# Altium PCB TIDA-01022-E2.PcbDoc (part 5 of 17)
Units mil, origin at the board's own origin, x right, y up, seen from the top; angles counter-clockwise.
Board outline 6929.13 x 11614.17 mil, 12 copper layers (L1_Top Layer, L2_GND, L3_GND, L4_Signal Layer 1, L5_GND, L6_PWR, L7_GND/PWR, L8_PWR, L9_GND/PWR, L10_Signal Layer 2, L11_GND, L12_Bottom Layer), stack 64.6 mil thick; 1711 components, 1002 nets, 5985 pads, 3200 vias.

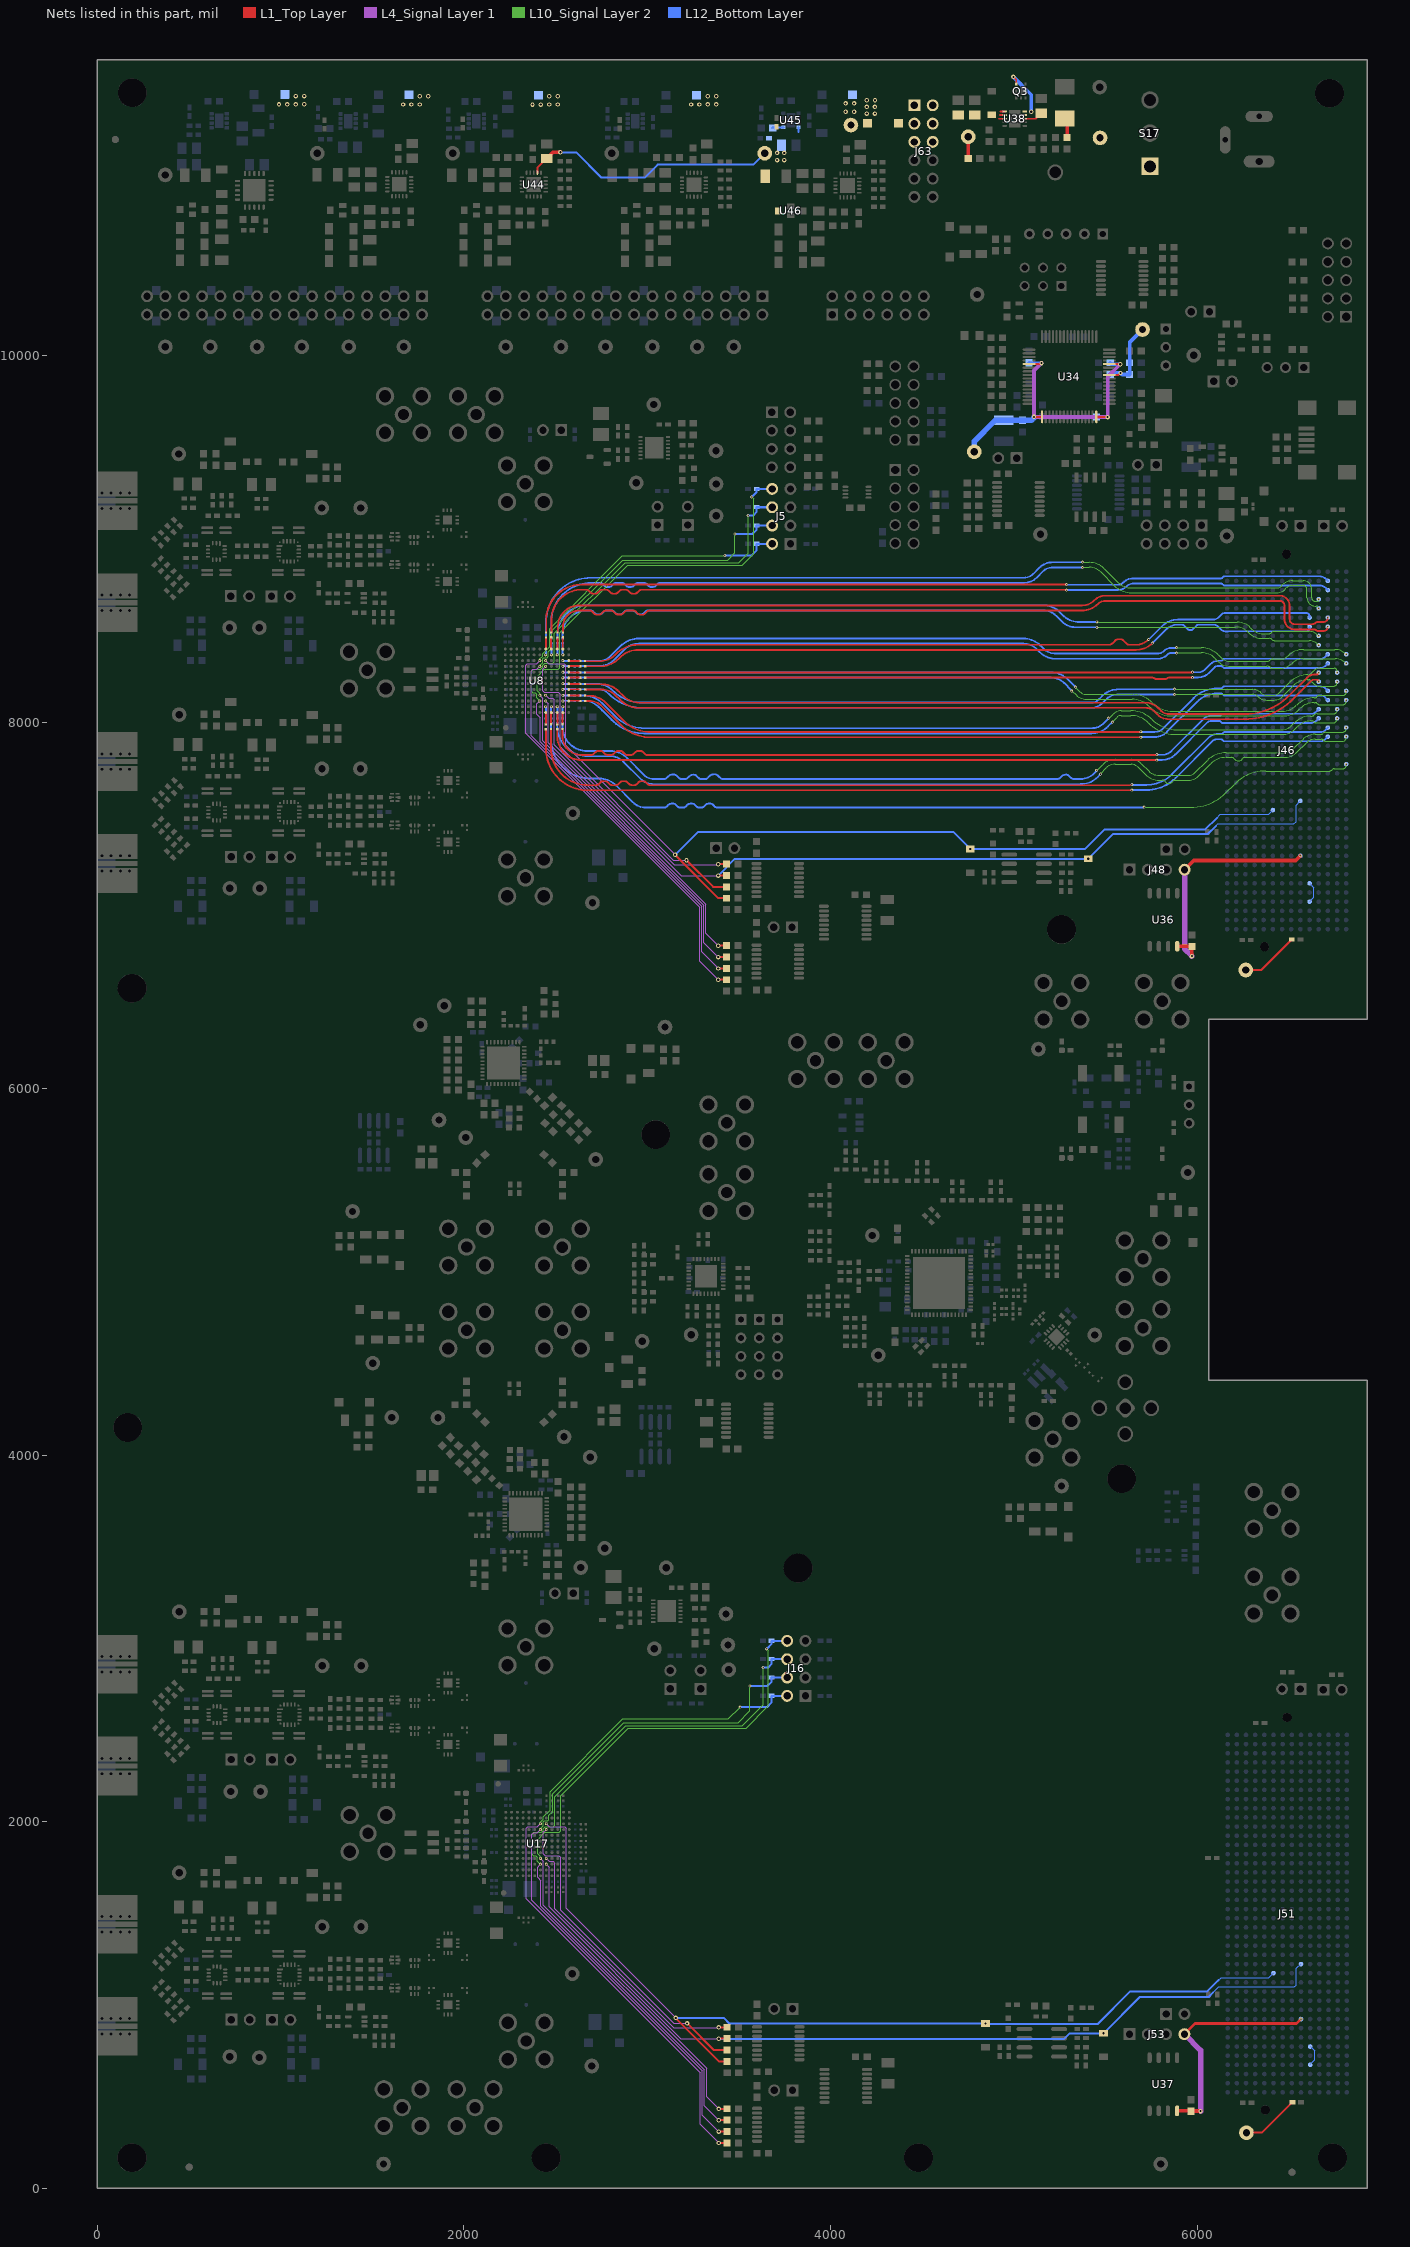
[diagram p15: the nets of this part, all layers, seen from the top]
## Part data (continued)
U55 U57 U58: "Remote 8-Bit I2C and Low-Power I/O Expander With Interrupt Output and Configuration Registers, PW0016A (TSSOP-16)"
U56: "1K Microwire Compatible Serial EEPROM"
U59 U60 U61 U62: "Broadband Balun, 500 kHz to 6 GHz"
U63 U64: "Single 2-Input Positive-AND Gate, DCK0005A (SOT-5)"
U65 U66 U67 U68 U69 U70 U71 U72: library part CMP-0077784-1, "Reflectionless Low Pass Filter, SMD"
U73: "Automotive LVDS Differential Line Receiver, 5-pin SOT-23, Pb-Free"
U74: library part NB7V32M, "1.8V / 2.5V, 10GHz ÷4 Clock Divider with CML Outputs, QFN-16"
U75: "IC, SPDT Analog Switch"
Y1: "VCXO, 100 MHz, 3.3V, SMD"
Y2: "Crystal, 12Mhz, 18pF, SMD"
ZZ1: library part AssemblyNoteLabel
ZZ2 ZZ3 ZZ4: library part AssemblyNote

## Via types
v1: diameter 16, hole 8, L1_Top Layer to L12_Bottom Layer, tented both sides, 1699 vias
v2: diameter 24, hole 12, L1_Top Layer to L12_Bottom Layer, tented both sides, 1501 vias

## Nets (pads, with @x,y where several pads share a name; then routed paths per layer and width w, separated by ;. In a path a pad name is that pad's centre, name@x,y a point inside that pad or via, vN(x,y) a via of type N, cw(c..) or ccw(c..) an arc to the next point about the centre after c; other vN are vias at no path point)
1P8V_USB: C459.2 C460.2 C461.2 C474.1 C736.1 TP14.1 U34.12 U34.37 U34.49 U34.64 | length 1895.7
  L1_Top Layer w10: U34.37@5083.38,9952.87 5145.27,9952.87 v2(5150.87,9958.47) ; v2(5110,9665) 5153.78,9665 U34.49@5154.25,9665.47 ; U34.64@5449.52,9665.47 5451.02,9663.97 v2(5511.37,9663.97) ; U34.12@5520.39,9952.87 5580.47,9952.87 v2(5580.87,9952.47)
  L4_Signal Layer 1 w20: v2(5150.87,9958.47) 5110,9917.6 v2(5110,9665) 5111.03,9663.97 v2(5511.37,9663.97) 5511.37,9882.97 v2(5580.87,9952.47)
  L12_Bottom Layer w10: v2@5145.9,9958.24 5146.13,9958.47 v2(5150.87,9958.47)
  L12_Bottom Layer w20: C461.2@5083.38,9960.74 5085.88,9958.24 v2@5145.9,9958.24 ; C459.2@5450.38,9663.97 v2(5511.37,9663.97) ; C460.2@5525.38,9959.97 5532.88,9952.47 v2(5580.87,9952.47)
  L12_Bottom Layer w30: TP14.1@4784,9475 4784,9532 4897.56,9645.56 C474.1@4944.87,9645.56 5047.46,9645.56 C736.1@5047.87,9645.97 5095.37,9645.97 5110,9660.59 v2(5110,9665)
3P3USB: C466.1 C467.2 L33.2 TP13.1 U34.9 | length 453.6
  L1_Top Layer w10: U34.9@5520.39,9893.81 5570.21,9893.81 5580.87,9904.47 v2(5581.87,9904.47)
  L12_Bottom Layer w20: C467.2@5525.38,9895.97 5533.88,9904.47 v2(5581.87,9904.47) 5590.37,9895.97 C466.1@5631.39,9895.97 L33.2@5631.39,9959.97 5631.39,10070.99 TP13.1@5701.87,10141.47
3P3V_RX1: 3P3V_RX1.1 R474.1 | length 319.4
  L1_Top Layer w11: 3P3V_RX1.1@6265.36,6647.2 6349.43,6647.2 R474.1@6515.86,6813.63
3P3V_RX2: 3P3V_RX2.1 R479.1 | length 319.4
  L1_Top Layer w11: 3P3V_RX2.1@6269,304 6353.07,304 R479.1@6519.5,470.43
3P3VAUX1: C475.1 J46.D32 J48.4 U36.8 | length 1284.5
  L1_Top Layer w20: U36.8@5891.21,6776.68 5967.95,6776.68 cw(c5967.95,6771.55) 5971.58,6775.18 5971,6774.6 v2(5971,6723) ; J48.4@5931.21,7194.68 5981.54,7245.01 6538.11,7245.01 v1(6563.11,7270.01)
  L4_Signal Layer 1 w30: J48.4@5931.21,7194.68 5931.21,6762.79 v2(5971,6723)
3P3VAUX2: C476.1 J51.D32 J53.4 U37.8 | length 1254.4
  L1_Top Layer w15: J53.4@5930.4,841.39 5988.82,899.81 6542.24,899.81 v1(6566.44,924.01)
  L1_Top Layer w20: U37.8@5890.4,423.39 5967.14,423.39 cw(c5967.14,418.26) 5970.77,421.89 v2(6018.28,421.89)
  L4_Signal Layer 1 w30: J53.4@5930.4,841.39 6018.28,753.51 v2(6018.28,421.89)
3P5_VIN: C594.1 C601.1 R513.2 R514.2 R515.2 R621.2 TP32.1 U44.12 U45.4 U45.5 U46.1 | length 1503.7
  L1_Top Layer w10: U44.12@2400.41,10997.46 2400.41,11023.85 C594.1@2451.09,11074.54
  L1_Top Layer w20: C594.1@2451.09,11074.54 2485.19,11108.63 v2(2526.2,11108.63)
  L12_Bottom Layer w10: R514.2@3681.29,11241.46 3684.23,11244.4 U45.5@3742.33,11244.4 ; 3825.01,11217.49 U45.4@3825.01,11244.4
  L12_Bottom Layer w11: v2(2526.2,11108.63) 2611.37,11108.63 2750,10970 2986,10970 3057,11041 3578.93,11041 TP32.1@3640.93,11103
  other v2: 3708,11066 3747,11066 3708,11105 3747,11105
12P0V_RX1: J46.C35 J46.C37 | length 120
  L12_Bottom Layer w5: J46.C37@6613.11,7020.01 6637.21,7044.11 6637.21,7095.91 J46.C35@6613.11,7120.01
12P0V_RX2: J51.C35 J51.C37 | length 120.7
  L12_Bottom Layer w5: J51.C37@6616.75,676.81 6641.75,701.81 6641.75,751.81 J51.C35@6616.75,776.81
12V: C477.1 C478.1 D20.1 J63.1 J63.2 J63.3 J63.4 J63.5 J63.6 L92.1 R485.2 TP18.1 U38.6 U38.7 U38.8 | length 196.5
  L1_Top Layer w10: 4919.4,11291.8 U38.8@4949.58,11291.8 ; 4925.09,11311.49 U38.7@4949.58,11311.49 ; 4925.77,11331.17 U38.6@4949.58,11331.17
  L1_Top Layer w20: R485.2@4750.82,11074.8 TP18.1@4750.82,11192.8
12V_DC: C479.1 D19.2 Q3.3 R484.2 S17.1 TP17.1 U38.3 U38.4 U38.5 | length 486.6
  L1_Top Layer w10: v2(4997.32,11519.73) 5012.82,11504.23 Q3.3@5012.82,11480.8 ; U38.3@5059.82,11291.8 5119.4,11291.8 C479.1@5149.32,11321.73
  L1_Top Layer w20: D19.2@5277.82,11292.8 5290.31,11280.3 R484.2@5290.31,11188.8
  L12_Bottom Layer w20: v2(4997.32,11519.73) 5094.32,11422.73 v2(5094.32,11329.73)
12VIN: L87.2 L88.2 L89.2 L90.2 L91.1 L92.2 TP77.1
  other v2: 4196.85,11319.34 4241.85,11319.34 4082.18,11330 4128.34,11330.08 4197,11356 4242,11356 1667.89,11369.14 1712.89,11369.14 1759.05,11369.21 2373.84,11368.92 2418.84,11368.92 2465,11369 2511.16,11369.08 990.84,11369.92 1035.84,11369.92 1082,11370 1128.16,11370.08 3239.09,11369.47 3284.09,11369.47 3330.26,11369.54 3376.42,11369.62 4082.18,11375 4128.34,11375.08 4197.15,11392.66 4242.15,11392.66 1759.05,11414.21 1805.21,11414.29 2465,11414 2511.16,11414.08 1082,11415 1128.16,11415.08 3330.26,11414.54 3376.42,11414.62
AADC1_NCOA0: J5.2 R59.1 R432.2 U8.C7 | length 3943.9
  L1_Top Layer w6: v2(3387.07,6593.73) v2@3387.56,6594.22
  L1_Top Layer w11: v2@3387.56,6594.22 R432.2@3431.97,6594.22
  L4_Signal Layer 1 w3.5: 2336.17,8025.29 2336.17,8310 2345.17,8319 2397.58,8319 v1(2413.91,8335.33)
  L4_Signal Layer 1 w5.5: 2336.17,8025.29 2336.17,7938.83 3285.5,6989.5 3285.5,6695.3 v2(3387.07,6593.73)
  L10_Signal Layer 2 w3.5: v1(2413.91,8335.33) 2413.91,8344.24 2429.91,8360.24 2429.91,8373.25 2466.67,8410.01 2466.67,8466.17
  L10_Signal Layer 2 w6.5: 2466.67,8466.17 2466.67,8510 2863.67,8907 3420.47,8907 v1(3423,8909.53)
  L12_Bottom Layer w11: v1(3423,8909.53) 3570,8909.53 3596.7,8936.23 R59.1@3596.7,8971.88 J5.2@3681.08,8971.88 ; J5.2@3649.67,8972 J5.2@3675.01,8997.33
AADC1_NCOA1: J5.4 R58.1 R434.2 U8.D7 | length 3891.3
  L1_Top Layer w6: v2(3387.07,6655.73) v2@3387.56,6656.22
  L1_Top Layer w11: v2@3387.56,6656.22 R434.2@3431.97,6656.22
  L4_Signal Layer 1 w3.5: 2367,8025.29 2367,8278 2376.09,8287.09 2397.17,8287.09 v1(2413.91,8303.83)
  L4_Signal Layer 1 w5.5: 2367,8025.29 2367,7925 3297,6995 3297,6745.8 v2(3387.07,6655.73)
  L10_Signal Layer 2 w3.5: v1(2413.91,8303.83) 2413.91,8309.24 2429.41,8324.74 2429.41,8345.74 2435,8351.33 2453,8351.33 2460.16,8358.49 2460.16,8382.49 2479.67,8402 2479.67,8466.67
  L10_Signal Layer 2 w6.5: 2479.67,8466.67 2479.67,8498 2865.67,8884 3438,8884 3478.36,8924.36 v1(3478.36,9025.89)
  L12_Bottom Layer w11: v1(3478.36,9025.89) 3573.36,9025.89 3596.7,9049.23 R58.1@3596.7,9071.88 J5.4@3681.08,9071.88
AADC1_NCOB0: J5.6 R53.1 R436.2 U8.K7 | length 3980.2
  L1_Top Layer w6: v2(3387.07,6717.73) v2@3387.56,6718.22
  L1_Top Layer w11: v2@3387.56,6718.22 R436.2@3431.97,6718.22
  L4_Signal Layer 1 w3.5: v1(2413.91,8114.86) 2398,8098.94 2398,8042 2415.63,8024.37
  L4_Signal Layer 1 w5.5: 2415.63,8024.37 2415.63,7893.37 3308.5,7000.5 3308.5,6796.3 v2(3387.07,6717.73)
  L10_Signal Layer 2 w3.5: 2365.67,8273 2365.67,8263 2365.67,8171 2375.56,8161.1 2388.53,8161.1 2397.17,8152.46 2397.17,8131.6 v1(2413.91,8114.86) ; 2365.67,8263 2365.67,8273 2365.67,8276.45 2377.06,8287.84 2418.78,8287.84 2429.41,8298.47 2429.41,8309 2440.25,8319.83 2484.5,8319.83 2492.67,8328 2492.67,8459.17
  L10_Signal Layer 2 w6.5: 2492.67,8459.17 2492.67,8484 2878.67,8870 3500,8870 3550.36,8920.36 v1(3550.36,9126.54)
  L12_Bottom Layer w6: R53.1@3596.7,9170.88 3597.7,9171.88 R53.1@3596.7,9172.88
  L12_Bottom Layer w11: v1(3550.36,9126.54) 3577.02,9126.54 3596.7,9146.23 3596.7,9170.88 R53.1@3596.7,9172.88 ; R53.1@3597.7,9171.88 J5.6@3681.08,9171.88
AADC1_NCOB1: J5.8 R52.1 R438.2 U8.J7 | length 3947.1
  L1_Top Layer w6: v2(3387.07,6779.73) v2@3387.56,6780.22
  L1_Top Layer w11: v2@3387.56,6780.22 R438.2@3431.97,6780.22
  L4_Signal Layer 1 w3.5: v1(2413.91,8146.35) 2430,8130.27 2430,8025.29
  L4_Signal Layer 1 w5.5: 2430,8025.29 2430,7897 3320,7007 3320,6846.8 v2(3387.07,6779.73)
  L10_Signal Layer 2 w3.5: v1(2413.91,8146.35) 2413.91,8156.99 2399.16,8171.74 2399.16,8248.49 2438.51,8287.84 2515.51,8287.84 2523.67,8296 2523.67,8459.17
  L10_Signal Layer 2 w6.5: 2523.67,8459.17 2523.67,8487 2892.67,8856 3518,8856 3580,8918 3580,9217.25 v1(3569.36,9227.89)
  L12_Bottom Layer w11: v1(3569.36,9227.89) 3596.7,9255.23 R52.1@3596.7,9271.88 J5.8@3681.08,9271.88
AADC1_OVRA0: D2.2 J46.G27 R455.2 U8.C8 | length 5219.7
  L1_Top Layer w6: v2@3152,7274.49 v2(3152,7276)
  L1_Top Layer w11: v2@3152,7274.49 3387.56,7038.93 R455.2@3431.97,7038.93
  L4_Signal Layer 1 w3.5: v1(2445.41,8335.33) 2462.16,8318.58 2546.01,8318.58 2554.65,8309.94 2554.65,8024.35
  L4_Signal Layer 1 w5.5: 2554.65,8024.35 2554.65,7873.35 v2(3152,7276)
  L12_Bottom Layer w5: 6107.09,7476.18 6127.09,7496.18 6389.28,7496.18 J46.G27@6413.11,7520.01
  L12_Bottom Layer w11: v2(3152,7276) 3277,7401 4668.85,7401 v2(4762.2,7307.65) 5388.65,7307.65 5495.18,7414.18 6045.09,7414.18 6107.09,7476.18
AADC1_OVRA1: R458.2 U8.D8 | length 1752.9
  L1_Top Layer w11: v2(3214,7246) 3359.07,7100.93 R458.2@3431.97,7100.93
  L4_Signal Layer 1 w3.5: v1(2445.41,8303.83) 2430,8288.42 2430,8171 2439,8162 2513.61,8162 2524,8151.61 2524,8026
  L4_Signal Layer 1 w5: 2524,8025.29 2524,8026
  L4_Signal Layer 1 w5.5: 2524,8025.29 2524,7864 3142,7246 v2(3214,7246)
AADC1_OVRB0: D4.2 J46.D26 R461.2 U8.K8 | length 4903.2
  L1_Top Layer w11: v2(3387.07,7162.43) 3387.56,7162.93 R461.2@3431.97,7162.93
  L4_Signal Layer 1 w3.5: v1(2445.41,8114.86) 2461,8099.27 2461,8027
  L4_Signal Layer 1 w5: 2461,8025.29 2461,8027
  L4_Signal Layer 1 w5.5: 2461,8025.29 2461,7887 3185.57,7162.43 v2(3387.07,7162.43)
  L12_Bottom Layer w5: 6103.09,7434.18 6113.59,7444.68 6527.71,7444.68 6540.28,7457.25 6540.28,7547.18 J46.D26@6563.11,7570.01
  L12_Bottom Layer w11: v2(3387.07,7162.43) 3477.82,7253.18 5404.74,7253.18 v2(5406.21,7254.65) 5541.73,7390.18 6059.09,7390.18 6103.09,7434.18
AADC1_OVRB1: R464.2 U8.J8 | length 1513.2
  L1_Top Layer w11: v2(3387.07,7224.43) 3387.56,7224.93 R464.2@3431.97,7224.93
  L4_Signal Layer 1 w3.5: v1(2445.41,8146.35) 2462.16,8129.61 2483.02,8129.61 2492,8120.62 2492,8025.29
  L4_Signal Layer 1 w5.5: 2492,8025.29 2492,7877 3146.75,7222.25 3384.89,7222.25 v2(3387.07,7224.43)
AADC2_NCOA0: J16.2 R140.1 R433.2 U17.C7 | length 4011.7
  L1_Top Layer w6: v2(3390.4,247.73) v2@3390.9,248.22
  L1_Top Layer w11: v2@3390.9,248.22 R433.2@3435.31,248.22
  L4_Signal Layer 1 w3.5: 2339.5,1679.29 2339.5,1964 2348.5,1973 2400.91,1973 v1(2417.24,1989.33)
  L4_Signal Layer 1 w5.5: 2339.5,1679.29 2339.5,1579.04 3288.83,629.71 3288.83,349.3 v2(3390.4,247.73)
  L10_Signal Layer 2 w3.5: v1(2417.24,1989.33) 2417.24,1998.24 2433.24,2014.24 2433.24,2027.25 2470,2064.01 2470,2120.17
  L10_Signal Layer 2 w6.5: 2470,2120.17 2470,2164 2867,2561 3441,2561 v1(3506,2626)
  L12_Bottom Layer w11: v1(3506,2626) 3653,2626 3678.34,2651.34 R140.1@3678.34,2686.99 J16.2@3762.72,2686.99
AADC2_NCOA1: J16.4 R139.1 R435.2 U17.D7 | length 4015.1
  L1_Top Layer w6: v2(3390.4,309.73) v2@3390.9,310.22
  L1_Top Layer w11: v2@3390.9,310.22 R435.2@3435.31,310.22
  L4_Signal Layer 1 w3.5: 2370.33,1679.29 2370.33,1932 2379.42,1941.09 2400.5,1941.09 v1(2417.24,1957.84)
  L4_Signal Layer 1 w5.5: 2370.33,1679.29 2370.33,1572 3300.33,642 3300.33,399.8 v2(3390.4,309.73)
  L10_Signal Layer 2 w3.5: v1(2417.24,1957.84) 2417.24,1963.24 2432.74,1978.74 2432.74,1999.74 2438.33,2005.33 2456.33,2005.33 2463.49,2012.49 2463.49,2036.49 2483,2056 2483,2120.67
  L10_Signal Layer 2 w6.5: 2483,2120.67 2483,2152 2872,2541 3496,2541 3560,2605 v1(3560,2741)
  L12_Bottom Layer w11: v1(3560,2741) 3655,2741 3678.34,2764.34 R139.1@3678.34,2786.99 J16.4@3762.72,2786.99
AADC2_NCOB0: J16.6 R134.1 R437.2 U17.K7 | length 4080.3
  L1_Top Layer w6: v2(3390.4,371.73) v2@3390.9,372.22
  L1_Top Layer w11: v2@3390.9,372.22 R437.2@3435.31,372.22
  L4_Signal Layer 1 w3.5: v1(2417.24,1768.86) 2401.33,1752.95 2401.33,1697 2418.96,1679.37
  L4_Signal Layer 1 w5.5: 2418.96,1679.37 2418.96,1540.37 3311.83,647.5 3311.83,450.3 v2(3390.4,371.73)
  L10_Signal Layer 2 w3.5: v1(2417.24,1768.86) 2400.5,1785.61 2400.5,1806.47 2391.86,1815.11 2378.89,1815.11 2369,1825 2369,1917 ; 2496,2113.17 2496,1982 2487.83,1973.83 2443.58,1973.83 2432.74,1963 2432.74,1952.48 2422.11,1941.84 2380.39,1941.84 2369,1930.46 2369,1927 ; 2369,1917 2369,1927 ; 2369,1917 2369,1927
  L10_Signal Layer 2 w6.5: 2496,2113.17 2496,2138 2882,2524 3517,2524 3632,2639 v1(3632,2841.65)
  L12_Bottom Layer w6: R134.1@3678.34,2885.99 R134.1@3679.34,2886.99
  L12_Bottom Layer w11: v1(3632,2841.65) 3658.65,2841.65 3678.34,2861.34 3678.34,2885.99 R134.1@3678.34,2887.99 ; R134.1@3679.34,2886.99 J16.6@3762.72,2886.99
AADC2_NCOB1: J16.8 R133.1 R439.2 U17.J7 | length 4050.5
  L1_Top Layer w6: v2(3390.4,433.73) v2@3390.9,434.22
  L1_Top Layer w11: v2@3390.9,434.22 R439.2@3435.31,434.22
  L4_Signal Layer 1 w3.5: v1(2417.24,1800.36) 2433.33,1784.27 2433.33,1679.29
  L4_Signal Layer 1 w5.5: 2433.33,1679.29 2433.33,1546 3323.33,656 3323.33,500.8 v2(3390.4,433.73)
  L10_Signal Layer 2 w3.5: v1(2417.24,1800.36) 2417.24,1810.99 2402.49,1825.74 2402.49,1902.49 2441.84,1941.84 2518.84,1941.84 2527,1950 2527,2113.17
  L10_Signal Layer 2 w6.5: 2527,2113.17 2527,2141 2896,2510 3539,2510 3661,2632 3661,2933 v1(3651,2943)
  L12_Bottom Layer w11: v1(3651,2943) 3678.34,2970.34 R133.1@3678.34,2986.99 J16.8@3762.72,2986.99
AADC2_OVRA0: D7.2 J51.G27 R456.2 U17.C8 | length 5171.3
  L1_Top Layer w6: v2@3155.33,928.5 v2(3155.33,930)
  L1_Top Layer w11: v2@3155.33,928.5 3390.9,692.93 R456.2@3435.31,692.93
  L4_Signal Layer 1 w3.5: v1(2448.74,1989.33) 2465.49,1972.59 2549.34,1972.59 2557.98,1963.95 2557.98,1678.36
  L4_Signal Layer 1 w5.5: 2557.98,1678.36 2557.98,1527.36 v2(3155.33,930)
  L12_Bottom Layer w5: 6115.9,1135.66 6130.42,1150.19 6390.12,1150.19 J51.G27@6416.75,1176.81
  L12_Bottom Layer w11: v2(3155.33,930) 3418,930 3448.28,899.72 v2(4845.28,899.72) 4848.19,896.81 5456.75,896.81 5634.75,1074.81 6055.05,1074.81 6115.9,1135.66
AADC2_OVRA1: R459.2 U17.D8 | length 1752.9
  L1_Top Layer w11: v2(3217.33,900) 3362.4,754.93 R459.2@3435.31,754.93
  L4_Signal Layer 1 w3.5: v1(2448.74,1957.84) 2433.33,1942.43 2433.33,1825 2442.33,1816 2516.95,1816 2527.33,1805.62 2527.33,1680
  L4_Signal Layer 1 w5: 2527.33,1679.29 2527.33,1680
  L4_Signal Layer 1 w5.5: 2527.33,1679.29 2527.33,1518 3145.33,900 v2(3217.33,900)
AADC2_OVRB0: D9.2 J51.D26 R462.2 U17.K8 | length 4910.4
  L1_Top Layer w11: v2(3390.4,816.44) 3390.9,816.93 R462.2@3435.31,816.93
  L4_Signal Layer 1 w3.5: v1(2448.74,1768.86) 2464.33,1753.27 2464.33,1681
  L4_Signal Layer 1 w5: 2464.33,1679.29 2464.33,1681
  L4_Signal Layer 1 w5.5: 2464.33,1679.29 2464.33,1536 3183.9,816.44 v2(3390.4,816.44)
  L12_Bottom Layer w5: 6087.4,1069.16 6117.05,1098.81 6529.75,1098.81 6540.54,1109.6 6540.54,1200.6 J51.D26@6566.75,1226.81
  L12_Bottom Layer w11: v2(3390.4,816.44) 3392.84,814 5272,814 5302.25,844.25 5439.03,844.25 5439.28,844 5486.58,844 v2(5489.3,846.72) 5686.76,1044.18 6062.42,1044.18 6087.4,1069.16
AADC2_OVRB1: R465.2 U17.J8 | length 1516.7
  L1_Top Layer w11: v2(3390.4,878.44) 3390.9,878.93 R465.2@3435.31,878.93
  L4_Signal Layer 1 w3.5: v1(2448.74,1800.36) 2465.49,1783.61 2486.35,1783.61 2495.33,1774.63 2495.33,1679.29
  L4_Signal Layer 1 w5.5: 2495.33,1679.29 2495.33,1525 3144.08,876.25 3388.22,876.25 v2(3390.4,878.44)
ADC1_DA0+: C71.1 U8.E12 | length 64.5
  L1_Top Layer w10: U8.E12@2571.39,8272.34 2573.55,8270.18 C71.1@2635,8270.18
ADC1_DA0-: C72.1 U8.F12 | length 65.6
  L1_Top Layer w10: U8.F12@2571.39,8240.84 2572.73,8242.18 2635,8242.18 C72.1@2636,8241.18
ADC1_DA0_M: C72.2 J46.A11 | length 4087.4
  L1_Top Layer w10: C72.2@2662.97,8242.18 5042.27,8242.18 ; 5042.27,8242.19 5755.53,8242.19 cw(c5755.53,8220.49) 5765.45,8239.79 ccw(c5777.24,8251.58) 5770.23,8236.45 ccw(c5777.24,8251.58) 5777.24,8234.9 5827.26,8234.9 ccw(c5827.26,8247.72) 5836.33,8238.66 cw(c5844.85,8230.13) 5844.85,8242.19 v1@5974.59,8242.19
  L12_Bottom Layer w10: v1(5974.59,8242.5) 5975.59,8243.5 6005.84,8243.5 ccw(c6005.84,8324.74) 6063.27,8267.28 6093.34,8297.33 cw(c6114.29,8276.39) 6114.28,8306.01 6130.02,8306.01 cw(c6130.02,8296.02) 6137.09,8303.08 6142.23,8297.94 ccw(c6149.3,8305) 6149.3,8295.01 6669.06,8295.01 ccw(c6669.06,8341) 6697.3,8304.7 ccw(c6669.06,8341) 6701.58,8308.48 J46.A11@6713.11,8320.01
ADC1_DA0_P: C71.2 J46.A10 | length 4093.2
  L1_Top Layer w10: C71.2@2660.98,8270.18 5030.67,8270.18 ; 5030.68,8270.19 v1@5969,8270.19 ; v1@5969,8270.19 ccw(c5969,8278.08) v1(5974.59,8272.5) 5972.27,8270.19 v1@5969,8270.19
  L12_Bottom Layer w10: v1(5974.59,8272.5) 5975.59,8271.5 6005.84,8271.5 ccw(c6005.84,8324.73) 6043.47,8287.08 6073.54,8317.13 cw(c6114.29,8276.39) 6114.27,8334.01 6130.02,8334.01 ccw(c6130.02,8344) 6137.09,8336.94 6142.23,8342.08 cw(c6149.3,8335.02) 6149.3,8345.01 6672.48,8345.01 ccw(c6672.48,8382.74) 6699.16,8356.06 J46.A10@6713.11,8370.01
ADC1_DA1+: C73.1 U8.C12 | length 64.5
  L1_Top Layer w10: U8.C12@2571.39,8335.33 2573.55,8333.17 C73.1@2635,8333.16
ADC1_DA1-: C75.1 U8.D12 | length 65.6
  L1_Top Layer w10: U8.D12@2571.39,8303.83 2572.73,8305.17 2635,8305.17 C75.1@2636,8304.17
ADC1_DA1_M: C75.2 J46.C7 | length 4073.9
  L1_Top Layer w10: C75.2@2661.98,8304.17 2710.81,8304.17 2742.45,8304.16 ccw(c2742.45,8447.64) 2843.9,8346.18 2849.45,8351.73 cw(c2950.65,8250.53) 2950.65,8393.65 5666.78,8393.65 ccw(c5666.79,8519.78) v1(5755.97,8430.6)
  L12_Bottom Layer w10: v1(5755.97,8430.6) 5829.63,8504.25 cw(c5894.52,8439.37) 5894.51,8531.13 5917.01,8531.13 cw(c5917.01,8513) 5929.83,8525.82 5948.72,8506.93 ccw(c5960.52,8518.75) 5960.5,8502.05 5965.29,8502.04 ccw(c5965.32,8518.68) 5977.08,8506.91 5996.5,8526.33 cw(c6008.09,8514.74) 6008.09,8531.13 6088.78,8531.13 cw(c6088.78,8493.68) 6115.26,8520.16 6131.14,8504.28 ccw(c6153.74,8526.88) 6153.74,8494.92 6167.45,8494.92 6560.02,8495.01 6595.21,8495.01 ccw(c6595.21,8512.91) 6613.11,8512.91 J46.C7@6613.11,8520.01
ADC1_DA1_P: C73.2 J46.C6 | length 4078
  L1_Top Layer w10: C73.2@2660.98,8333.16 ccw(c2663.41,8335.6) 2663.41,8332.17 2710.81,8332.17 ; 2710.82,8332.16 2742.45,8332.16 ccw(c2742.45,8447.63) 2824.1,8365.98 2829.65,8371.53 cw(c2950.65,8250.53) 2950.65,8421.65 5520.08,8421.65 ccw(c5520.09,8444.06) 5535.93,8428.22 5552.28,8444.57 cw(c5569.23,8427.61) 5569.23,8451.59 5586.01,8451.59 cw(c5578.93,8425.31) 5598.16,8444.57 5610.21,8432.52 5615.25,8427.47 ccw(c5629.28,8441.5) 5629.28,8421.66 5665.36,8421.66 ccw(c5665.36,8519.78) v1(5734.75,8450.4) cw(c5730.98,8450.4) v1@5733.65,8447.74
  L12_Bottom Layer w10: v1(5734.75,8450.4) 5736.17,8450.4 5809.83,8524.06 cw(c5894.52,8439.37) 5894.5,8559.13 6088.79,8559.13 ccw(c6088.78,8596.58) 6115.26,8570.1 6130.73,8585.57 cw(c6153.74,8562.56) 6153.74,8595.1 6167.45,8595.1 6560.02,8595.01 6595.21,8595.01 cw(c6595.21,8577.11) 6613.11,8577.11 J46.C6@6613.11,8570.01
ADC1_DA2+: C76.1 U8.A10 | length 64.5
  L1_Top Layer w10: U8.A10@2508.4,8398.32 2510.56,8400.48 C76.1@2510.56,8461.92
ADC1_DA2-: C77.1 U8.A11 | length 64.2
  L1_Top Layer w10: C77.1@2538.56,8461.92 2538.56,8399.66 U8.A11@2539.9,8398.32
ADC1_DA2_M: C77.2 J46.A7 | length 4450.3
  L1_Top Layer w10: C77.2@2539.56,8488.91 2539.55,8519.66 cw(c2628.12,8519.66) 2628.12,8608.23 2686.63,8608.23 cw(c2686.63,8588.39) 2700.66,8602.42 2705.7,8597.38 2711.07,8592 ccw(c2726.71,8607.64) 2726.71,8585.52 2733.06,8585.52 ccw(c2733.06,8610.85) 2750.97,8592.94 ; 2750.97,8592.94 2755.4,8597.37 2760.4,8602.38 cw(c2774.52,8588.26) 2774.52,8608.23 2803.1,8608.23 cw(c2803.1,8588.39) 2817.13,8602.42 2822.17,8597.38 2827.54,8592 ccw(c2840.77,8605.23) 2840.77,8586.52 2851.94,8586.52 ccw(c2851.94,8608.44) 2867.44,8592.94 2871.87,8597.37 2876.87,8602.38 cw(c2890.99,8588.26) 2890.99,8608.23 2923.75,8608.23 cw(c2923.75,8588.39) 2937.78,8602.42 2942.82,8597.38 2948.19,8592 ccw(c2963.83,8607.64) 2963.83,8585.52 2970.18,8585.52 ccw(c2970.18,8610.85) 2988.09,8592.94 2992.52,8597.37 2997.52,8602.38 cw(c3011.64,8588.26) 3011.64,8608.23 5371.86,8608.23 ccw(c5371.86,8731.52) 5459.04,8644.34 cw(c5499.74,8603.67) 5499.73,8661.2 6450.31,8661.19 cw(c6450.31,8635.1) 6476.4,8635.1 6476.4,8560.59 ccw(c6531.24,8560.59) 6531.24,8505.75 6638.08,8505.75 cw(c6638.07,8492.28) 6647.6,8501.8 ccw(c6660.25,8514.45) 6660.25,8496.56 6689.66,8496.56 ccw(c6689.66,8520.01) v1(6713.11,8520.01)
ADC1_DA2_P: C76.2 J46.A6 | length 4451.8
  L1_Top Layer w10: C76.2@2510.56,8487.91 2511.55,8488.9 2511.55,8519.66 cw(c2628.12,8519.66) 2628.12,8636.23 5371.86,8636.23 ccw(c5371.86,8731.52) 5439.25,8664.14 cw(c5499.74,8603.66) 5499.72,8689.2 6450.31,8689.2 cw(c6450.3,8635.1) 6504.4,8635.1 6504.4,8560.59 ccw(c6531.24,8560.59) 6531.24,8533.75 6628.42,8533.75 ccw(c6628.41,8557.53) 6645.23,8540.72 ; 6645.56,8541.04 cw(c6657,8529.6) 6657,8545.78 6688.88,8545.78 ccw(c6688.88,8570.01) v1(6713.11,8570.01)
ADC1_DA3+: C78.1 U8.A8 | length 64.5
  L1_Top Layer w10: U8.A8@2445.41,8398.32 2447.57,8400.48 C78.1@2447.57,8461.92
ADC1_DA3-: C79.1 U8.A9 | length 65.6
  L1_Top Layer w10: C79.1@2476.57,8462.92 2475.57,8461.92 2475.57,8399.66 U8.A9@2476.91,8398.32
ADC1_DA3_M: C79.2 J46.A3 | length 4464
  L1_Top Layer w10: C79.2@2476.57,8488.91 2476.57,8556.29 cw(c2642.36,8556.29) 2642.36,8722.08 2666.2,8722.08 cw(c2666.2,8702.24) 2680.23,8716.27 2685.27,8711.23 2690.64,8705.85 ccw(c2703.87,8719.08) 2703.87,8700.37 2715.04,8700.37 ccw(c2715.04,8722.29) 2730.54,8706.79 2734.97,8711.22 2739.97,8716.23 cw(c2754.09,8702.11) 2754.09,8722.08 2775.22,8722.08 cw(c2775.22,8702.24) 2789.25,8716.27 2794.29,8711.23 2799.66,8705.85 ccw(c2812.89,8719.08) 2812.89,8700.37 2824.06,8700.37 ccw(c2824.06,8722.29) 2839.56,8706.79 2843.99,8711.22 2848.99,8716.23 cw(c2863.11,8702.11) 2863.11,8722.08 2881.63,8722.08 cw(c2881.63,8702.24) 2895.66,8716.27 2900.7,8711.23 2906.07,8705.85 ccw(c2919.3,8719.08) 2919.3,8700.37 2930.47,8700.37 ccw(c2930.47,8722.29) 2945.97,8706.79 2950.4,8711.22 2955.4,8716.23 cw(c2969.52,8702.11) 2969.52,8722.08 v1@5288.09,8722.08
  L12_Bottom Layer w10: v1(5288.09,8720.18) 5289.09,8721.18 5568.11,8721.18 ccw(c5568.11,8788.78) 5615.91,8740.98 cw(c5652.2,8704.69) 5652.2,8756.01 6130.02,8756.01 cw(c6130.02,8746.02) 6137.09,8753.08 6142.23,8747.94 ccw(c6149.3,8755) 6149.3,8745.01 6669.06,8745.01 cw(c6669.06,8699.02) 6701.58,8731.54 J46.A3@6713.11,8720.01
ADC1_DA3_P: C78.2 J46.A2 | length 4465.7
  L1_Top Layer w10: C78.2@2447.57,8487.91 2448.57,8488.91 2448.57,8556.29 cw(c2642.36,8556.29) 2642.36,8750.08 v1@5288.09,8750.08
  L12_Bottom Layer w10: v1(5288.09,8750.18) 5289.09,8749.18 5568.11,8749.18 ccw(c5568.11,8788.78) 5596.11,8760.78 cw(c5652.2,8704.69) 5652.2,8784.01 6130.02,8784.01 ccw(c6130.02,8794) 6137.09,8786.94 6142.23,8792.08 cw(c6149.3,8785.02) 6149.3,8795.01 6669.06,8795.01 cw(c6669.06,8749.02) 6701.58,8781.54 J46.A2@6713.11,8770.01
ADC1_DA4+: C80.1 U8.E11 | length 65.1
  L12_Bottom Layer w10: v1(2539.9,8272.34) 2541.65,8270.59 2602.9,8270.59 C80.1@2603.9,8271.59
ADC1_DA4-: C81.1 U8.F11 | length 65.1
  L12_Bottom Layer w10: v1(2539.9,8240.84) 2541.65,8242.59 2602.91,8242.59 C81.1@2603.9,8241.6
ADC1_DA4_M: C81.2 J46.Y15 | length 4301.6
  L10_Signal Layer 2 w6.3: v1(5315.75,8168.91) 5318.31,8168.91 5339.42,8147.8 ccw(c5397.05,8205.43) 5397.05,8123.93 5646.84,8123.93 cw(c5646.84,7996.68) 5736.82,8086.66 ccw(c5865.79,8215.63) 5865.79,8033.24 6465.8,8033.24 ccw(c6465.8,8166.2) 6559.81,8072.18 ; 6561.64,8074.01 cw(c6638.83,7996.82) 6638.83,8105.98 6643.24,8105.98 ; v1(6813.11,8120.01) 6813.11,8113.16 cw(c6794.63,8113.16) 6794.63,8094.68 6670.52,8094.68 cw(c6670.52,8116.05) 6655.41,8100.94 ; 6643.24,8105.98 cw(c6643.24,8088.77) 6655.41,8100.94 ; 6643.24,8105.98 cw(c6643.23,8088.77) 6650.97,8104.14 cw(c6643.26,8088.76) 6655.41,8100.94
  L12_Bottom Layer w10: C81.2@2629.88,8241.6 2630.87,8242.59 5203.54,8242.59 cw(c5203.54,8143.27) 5273.77,8213.5 5313.9,8173.36 cw(c5309.45,8168.91) v1(5315.75,8168.91)
ADC1_DA4_P: C80.2 J46.Y14 | length 4288.3
  L10_Signal Layer 2 w6.3: v1(5336.97,8190.13) 5336.97,8187.59 5358.09,8166.47 ccw(c5397.05,8205.43) 5397.04,8150.33 5646.85,8150.33 cw(c5646.85,7996.68) 5755.49,8105.33 ccw(c5865.79,8215.63) 5865.78,8059.64 6465.79,8059.64 ccw(c6465.79,8166.2) 6541.14,8090.85 ; 6542.97,8092.68 cw(c6638.82,7996.82) 6638.82,8132.38 6643,8132.38 ccw(c6643.01,8144.48) 6651.56,8135.92 ; 6652.6,8136.97 6656.25,8140.62 cw(c6666.85,8130.02) 6666.85,8145.01 6794.96,8145.01 ccw(c6794.96,8163.16) 6813.11,8163.16 v1(6813.11,8170.01)
  L12_Bottom Layer w10: C80.2@2629.88,8271.59 2630.88,8270.59 5203.54,8270.59 cw(c5203.54,8143.27) 5293.57,8233.3 5336.73,8190.13 v1(5336.97,8190.13)
ADC1_DA5+: C84.1 U8.C11 | length 65.1
  L12_Bottom Layer w10: v1(2539.9,8335.33) 2541.65,8333.58 2602.9,8333.58 C84.1@2603.9,8334.58
ADC1_DA5-: C85.1 U8.D11 | length 65.1
  L12_Bottom Layer w10: v1(2539.9,8303.83) 2541.65,8305.58 2602.91,8305.58 C85.1@2603.9,8304.59
ADC1_DA5_M: C85.2 J46.Y11 | length 4304
  L10_Signal Layer 2 w6.3: v1(5888.27,8376.45) 5890.07,8378.25 6023.31,8378.25 cw(c6023.31,8273.98) 6097.04,8347.71 6115.73,8329.02 ccw(c6172.73,8386.02) 6172.73,8305.41 6380.57,8305.41 cw(c6380.57,8281.2) 6397.69,8298.32 ccw(c6408.75,8309.38) 6408.75,8293.74 6454.73,8293.74 ccw(c6454.73,8379.68) 6515.5,8318.91 cw(c6578.46,8255.95) 6578.46,8344.99 6752.8,8344.99 cw(c6752.8,8259.7) v1(6813.11,8320.01)
  L12_Bottom Layer w10: C85.2@2629.88,8304.59 2630.87,8305.58 2739.15,8305.58 ccw(c2739.15,8416.99) 2817.93,8338.21 2875.14,8395.42 cw(c2953.8,8316.75) 2953.8,8428 4896.67,8428 5052.84,8428.01 cw(c5052.84,8328.01) 5123.55,8398.72 5139.6,8382.67 ccw(c5230.11,8473.18) 5230.11,8345.18 5781.46,8345.18 ccw(c5781.46,8427.81) 5839.89,8369.38 cw(c5856.3,8352.97) 5856.3,8376.18 v1@5888.27,8376.18
ADC1_DA5_P: C84.2 J46.Y10 | length 4306.6
  L10_Signal Layer 2 w6.3: v1(5888.27,8406.45) 5890.07,8404.65 6023.32,8404.65 cw(c6023.31,8273.98) 6115.7,8366.38 6134.4,8347.69 ccw(c6172.73,8386.01) 6172.73,8331.81 6381.11,8331.81 ccw(c6381.11,8356.84) 6398.81,8339.14 cw(c6412.88,8325.07) 6412.88,8344.97 6458.3,8344.97 ccw(c6458.3,8395.43) 6493.98,8359.75 cw(c6580.29,8273.44) 6580.29,8395.5 6751.57,8395.5 cw(c6751.57,8308.47) v1(6813.11,8370.01)
  L12_Bottom Layer w10: C84.2@2629.88,8334.58 2630.88,8333.58 2739.15,8333.58 ccw(c2739.15,8416.99) 2798.13,8358.01 2855.34,8415.22 cw(c2953.8,8316.75) 2953.8,8456 4832.67,8456 ; 4832.68,8456.01 5052.84,8456.01 cw(c5052.84,8328.01) 5143.35,8418.52 5159.4,8402.47 ccw(c5230.11,8473.18) 5230.11,8373.18 5781.46,8373.18 ccw(c5781.46,8427.81) 5820.09,8389.18 cw(c5856.3,8352.97) 5856.3,8404.18 5888.27,8404.18 v1(5888.27,8406.45)
ADC1_DA6+: C86.1 U8.B10 | length 65.1
  L12_Bottom Layer w10: v1(2508.4,8366.83) 2509.65,8368.08 2509.65,8430 C86.1@2508.65,8431
ADC1_DA6-: C87.1 U8.B11 | length 65.5
  L12_Bottom Layer w10: C87.1@2538.64,8431 2537.65,8430.01 2537.65,8369.07 v1@2539.89,8366.83
  other v1: 2539.9,8366.83
ADC1_DA6_M: C87.2 J46.B9 | length 4321.7
  L10_Signal Layer 2 w6.3: v1(5453.18,8516.39) 5454.98,8518.19 6208.82,8518.19 cw(c6208.82,8418.19) 6279.53,8488.9 6279.69,8488.74 ccw(c6358.51,8567.56) 6358.51,8456.09 6394.15,8456.09 cw(c6394.15,8433.62) 6410.04,8449.51 ccw(c6423,8462.47) 6423,8444.14 6611.14,8444.14 cw(c6611.13,8376.93) 6658.66,8424.45 v1(6663.11,8420.01)
  L12_Bottom Layer w10: C87.2@2538.64,8456.98 2537.64,8457.98 2537.64,8474.69 cw(c2672.43,8474.69) 2672.43,8609.48 2690.02,8609.48 cw(c2690.02,8589.64) 2704.05,8603.67 2709.09,8598.63 2714.46,8593.25 ccw(c2727.69,8606.48) 2727.69,8587.77 2738.86,8587.77 ccw(c2738.86,8609.69) 2754.36,8594.19 2758.79,8598.62 2763.79,8603.63 cw(c2777.91,8589.51) 2777.91,8609.48 2803.34,8609.48 cw(c2803.34,8589.64) 2817.37,8603.67 2822.41,8598.63 2827.78,8593.25 ccw(c2841.01,8606.48) 2841.01,8587.77 2852.18,8587.77 ccw(c2852.18,8609.69) 2867.68,8594.19 2872.11,8598.62 2877.11,8603.63 cw(c2891.23,8589.51) 2891.23,8609.48 2917.15,8609.48 cw(c2917.15,8589.64) 2931.18,8603.67 2936.22,8598.63 2941.59,8593.25 ccw(c2954.82,8606.48) 2954.82,8587.77 2965.99,8587.77 ccw(c2965.99,8609.69) 2981.49,8594.19 2985.92,8598.62 2990.92,8603.63 cw(c3005.04,8589.51) 3005.04,8609.48 4925.26,8609.48 ; 4925.27,8609.49 5159.94,8609.49 cw(c5159.94,8509.49) 5230.65,8580.2 5264.17,8546.68 ccw(c5334.88,8617.39) 5334.88,8517.39 5452.18,8517.39 v1(5453.18,8516.39)
ADC1_DA6_P: C86.2 J46.B8 | length 4320.7
  L10_Signal Layer 2 w6.3: v1(5453.18,8546.39) 5454.98,8544.59 6219.53,8544.59 cw(c6219.53,8444.05) 6290.62,8515.14 6298.36,8507.41 ccw(c6358.52,8567.56) 6358.52,8482.49 6393.32,8482.49 ccw(c6393.32,8499.32) 6405.22,8487.42 ; 6405.24,8487.44 cw(c6421.42,8471.26) 6421.42,8494.14 6611.14,8494.14 cw(c6611.13,8426.93) 6658.66,8474.45 v1(6663.11,8470.01)
  L12_Bottom Layer w10: C86.2@2508.65,8456.98 2509.64,8457.97 2509.64,8474.69 cw(c2672.43,8474.69) 2672.43,8637.48 4913.66,8637.48 ; 4913.67,8637.49 5159.94,8637.49 cw(c5159.94,8509.49) 5250.45,8600 5267.57,8582.88 ccw(c5358.08,8673.39) 5358.08,8545.39 5452.18,8545.39 v1(5453.18,8546.39)
ADC1_DA7+: C88.1 U8.B8 | length 62.9
  L12_Bottom Layer w10: v1@2446.67,8368.09 C88.1@2446.67,8431
  other v1: 2445.41,8366.83
ADC1_DA7-: C89.1 U8.B9 | length 63.9
  L12_Bottom Layer w10: v1@2476.66,8367.08 C89.1@2476.66,8431
  other v1: 2476.91,8366.83
ADC1_DA7_M: C89.2 J46.B5 | length 4620.3
  L10_Signal Layer 2 w6.3: v1(5374.88,8842.82) 5376.68,8844.62 5411.05,8844.62 cw(c5411.05,8756.19) 5473.58,8818.72 5548.02,8744.26 ; 5548.03,8744.27 ccw(c5641.8,8838.05) 5641.82,8705.43 6435.61,8705.43 ccw(c6435.6,8764.33) 6477.25,8722.68 6483.63,8729.06 cw(c6522.55,8690.14) 6522.54,8745.18 6577.41,8745.18 cw(c6577.41,8723.5) 6599.09,8723.5 6599.09,8678.36 ccw(c6644.41,8678.36) 6644.41,8633.04 6650.08,8633.04 cw(c6650.08,8620.01) v1(6663.11,8620.01)
  L12_Bottom Layer w10: C89.2@2476.66,8456.98 2475.66,8457.98 2475.66,8543.99 cw(c2690.86,8543.99) 2690.86,8759.19 2742.82,8759.19 cw(c2742.82,8739.35) 2756.85,8753.38 2761.89,8748.34 ; 2761.89,8748.33 2767.26,8742.96 ccw(c2780.73,8756.43) 2780.73,8737.38 2791.42,8737.38 ccw(c2791.42,8759.64) 2807.16,8743.9 2811.59,8748.33 ; 2811.59,8748.34 2816.59,8753.34 cw(c2830.71,8739.22) 2830.71,8759.19 2861.53,8759.19 cw(c2861.53,8739.35) 2875.56,8753.38 2880.6,8748.34 ; 2880.6,8748.33 2885.97,8742.96 ccw(c2899.22,8756.21) 2899.22,8737.47 2910.35,8737.47 ccw(c2910.35,8759.42) 2925.87,8743.9 ; 2925.87,8743.9 2930.3,8748.33 ; 2930.3,8748.34 2935.3,8753.34 cw(c2949.42,8739.22) 2949.42,8759.19 2982.48,8759.19 cw(c2982.48,8739.35) 2996.51,8753.38 3001.55,8748.34 ; 3001.55,8748.33 3006.92,8742.96 ccw(c3020.15,8756.19) 3020.15,8737.48 3031.32,8737.48 ccw(c3031.32,8759.4) 3046.82,8743.9 3051.25,8748.33 ; 3051.25,8748.34 3056.25,8753.34 cw(c3070.37,8739.22) 3070.37,8759.19 4896.48,8759.19 4896.67,8759 ; 4896.67,8759.2 5055.09,8759.2 ccw(c5055.09,8857.25) 5124.42,8787.92 5157.89,8821.38 cw(c5212.06,8767.21) 5212.06,8843.82 v1@5374.88,8843.82
ADC1_DA7_P: C88.2 J46.B4 | length 4619.1
  L10_Signal Layer 2 w6.3: v1(5374.88,8872.82) 5376.68,8871.02 5411.04,8871.02 cw(c5411.06,8756.19) 5492.25,8837.39 5566.7,8762.94 ccw(c5641.81,8838.05) 5641.81,8731.83 6435.6,8731.83 ccw(c6435.6,8764.33) 6458.58,8741.35 6464.95,8747.73 cw(c6522.54,8690.13) 6522.54,8771.58 6577.41,8771.58 cw(c6577.41,8723.5) 6625.49,8723.5 6625.49,8678.36 ccw(c6644.41,8678.36) 6644.41,8659.44 6656.38,8659.44 ccw(c6656.38,8666.17) 6663.11,8666.17 v1(6663.11,8670.01)
  L12_Bottom Layer w10: C88.2@2447.66,8457.97 2447.66,8543.99 cw(c2690.86,8543.99) 2690.86,8787.19 4846.67,8787.19 ; 4846.68,8787.2 5055.09,8787.2 ccw(c5055.09,8857.25) 5104.62,8807.71 5138.09,8841.18 cw(c5212.06,8767.21) 5212.06,8871.82 v1@5374.67,8871.82
ADC1_DB0+: C96.1 U8.H12 | length 65.6
  L1_Top Layer w10: U8.H12@2571.39,8177.85 2572.73,8179.19 2635,8179.19 C96.1@2636,8178.19
ADC1_DB0-: C98.1 U8.G12 | length 64.5
  L1_Top Layer w10: U8.G12@2571.39,8209.35 2573.55,8207.19 C98.1@2635,8207.19
ADC1_DB0_M: C98.2 J46.B12 | length 4132.3
  L1_Top Layer w10: C98.2@2660.98,8207.19 ccw(c2663.39,8209.6) 2663.39,8206.19 2749.74,8206.19 cw(c2749.74,8070.54) 2845.65,8166.46 2871.71,8140.42 ccw(c2955.46,8224.17) 2955.45,8105.73 5716.8,8105.73 cw(c5716.8,8006.3) 5785.91,8077.78 ; 5787.11,8076.61 ccw(c5716.8,8006.3) 5785.91,8077.78 ; v1(6663.11,8270.01) cw(c6652.11,8270.01) 6652.11,8259.01 6638.73,8259.01 ccw(c6638.73,8203.7) 6599.62,8242.81 6499.07,8142.26 cw(c6260.55,8380.78) 6260.55,8043.46 5844.63,8043.46 cw(c5844.63,8100) 5804.65,8060.02 5795.67,8069 ccw(c5706.99,7980.32) 5785.91,8077.78
ADC1_DB0_P: C96.2 J46.B13 | length 4129.3
  L1_Top Layer w10: C96.2@2661.98,8178.19 2749.75,8178.19 cw(c2749.74,8070.54) 2825.86,8146.66 2851.91,8120.62 ccw(c2955.46,8224.17) 2955.46,8077.73 5716.8,8077.73 cw(c5716.8,8006.3) 5767.31,8056.81 cw(c5706.99,7980.32) 5775.87,8049.2 5784.85,8040.22 ccw(c5844.63,8100) 5844.63,8015.46 6260.55,8015.46 ccw(c6260.55,8380.78) 6518.87,8122.46 6619.42,8223.01 cw(c6638.73,8203.71) 6638.73,8231.01 6652.11,8231.01 cw(c6652.11,8220.01) v1(6663.11,8220.01)
ADC1_DB1+: C100.1 U8.K12 | length 65.6
  L1_Top Layer w10: U8.K12@2571.39,8114.86 2572.73,8116.2 2635,8116.2 C100.1@2636,8115.2
ADC1_DB1-: C101.1 U8.J12 | length 64.5
  L1_Top Layer w10: U8.J12@2571.39,8146.35 2573.55,8144.2 C101.1@2635,8144.2
ADC1_DB1_M: C101.2 J46.A14 | length 4220.7
  L1_Top Layer w10: C101.2@2660.98,8144.2 ccw(c2663.39,8146.61) 2663.39,8143.2 2683.95,8143.2 cw(c2683.95,8017.55) 2772.8,8106.39 2874.98,8004.23 ccw(c3018.28,8147.52) 3018.28,7944.87 5027.67,7944.87 ; 5027.68,7944.87 v1@5692.65,7944.87
  L12_Bottom Layer w10: v1(5692.65,7947.19) 5693.65,7946.19 5768.09,7946.19 ccw(c5768.09,8013.17) 5815.45,7965.81 5980.6,8130.96 cw(c6108.68,8002.88) 6108.68,8184.01 6130.02,8184.01 ccw(c6130.02,8194) 6137.09,8186.94 6142.23,8192.08 cw(c6149.3,8185.02) 6149.3,8195.01 6669.06,8195.01 cw(c6669.06,8149.02) 6701.58,8181.54 J46.A14@6713.11,8170.01
ADC1_DB1_P: C100.2 J46.A15 | length 4219.8
  L1_Top Layer w10: C100.2@2661.98,8115.2 2683.95,8115.2 cw(c2683.95,8017.55) 2753,8086.59 2855.18,7984.43 ccw(c3018.28,8147.52) 3018.27,7916.87 5039.27,7916.87 ; 5039.27,7916.87 v1@5692.65,7916.87
  L12_Bottom Layer w10: v1(5692.65,7917.19) 5693.65,7918.19 5768.09,7918.19 ccw(c5768.09,8013.17) 5835.25,7946.01 6000.4,8111.16 cw(c6108.68,8002.88) 6108.68,8156.01 6130.02,8156.01 cw(c6130.02,8146.02) 6137.09,8153.08 6142.23,8147.94 ccw(c6149.3,8155) 6149.3,8145.01 6672.48,8145.01 cw(c6672.48,8107.28) 6699.16,8133.96 J46.A15@6713.11,8120.01
ADC1_DB2+: C102.1 U8.M10 | length 65.6
  L1_Top Layer w10: U8.M10@2508.4,8051.87 2509.74,8050.53 2509.74,7988.26 C102.1@2508.74,7987.26
ADC1_DB2-: C103.1 U8.M11 | length 64.5
  L1_Top Layer w10: C103.1@2537.74,7988.26 2537.74,8049.71 U8.M11@2539.9,8051.87
ADC1_DB2_M: C103.2 J46.B16 | length 4363.5
  L1_Top Layer w10: C103.2@2537.74,7962.28 2536.75,7961.29 2536.75,7923.83 ccw(c2639.73,7923.83) 2639.73,7820.85 2694.36,7820.85 ccw(c2694.36,7840.82) 2708.48,7826.7 2713.48,7831.7 2717.91,7836.14 cw(c2733.41,7820.64) 2733.41,7842.56 2744.58,7842.56 cw(c2744.58,7823.85) 2757.81,7837.08 2763.18,7831.71 2768.22,7826.66 ccw(c2782.25,7840.69) 2782.25,7820.85 2802.17,7820.85 ccw(c2802.17,7840.82) 2816.29,7826.7 2821.29,7831.7 2825.72,7836.14 cw(c2841.22,7820.64) 2841.22,7842.56 2852.39,7842.56 cw(c2852.39,7823.85) 2865.62,7837.08 2870.99,7831.71 2876.03,7826.66 ccw(c2890.06,7840.69) 2890.06,7820.85 2911.62,7820.85 ccw(c2911.62,7840.82) 2925.74,7826.7 2930.74,7831.7 2935.17,7836.14 cw(c2950.67,7820.64) 2950.67,7842.56 2961.84,7842.56 cw(c2961.84,7823.85) 2975.07,7837.08 2980.44,7831.71 2985.48,7826.66 ccw(c2999.51,7840.69) 2999.51,7820.85 5773.37,7820.85 ccw(c5773.37,7830.17) v1@5779.96,7823.58
  L12_Bottom Layer w10: v1(5779.96,7822.58) 5780.96,7821.58 5809.9,7821.58 ccw(c5809.89,7892.41) 5859.98,7842.33 6033.75,8016.09 cw(c6077.02,7972.81) 6077.04,8034.01 6120.02,8034.01 ccw(c6120.02,8044) 6127.09,8036.94 6132.23,8042.08 cw(c6139.3,8035.02) 6139.3,8045.01 6622.48,8045.01 ccw(c6622.48,8082.74) 6649.16,8056.06 J46.B16@6663.11,8070.01
ADC1_DB2_P: C102.2 J46.B17 | length 4363.2
  L1_Top Layer w10: C102.2@2507.75,7962.28 C102.2@2508.74,7961.28 ; C102.2@2508.74,7961.28 2508.75,7923.83 ccw(c2639.73,7923.83) 2639.73,7792.85 5776.61,7792.85 cw(c5776.61,7788.51) v1@5779.68,7791.58 ; v1@5779.68,7792.85 v1(5779.96,7792.58)
  L12_Bottom Layer w10: v1(5779.96,7792.58) 5780.96,7793.58 5809.9,7793.58 ccw(c5809.9,7892.42) 5879.79,7822.53 6053.55,7996.29 cw(c6077.02,7972.81) 6077.02,8006.01 ; 6077.03,8006.01 6120.02,8006.01 cw(c6120.02,7996.02) 6127.09,8003.08 6132.23,7997.94 ccw(c6139.3,8005) 6139.3,7995.01 6619.06,7995.01 ccw(c6619.06,8041) 6651.58,8008.48 J46.B17@6663.11,8020.01
ADC1_DB3+: C104.1 U8.M8 | length 65.6
  L1_Top Layer w10: U8.M8@2445.41,8051.87 2446.75,8050.53 2446.75,7988.26 C104.1@2445.75,7987.26
ADC1_DB3-: C105.1 U8.M9 | length 64.5
  L1_Top Layer w10: C105.1@2474.75,7988.26 2474.75,8049.71 U8.M9@2476.91,8051.87
ADC1_DB3_M: C105.2 J46.A18 | length 4609.2
  L1_Top Layer w10: C105.2@2475.75,7961.28 2474.75,7960.28 2474.75,7856.77 ccw(c2675.85,7856.77) 2675.85,7655.67 2720.69,7655.67 ccw(c2720.69,7675.64) 2734.81,7661.52 2739.81,7666.52 2744.24,7670.96 cw(c2759.74,7655.46) 2759.74,7677.38 2770.91,7677.38 cw(c2770.91,7658.67) 2784.14,7671.9 2789.51,7666.53 2794.55,7661.48 ccw(c2808.58,7675.51) 2808.58,7655.67 2828.21,7655.67 ccw(c2828.21,7675.64) 2842.33,7661.52 2847.33,7666.52 2851.76,7670.96 cw(c2867.26,7655.46) 2867.26,7677.38 2878.43,7677.38 cw(c2878.43,7658.67) 2891.66,7671.9 2897.03,7666.53 2902.07,7661.48 ccw(c2916.1,7675.51) 2916.1,7655.67 2928.17,7655.67 ccw(c2928.17,7675.64) 2942.29,7661.52 2947.29,7666.52 2951.72,7670.96 cw(c2967.22,7655.46) 2967.22,7677.38 2978.39,7677.38 cw(c2978.39,7658.67) 2991.62,7671.9 2996.99,7666.53 3002.03,7661.48 ccw(c3016.06,7675.51) 3016.06,7655.67 5634.73,7655.67
  L12_Bottom Layer w10: v1(5643.74,7658.4) 5644.74,7657.4 5724.33,7657.4 ccw(c5724.33,7852.38) 5862.19,7714.5 6064.69,7917.01 cw(c6105.74,7875.95) 6105.74,7934.01 6130.02,7934.01 ccw(c6130.02,7944) 6137.09,7936.94 6142.23,7942.08 cw(c6149.3,7935.02) 6149.3,7945.01 6672.48,7945.01 ccw(c6672.48,7982.74) 6699.16,7956.06 J46.A18@6713.11,7970.01
ADC1_DB3_P: C104.2 J46.A19 | length 4616.3
  L1_Top Layer w10: C104.2@2445.75,7961.28 2446.75,7960.28 2446.75,7856.77 ccw(c2675.85,7856.77) 2675.85,7627.67 v1@5641.81,7627.67
  L12_Bottom Layer w10: v1(5643.74,7628.4) 5644.74,7629.4 5724.33,7629.4 ccw(c5724.33,7852.38) 5882,7694.71 6084.49,7897.21 cw(c6105.74,7875.95) 6105.74,7906.01 6130.02,7906.01 cw(c6130.02,7896.02) 6137.09,7903.08 6142.23,7897.94 ccw(c6149.3,7905) 6149.3,7895.01 6669.06,7895.01 ccw(c6669.06,7941) 6701.58,7908.48 J46.A19@6713.11,7920.01
ADC1_DB4+: C106.1 U8.H11 | length 65.1
  L12_Bottom Layer w10: v1(2539.9,8177.85) 2541.65,8179.6 2602.91,8179.6 C106.1@2603.9,8178.61
ADC1_DB4-: C110.1 U8.G11 | length 65.1
  L12_Bottom Layer w10: v1(2539.9,8209.35) 2541.65,8207.6 2602.9,8207.6 C110.1@2603.9,8208.6
ADC1_DB4_M: C110.2 J46.Z12 | length 4261.4
  L10_Signal Layer 2 w6.3: v1(5877.5,8179.62) 5879.42,8177.7 6302.86,8177.7 cw(c6302.86,8111.32) 6349.78,8158.27 ccw(c6378.98,8187.44) 6378.96,8146.17 6418.51,8146.17 ccw(c6418.51,8184.8) 6445.83,8157.49 6505.46,8217.12 cw(c6603.86,8118.72) 6603.86,8257.88 6609.01,8257.88 ccw(c6609.01,8268.6) 6616.59,8261.02 6635,8279.43 cw(c6671.24,8243.2) 6671.24,8294.44 6746.74,8294.44 cw(c6746.74,8278.07) 6763.11,8278.07 v1(6763.11,8270.01)
  L12_Bottom Layer w10: C110.2@2629.88,8208.6 2631.11,8207.37 2727.5,8207.37 cw(c2727.49,8090.77) 2809.93,8173.22 ccw(c2972.65,8335.93) 2972.65,8105.82 4845.67,8105.82 ; 4845.68,8105.82 4887.67,8105.82 ; 4887.67,8105.82 5403.67,8105.82 5424.45,8105.82 ccw(c5424.45,8154.33) 5458.75,8120.03 ccw(c5416.88,8174.18) 5465.28,8125.78 5480.84,8141.34 cw(c5570.85,8051.33) 5570.85,8178.62 5876.5,8178.62 v1(5877.5,8179.62)
ADC1_DB4_P: C106.2 J46.Z13 | length 4262.5
  L10_Signal Layer 2 w6.3: v1(5877.5,8149.62) 5879.18,8151.3 6302.85,8151.3 cw(c6302.85,8111.32) 6331.12,8139.59 ccw(c6378.97,8187.44) 6378.97,8119.77 6418.51,8119.77 ccw(c6418.51,8184.81) 6464.5,8138.82 6524.13,8198.45 cw(c6603.87,8118.72) 6603.87,8231.48 6609.01,8231.48 cw(c6609.01,8219.94) 6617.17,8228.1 6639.06,8206.2 ccw(c6664.59,8231.74) 6664.59,8195.63 6745.03,8195.65 ccw(c6745.03,8213.73) 6763.11,8213.73 v1(6763.11,8220.01)
  L12_Bottom Layer w10: C106.2@2629.88,8178.61 2630.64,8179.37 2727.49,8179.37 cw(c2727.48,8090.77) 2790.13,8153.42 ccw(c2972.64,8335.93) 2972.64,8077.82 4887.67,8077.82 ; 4887.67,8077.82 5403.67,8077.82 5424.45,8077.82 ccw(c5424.45,8154.33) 5477.24,8098.95 ; 5478.55,8100.23 cw(c5424.45,8154.33) 5477.24,8098.95 ; v1(5877.5,8149.62) 5876.5,8150.62 5570.85,8150.62 ccw(c5570.85,8051.33) 5500.64,8121.54 5485.08,8105.98 cw(c5416.88,8174.18) 5477.24,8098.95
ADC1_DB5+: C111.1 U8.K11 | length 65.1
  L12_Bottom Layer w10: v1(2539.9,8114.86) 2541.65,8116.6 2602.91,8116.6 C111.1@2603.9,8115.61
ADC1_DB5-: C112.1 U8.J11 | length 65.1
  L12_Bottom Layer w10: v1(2539.9,8146.35) 2541.65,8144.6 2602.9,8144.6 C112.1@2603.9,8145.6
ADC1_DB5_M: C112.2 J46.Z16 | length 4295.2
  L10_Signal Layer 2 w6.3: v1(5516.96,8021.06) 5519.5,8021.06 5541.59,8043.15 cw(c5586.84,7997.9) 5586.83,8061.89 5638.45,8061.89 cw(c5638.48,7900.69) 5752.46,8014.68 ccw(c5887.41,8149.63) 5887.4,7958.78 6462.43,7958.78 ccw(c6462.43,8035.32) 6516.55,7981.2 6530.77,7995.42 cw(c6620.45,7905.73) 6620.45,8032.56 6625.27,8032.56 ccw(c6625.27,8048.57) 6636.59,8037.25 6636.7,8037.36 cw(c6655.17,8018.89) 6655.17,8045.01 6744.96,8045.01 ccw(c6744.96,8063.16) 6763.11,8063.16 v1(6763.11,8070.01)
  L12_Bottom Layer w10: C112.2@2629.88,8145.6 2630.88,8144.6 2652.49,8144.6 cw(c2652.49,8001.01) 2754.02,8102.55 2773.33,8083.24 2813.19,8043.37 2825.12,8031.44 ccw(c2982.5,8188.82) 2982.5,7966.25 4885.07,7966.25 ; 4885.07,7966.26 5422.75,7966.26 ccw(c5422.75,8066.26) 5493.46,7995.55 5515.54,8017.63 ccw(c5512.1,8021.06) v1(5516.96,8021.06)
ADC1_DB5_P: C111.2 J46.Z17 | length 4293.4
  L10_Signal Layer 2 w6.3: v1(5538.18,7999.84) 5538.18,8002.4 5560.26,8024.48 cw(c5586.84,7997.9) 5586.84,8035.49 5638.48,8035.49 cw(c5638.48,7900.69) 5733.79,7996.01 ccw(c5887.41,8149.63) 5887.39,7932.38 6462.43,7932.38 ccw(c6462.43,8035.32) 6535.22,7962.53 6549.44,7976.75 cw(c6620.45,7905.73) 6620.45,8006.16 6625.27,8006.16 cw(c6625.27,7991.36) 6635.74,8001.82 6640.3,7997.26 ccw(c6645.73,8002.69) 6645.73,7995.01 6740.88,7995.01 ccw(c6740.88,8017.24) 6763.11,8017.24 v1(6763.11,8020.01)
  L12_Bottom Layer w10: C111.2@2630.87,8116.6 2652.49,8116.6 cw(c2652.49,8001.01) 2734.22,8082.75 2753.53,8063.44 ; 2753.53,8063.43 2805.32,8011.64 ccw(c2982.5,8188.82) 2982.49,7938.25 4896.66,7938.25 5422.75,7938.26 ccw(c5422.75,8066.26) 5513.26,7975.75 5536.76,7999.25 cw(c5538.18,7997.83) v1(5538.18,7999.84)
ADC1_DB6+: C113.1 U8.L10 | length 65.1
  L12_Bottom Layer w10: v1(2508.4,8083.36) 2510.15,8081.62 2510.15,8020.35 C113.1@2509.16,8019.36
ADC1_DB6-: C114.1 U8.L11 | length 65.1
  L12_Bottom Layer w10: C114.1@2539.15,8019.36 2538.15,8020.36 2538.15,8081.61 v1(2539.9,8083.36)
ADC1_DB6_M: C114.2 J46.Y18 | length 4654.8
  L10_Signal Layer 2 w6.3: v1(5451.47,7737.01) 5454.01,7737.01 5485.04,7768.04 cw(c5552.57,7700.51) 5552.56,7796.01 5640.45,7796.01 cw(c5640.45,7719.77) 5694.36,7773.68 5735.02,7733.02 ccw(c5792.79,7790.79) 5792.79,7709.09 5880.37,7709.09 ; 5880.82,7709.09 5900.73,7709.09 ccw(c5900.6,7836.94) 5908.59,7709.34 5908.63,7709.38 5955.02,7709.38 ccw(c5955.02,7755.29) 5987.49,7722.83 6054.75,7790.09 cw(c6158.44,7686.39) 6158.46,7833.04 6472.07,7833.04 ccw(c6472.06,7911.05) 6527.22,7855.89 6575.47,7904.14 cw(c6644.11,7835.5) 6644.1,7932.57 6674.25,7932.57 ccw(c6674.25,7947.85) 6685.05,7937.04 ; 6686.71,7938.7 cw(c6701.94,7923.47) 6701.94,7945.01 6794.96,7945.01 ccw(c6794.96,7963.16) 6813.11,7963.16 v1(6813.11,7970.01)
  L12_Bottom Layer w10: C114.2@2538.16,7994.37 2537.16,7993.37 2537.16,7976.66 ccw(c2671.95,7976.66) 2671.95,7841.87 2798.71,7841.87 cw(c2798.71,7713.87) 2889.22,7804.38 2982.8,7710.8 ccw(c3035.17,7763.17) 3035.17,7689.11 3092,7689.11 ccw(c3092,7709.08) 3106.12,7694.96 3111.12,7699.96 3115.55,7704.4 cw(c3140.13,7679.81) 3140.13,7714.58 cw(c3140.14,7683.03) 3162.45,7705.34 3167.82,7699.97 3172.86,7694.92 ccw(c3186.89,7708.95) 3186.89,7689.11 3206.36,7689.11 ccw(c3206.36,7709.08) 3220.48,7694.96 3225.48,7699.96 3229.9,7704.39 cw(c3251,7683.3) 3250.99,7713.13 cw(c3251,7686.53) 3269.81,7705.34 3275.18,7699.97 3280.22,7694.92 ccw(c3294.25,7708.95) 3294.25,7689.11 3318.9,7689.11 ccw(c3318.9,7699.13) 3325.98,7692.04 3333.9,7699.96 3338.33,7704.4 cw(c3364.4,7678.33) 3364.4,7715.2 ; 3364.42,7715.2 cw(c3364.42,7681.52) 3388.23,7705.34 3393.6,7699.97 3398.64,7694.92 ccw(c3412.67,7708.95) 3412.67,7689.11 4885.07,7689.11 ; 4885.07,7689.11 4890.87,7689.11 4908.27,7689.11 5238.05,7689.11 5238.05,7689.27 ccw(c5238.05,7709.24) 5252.17,7695.12 5257.17,7700.12 5261.6,7704.56 cw(c5282.68,7683.48) 5282.68,7713.29 cw(c5282.69,7686.69) 5301.5,7705.5 5306.87,7700.13 5311.91,7695.08 ccw(c5325.94,7709.11) 5325.94,7689.27 ; 5324.09,7689.11 5324.24,7689.27 5325.94,7689.27 ; 5327.09,7689.11 5326.93,7689.27 ; v1(5451.47,7737.01) 5451.47,7733.53 5437.82,7719.88 cw(c5363.92,7793.78) 5363.92,7689.27 5326.93,7689.27 ; 5325.94,7689.27 5326.93,7689.27
ADC1_DB6_P: C113.2 J46.Y19 | length 4652.8
  L10_Signal Layer 2 w6.3: v1(5472.69,7715.79) 5472.69,7718.35 5503.71,7749.37 cw(c5552.57,7700.51) 5552.57,7769.61 5640.45,7769.61 cw(c5640.45,7719.77) 5675.69,7755.01 5716.35,7714.35 ccw(c5792.79,7790.8) 5792.79,7682.69 5810.15,7682.69 cw(c5810.15,7663.67) 5823.6,7677.12 5829.51,7671.21 ; 5829.53,7671.21 ccw(c5844.87,7687.11) 5844.85,7665.02 ccw(c5844.86,7694.57) 5865.76,7673.68 5870.49,7678.41 cw(c5880.82,7668.08) 5880.82,7682.69 5900.72,7682.69 ccw(c5900.75,7836.94) 5910.2,7682.98 5955.03,7682.98 ccw(c5955.03,7755.29) 6006.16,7704.16 6073.42,7771.42 cw(c6158.45,7686.39) 6158.45,7806.64 6189.14,7806.64 cw(c6189.14,7787.62) 6202.59,7801.07 6208.5,7795.16 6208.77,7794.9 ccw(c6224.4,7810.52) 6224.4,7788.42 6225.77,7788.42 ccw(c6225.77,7812.01) 6242.45,7795.33 6249.8,7802.68 cw(c6259.36,7793.12) 6259.36,7806.64 6472.06,7806.64 ccw(c6472.06,7911.05) 6545.89,7837.22 6594.14,7885.47 cw(c6644.11,7835.5) 6644.11,7906.17 6675.78,7906.17 cw(c6675.78,7887.53) 6688.96,7900.71 ccw(c6702.72,7914.47) 6702.72,7895.01 6791.29,7895.01 ccw(c6791.29,7916.83) 6813.11,7916.83 v1(6813.11,7920.01)
  L12_Bottom Layer w10: C113.2@2508.17,7994.37 C113.2@2509.16,7993.38 2509.16,7976.66 ccw(c2671.95,7976.66) 2671.95,7813.87 2798.71,7813.87 cw(c2798.71,7713.87) 2869.42,7784.58 2963,7691 ccw(c3035.17,7763.17) 3035.17,7661.11 4874.67,7661.11 ; 4874.68,7661.11 5362.96,7661.11 ; 5363.91,7661.27 ccw(c5363.92,7793.78) 5457.62,7700.08 5471.59,7714.05 v1@5472.69,7714.05
ADC1_DB7+: C115.1 U8.L8 | length 65.1
  L12_Bottom Layer w10: v1(2445.41,8083.36) 2447.16,8081.62 2447.16,8020.35 C115.1@2446.17,8019.36
ADC1_DB7-: C118.1 U8.L9 | length 65.1
  L12_Bottom Layer w10: C118.1@2476.16,8019.36 2475.16,8020.36 2475.16,8081.61 v1(2476.91,8083.36)
ADC1_DB7_M: C118.2 J46.Y22 | length 4730.5
  L10_Signal Layer 2 w6.3: v1(5710.46,7536.14) 5712.26,7534.34 5964.92,7534.34 ccw(c5964.92,7803.56) 6155.29,7613.2 6204.1,7662 cw(c6374.33,7491.77) 6374.32,7732.51 6722.02,7732.51 ccw(c6722.02,7749.55) 6734.07,7737.5 6736.55,7739.98 cw(c6748.7,7727.82) 6748.7,7745.01 6794.96,7745.01 ccw(c6794.96,7763.16) 6813.11,7763.16 v1(6813.11,7770.01)
  L12_Bottom Layer w10: C118.2@2476,7993.99 2475.77,7993.76 2475,7992.99 2475,7906.98 ccw(c2690.2,7906.98) 2690.2,7691.78 2738.8,7691.78 cw(c2738.8,7563.78) 2829.31,7654.29 2921.19,7562.41 ccw(c2991.9,7633.12) 2991.9,7533.12 3092,7533.12 ccw(c3092,7553.09) 3106.12,7538.97 3111.12,7543.97 3115.55,7548.41 cw(c3131.05,7532.91) 3131.05,7554.83 3142.22,7554.83 cw(c3142.22,7536.12) 3155.45,7549.35 3160.82,7543.98 3165.86,7538.93 ccw(c3179.89,7552.96) 3179.89,7533.12 3195.52,7533.12 ccw(c3195.52,7553.09) 3209.64,7538.97 3214.64,7543.97 3219.07,7548.41 cw(c3234.57,7532.91) 3234.57,7554.83 3245.74,7554.83 cw(c3245.74,7536.12) 3258.97,7549.35 3264.34,7543.98 3269.38,7538.93 ccw(c3283.41,7552.96) 3283.41,7533.12 3294.57,7533.12 ccw(c3294.57,7553.09) 3308.69,7538.97 3313.69,7543.97 3318.12,7548.41 cw(c3333.62,7532.91) 3333.62,7554.83 3344.79,7554.83 cw(c3344.79,7536.12) 3358.02,7549.35 3363.39,7543.98 3368.43,7538.93 ccw(c3382.46,7552.96) 3382.46,7533.12 4884.95,7533.12 4885.07,7533.24 5703.47,7533.24 ccw(c5703.47,7543.13) v1(5710.46,7536.14)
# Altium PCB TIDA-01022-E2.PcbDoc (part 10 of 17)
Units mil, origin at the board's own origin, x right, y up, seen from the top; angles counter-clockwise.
Board outline 6929.13 x 11614.17 mil, 12 copper layers (L1_Top Layer, L2_GND, L3_GND, L4_Signal Layer 1, L5_GND, L6_PWR, L7_GND/PWR, L8_PWR, L9_GND/PWR, L10_Signal Layer 2, L11_GND, L12_Bottom Layer), stack 64.6 mil thick; 1711 components, 1002 nets, 5985 pads, 3200 vias.

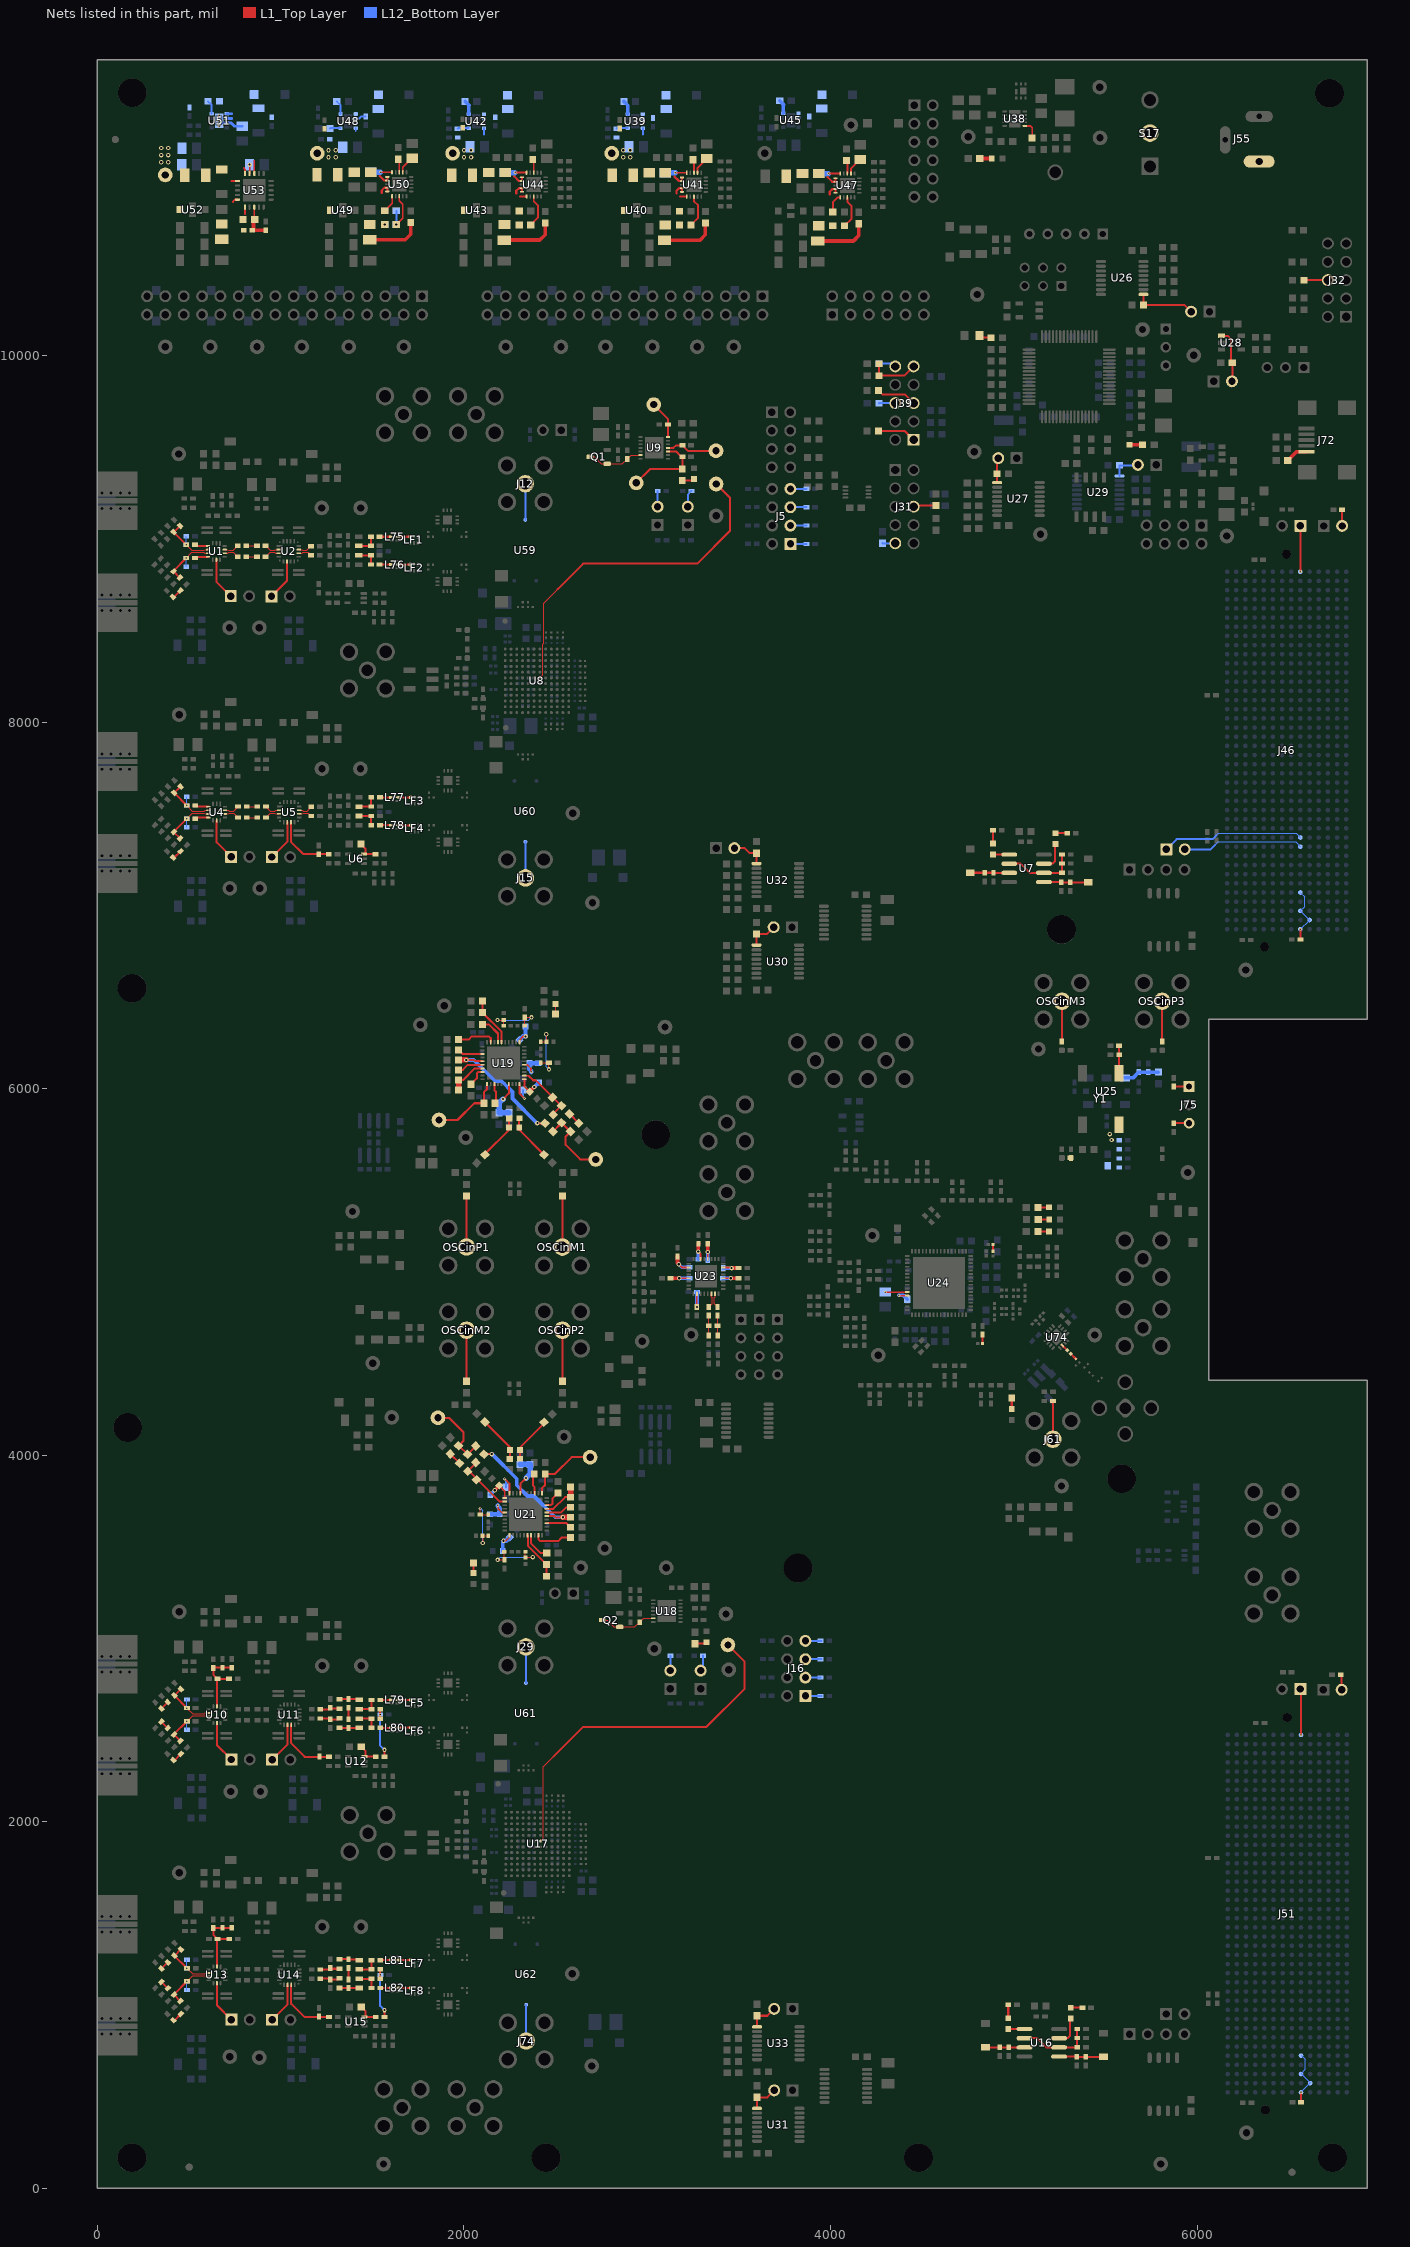
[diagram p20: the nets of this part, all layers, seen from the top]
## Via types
v1: diameter 16, hole 8, L1_Top Layer to L12_Bottom Layer, tented both sides, 1699 vias
v2: diameter 24, hole 12, L1_Top Layer to L12_Bottom Layer, tented both sides, 1501 vias

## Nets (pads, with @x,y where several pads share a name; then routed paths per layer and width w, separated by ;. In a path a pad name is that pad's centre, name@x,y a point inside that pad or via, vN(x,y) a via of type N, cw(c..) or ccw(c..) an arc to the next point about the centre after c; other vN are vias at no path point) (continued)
NetC60_2: C60.2 R46.1 U6.3 | length 129
  L1_Top Layer w11: C60.2@1437.39,7334.13 1461.99,7309.52 1461.99,7284.72 U6.3@1466.99,7279.72 ; U6.3@1455.18,7279.72 U6.3@1466.99,7279.72 ; R46.1@1517.27,7279.13 1516.68,7279.72 U6.3@1466.99,7279.72
NetC61_1: C61.1 R47.2 U5.7 | length 341.2
  L1_Top Layer w11: U5.7@1055.73,7454.01 1055.73,7347.87 1124.47,7279.13 C61.1@1208.47,7279.13 R47.2@1262.27,7279.13
NetC74_2: C74.2 D2.1 R51.2 U7.3 | length 211.9
  L1_Top Layer w11: D2.1@4763.11,7177.81 R51.2@4840.21,7177.81 C74.2@4889.21,7177.81 4889.83,7177.18 U7.3@4974.72,7177.18
NetC82_2: C82.2 R49.1 R60.2 U7.2 U7.6 | length 408
  L1_Top Layer w11: U7.2@4974.72,7227.18 5036.99,7227.18 5086.99,7177.18 U7.6@5163.7,7177.18 5261.59,7177.18 C82.2@5262.59,7178.18 R60.2@5262.59,7228.18 R49.1@5262.59,7277.18
NetC83_2: C83.2 D4.1 R62.2 U7.5 | length 243.1
  L1_Top Layer w11: U7.5@5163.7,7127.18 5257.83,7127.18 C83.2@5259.21,7125.81 R62.2@5308.21,7125.81 5406.12,7125.81 D4.1@5406.21,7125.72
NetC117_1: C117.1 Q1.1 Q1.3 U9.6 | length 311.5
  L1_Top Layer w6: Q1.3@2686.86,9446.65 2712.14,9446.65 2749.54,9409.25 Q1.1@2781.35,9409.25 2864.32,9409.25 C117.1@2890.1,9435.03 2911.29,9456.21 U9.6@2963.36,9456.21
NetC161_1: C161.1 R82.1 R83.1 R84.2 R568.2 U10.2 | length 385.5
  L1_Top Layer w8: C161.1@652.23,2776.51 C161.1@655.35,2779.63
  L1_Top Layer w11: U10.2@652.23,2629.9 C161.1@652.23,2776.51 ; R83.1@718.61,2779.63 C161.1@655.35,2779.63 632.23,2802.75 R84.2@632.23,2839.63 633.61,2841.01 R82.1@682.23,2841.01 733.02,2841.01 R568.2@733.23,2840.8
NetC170_1: C170.1 L9.1 R92.1 | length 109.5
  L1_Top Layer w11: R92.1@1216.03,2613.24 1261.13,2613.24 C170.1@1270.04,2622.15 1274.5,2617.69 L9.1@1320.04,2617.69
NetC171_1: C171.1 L9.2 L10.1 | length 111
  L1_Top Layer w11: L9.2@1320.04,2669.86 1369.58,2669.86 C171.1@1370.04,2669.39 1424.61,2669.39 L10.1@1429.04,2664.97
NetC171_2: C171.2 C176.2 | length 62.8
  L1_Top Layer w11: C176.2@1370.04,2559.39 C171.2@1370.04,2622.15
NetC172_1: C172.1 R88.1 R98.1 R103.2 | length 292.3
  L1_Top Layer w11: R98.1@1542.66,2562.77 R88.1@1542.66,2614.77 ; R103.2@1566.03,2354.9 v2(1566.03,2392.09)
  L12_Bottom Layer w11: C172.1@1542.52,2585.45 1542.52,2415.6 v2(1566.03,2392.09)
  other v1: 1542.52,2585.46
NetC173_2: C173.2 R101.2 | length 49.5
  L1_Top Layer w11: R101.2@348.93,2617.92 C173.2@383.93,2652.92
NetC174_2: C174.2 R102.2 | length 49.5
  L1_Top Layer w11: R102.2@348.93,2546.33 C174.2@383.93,2511.33
NetC175_1: C175.1 L11.1 R96.1 | length 107.9
  L1_Top Layer w11: R96.1@1216.03,2563.24 1266.19,2563.24 C175.1@1270.04,2559.39 1314.58,2559.39 L11.1@1320.04,2564.86
NetC176_1: C176.1 L11.2 L12.1 | length 109.4
  L1_Top Layer w11: L11.2@1320.04,2512.69 1369.5,2512.69 C176.1@1370.04,2512.15 1428.61,2512.15 L12.1@1429.04,2512.58
NetC186_2: C186.2 R103.1 U12.3 | length 129
  L1_Top Layer w11: C186.2@1438.9,2409.9 1463.51,2385.29 1463.51,2360.49 U12.3@1468.51,2355.49 ; U12.3@1456.7,2355.49 U12.3@1468.51,2355.49 ; R103.1@1518.79,2354.9 1518.2,2355.49 U12.3@1468.51,2355.49
NetC187_1: C187.1 R104.2 U11.7 | length 338.2
  L1_Top Layer w11: U11.7@1057.25,2529.78 1057.25,2428.68 1131.04,2354.9 R104.2@1263.79,2354.9
NetC195_1: C195.1 R106.1 R107.1 R108.2 R577.2 U13.2 | length 385.5
  L1_Top Layer w8: C195.1@652.3,1357.17 C195.1@655.42,1360.29
  L1_Top Layer w11: U13.2@652.3,1210.57 C195.1@652.3,1357.17 ; R107.1@718.68,1360.29 C195.1@655.42,1360.29 632.3,1383.41 R108.2@632.3,1420.29 633.68,1421.67 R106.1@682.3,1421.67 733.1,1421.67 R577.2@733.3,1421.47
NetC204_1: C204.1 L13.1 R116.1 | length 109.5
  L1_Top Layer w11: R116.1@1216.11,1193.91 1261.21,1193.91 C204.1@1270.11,1202.81 1274.57,1198.35 L13.1@1320.11,1198.35
NetC205_1: C205.1 L13.2 L14.1 | length 111
  L1_Top Layer w11: L13.2@1320.11,1250.52 1369.65,1250.52 C205.1@1370.11,1250.06 1424.69,1250.06 L14.1@1429.11,1245.63
NetC205_2: C205.2 C210.2 | length 62.8
  L1_Top Layer w11: C210.2@1370.11,1140.06 C205.2@1370.11,1202.81
NetC206_1: C206.1 R112.1 R122.1 R127.2 | length 292.3
  L1_Top Layer w11: R122.1@1542.74,1143.44 R112.1@1542.74,1195.44 ; R127.2@1566.11,935.56 v2(1566.11,972.75)
  L12_Bottom Layer w11: v1(1542.59,1166.13) 1542.59,996.26 v2(1566.11,972.75)
NetC207_2: C207.2 R125.2 | length 49.5
  L1_Top Layer w11: R125.2@349.01,1198.59 C207.2@384.01,1233.59
NetC208_2: C208.2 R126.2 | length 49.5
  L1_Top Layer w11: R126.2@349.01,1127 C208.2@384.01,1092
NetC209_1: C209.1 L15.1 R120.1 | length 107.9
  L1_Top Layer w11: R120.1@1216.11,1143.91 1266.27,1143.91 C209.1@1270.11,1140.06 1314.65,1140.06 L15.1@1320.11,1145.52
NetC210_1: C210.1 L15.2 L16.1 | length 109.4
  L1_Top Layer w11: L15.2@1320.11,1093.35 1369.57,1093.35 C210.1@1370.11,1092.81 1428.69,1092.81 L16.1@1429.11,1093.24
NetC220_2: C220.2 R127.1 U15.3 | length 129
  L1_Top Layer w11: C220.2@1438.98,990.56 1463.59,965.95 1463.59,941.15 U15.3@1468.59,936.15 ; U15.3@1456.78,936.15 U15.3@1468.59,936.15 ; R127.1@1518.86,935.56 1518.27,936.15 U15.3@1468.59,936.15
NetC221_1: C221.1 R128.2 U14.7 | length 339.4
  L1_Top Layer w11: U14.7@1057.33,1110.44 1057.33,1007.35 1129.11,935.56 R128.2@1263.86,935.56
NetC234_2: C234.2 D7.1 R132.2 U16.3 | length 213.2
  L1_Top Layer w11: D7.1@4845.28,770.78 4846.19,769.87 R132.2@4923.3,769.87 C234.2@4972.3,769.87 4972.92,769.25 U16.3@5057.81,769.25
NetC242_2: C242.2 R130.1 R141.2 U16.2 U16.6 | length 408
  L1_Top Layer w11: U16.2@5057.81,819.25 5127.31,819.25 5177.31,769.25 U16.6@5246.78,769.25 5344.67,769.25 C242.2@5345.67,770.25 R130.1@5345.67,869.25
NetC243_2: C243.2 D9.1 R143.2 U16.5 | length 243.1
  L1_Top Layer w11: U16.5@5246.78,719.25 5340.92,719.25 C243.2@5342.3,717.87 R143.2@5391.3,717.87 5489.21,717.87 D9.1@5489.3,717.79
NetC277_1: C277.1 Q2.1 Q2.3 U18.6 | length 311.5
  L1_Top Layer w6: Q2.3@2755.19,3100.88 2780.47,3100.88 2817.87,3063.48 Q2.1@2849.68,3063.48 2932.65,3063.48 C277.1@2958.43,3089.26 2979.62,3110.45 U18.6@3031.69,3110.45
NetC307_1: C307.1 R401.2 | length 40.5
  L1_Top Layer w11: C307.1@5310.19,4553.81 R401.2@5338.81,4525.19
NetC307_2: C307.2 U74.2 | length 38.2
  L1_Top Layer w11: U74.2@5264.65,4598.78 5291.24,4572.19 C307.2@5291.81,4572.19
NetC322_2: C322.2 L17.2 R164.2 R168.2 | length 339
  L1_Top Layer w6: v2(2182.77,6374.32) 2214.22,6374.32 2214.77,6373.77 L17.2@2216.07,6375.07 2216.36,6374.78 R164.2@2216.36,6343.87 ; R168.2@2331.19,6343.55 2331.07,6343.67 C322.2@2331.07,6388.15 2367.45,6388.15 v2(2368.07,6388.77)
  L12_Bottom Layer w6: v2(2182.77,6374.32) 2352.52,6374.32 2353.07,6373.77 v2(2368.07,6388.77)
NetC323_2: C323.2 R165.2 U19.7 | length 233.3
  L1_Top Layer w11: v2(2213.28,5942.92) 2244.39,5974.02 U19.7@2244.39,6025.64
  L12_Bottom Layer w30: C323.2@2191.16,5868.21 2191.16,5920.79 v2(2213.28,5942.92) ; C323.2@2191.25,5868.3 R165.2@2245.1,5868.3
NetC324_2: C324.2 R167.2 U19.11 | length 159.7
  L1_Top Layer w11: U19.11@2329.03,6051.23 2329.03,6013.34 C324.2@2365.07,5977.3
  L1_Top Layer w20: C324.2@2358.61,5983.87 v2(2383.73,6008.99)
  L12_Bottom Layer w20: v2(2383.73,6008.99) 2408.65,6033.92 R167.2@2408.72,6033.92
NetC326_1: C326.1 R170.2 U19.15 | length 169.1
  L1_Top Layer w9: U19.15@2329.03,6129.97 2345.56,6129.97 2365.25,6110.28 2365.25,6093.58 v1(2367.87,6090.96)
  L12_Bottom Layer w25: v1(2367.87,6090.96) 2367.87,6095.88 2357.12,6106.7 C326.1@2357.12,6138.82 2408.13,6138.82 R170.2@2408.8,6138.15
NetC327_2: C327.2 R169.2 U19.21 | length 146.8
  L1_Top Layer w10: U19.21@2303.44,6253.99 2303.44,6264.45 2323.8,6284.82 v2(2335.86,6284.82)
  L12_Bottom Layer w20: R169.2@2335.25,6338.72 2335.86,6338.11 v2(2335.86,6284.82)
  L12_Bottom Layer w25: C327.2@2302.55,6265.5 2321.86,6284.82 v2(2335.86,6284.82)
NetC332_2: C332.2 R171.1 U19.26 | length 266.7
  L1_Top Layer w11: R171.1@2101.43,6477.29 2100.78,6476.64 C332.2@2100.78,6414.92 2205.02,6310.68 U19.26@2205.02,6253.99
NetC333_2: C333.2 R173.1 U19.37 | length 211.9
  L1_Top Layer w11: C333.2@1970.15,6047.12 1995.57,6047.12 2058.74,6110.29 U19.37@2100.68,6110.29
  L1_Top Layer w30: R173.1@1970.15,5991.92 C333.2@1970.15,6047.12
NetC335_2: C335.2 R176.1 U19.35 | length 723.4
  L1_Top Layer w11: v2(2012.28,6156.42) 2053.52,6156.42 2060.28,6149.66 U19.35@2100.68,6149.66 ; v2@2401.02,5811.09 R176.1@2441.39,5811.09
  L1_Top Layer w30: C335.2@1970.15,6156.42 v2(2012.28,6156.42)
  L12_Bottom Layer w20: v2(2012.28,6156.42) 2053.85,6156.42 2170.26,6040.01 2205.72,6040.01 2264.21,5981.52 2264.21,5946.06 v2@2398.49,5811.78
  other v2: 2400.32,5811.78
NetC336_1: C336.1 R176.2 R177.2 Vtune_TP1.1 | length 391.6
  L1_Top Layer w11: R176.2@2485.93,5766.55 2531.93,5812.55 R177.2@2531.93,5813.45 2579.29,5766.09 C336.1@2581.39,5766.09 2554.28,5738.98 2554.28,5692.92 2633.38,5613.82 Vtune_TP1.1@2693.66,5613.82
NetC337_1: C337.1 C339.1 R177.1 U19.12 | length 327
  L1_Top Layer w8: U19.12@2329.03,6070.92 2351.7,6070.92 2354.66,6067.96
  L1_Top Layer w11: 2354.66,6067.96 2376.81,6045.81 2391.39,6045.81 C337.1@2524.28,5912.92 ; R177.1@2487.39,5862.09 C337.1@2531.39,5906.09
  L1_Top Layer w30: R177.1@2487.39,5857.99 R177.1@2487.39,5862.09
NetC337_2: C337.2 R179.1 | length 71.1
  L1_Top Layer w11: C337.2@2575.93,5861.55 R179.1@2626.01,5811.47
  L1_Top Layer w30: R179.1@2626.01,5811.19 R179.1@2626.01,5811.47
NetC338_2: C338.2 L18.2 R175.1 R180.2 | length 352
  L1_Top Layer w6: R175.1@2418.59,6141.6 2418.71,6141.72 C338.2@2463.19,6141.72 2463.19,6105.34 v2(2463.81,6104.72) ; R180.2@2418.91,6256.43 2449.82,6256.43 L18.2@2450.11,6256.72 2448.81,6258.02 v2(2448.81,6296.72)
  L12_Bottom Layer w6: v2(2448.81,6296.72) 2448.81,6119.72 v2(2463.81,6104.72)
NetC340_2: C340.2 U19.10 | length 138.8
  L1_Top Layer w11: U19.10@2303.44,6025.64 2303.44,5972.93 v1(2329.56,5946.82)
  L12_Bottom Layer w11: C340.2@2322,5992.83 2322,5954.37 v1(2329.56,5946.82)
NetC342_1: C342.1 U19.36 | length 142.1
  L1_Top Layer w11: C342.1@1970.15,6102.02 1993.38,6102.02 2021.34,6129.97 U19.36@2100.68,6129.97
NetC343_2: C343.2 U19.38 | length 105.8
  L1_Top Layer w11: C343.2@2038.16,6024.21 2069.86,6055.91 2069.86,6082.87 2077.59,6090.6 U19.38@2100.68,6090.6
NetC344_1: C344.1 U19.29 | length 208.8
  L1_Top Layer w11: C344.1@1970.15,6267.52 2024.82,6267.52 2042.83,6285.52 2130.44,6285.52 2130.55,6285.42 2135.78,6285.42 2145.96,6275.24 U19.29@2145.96,6253.99
NetC345_1: C345.1 U19.3 | length 116.7
  L1_Top Layer w11: C345.1@2165.65,5923.33 C345.1@2168.66,5920.31 2175.78,5927.43 2175.78,5981.75 2165.65,5991.88 U19.3@2165.65,6025.64
NetC346_2: C346.2 U19.27 | length 152.5
  L1_Top Layer w11: C346.2@2100.37,6350.82 2135.38,6350.82 2185.33,6300.87 U19.27@2185.33,6253.99
NetC347_2: C347.2 U19.33 | length 139.7
  L1_Top Layer w11: C347.2@1970.15,6211.12 1992.24,6189.03 U19.33@2100.68,6189.03
NetC348_1: C348.1 R192.2 R196.2 | length 252.3
  L1_Top Layer w11: R192.2@2111.13,5640.53 2111.91,5641.31 2246.86,5776.26 2246.86,5788.82 C348.1@2246.86,5836.66
NetC349_1: C349.1 R196.1 R199.1 | length 251.9
  L1_Top Layer w11: C349.1@2302.04,5838.36 2300.54,5836.86 2300.54,5775.26 R199.1@2433.59,5642.21
NetC352_2: C352.2 L19.2 R205.2 R209.2 | length 352
  L1_Top Layer w6: v2(2183.55,3429.2) 2184.17,3429.82 C352.2@2220.55,3429.82 2220.55,3474.3 R209.2@2220.43,3474.42 ; R205.2@2335.26,3474.1 2335.26,3443.19 L19.2@2335.55,3442.9 2336.85,3444.2 v2(2375.55,3444.2)
  L12_Bottom Layer w6: v2(2183.55,3429.2) 2198.55,3444.2 v2(2375.55,3444.2)
NetC353_2: C353.2 R206.2 U21.7 | length 233.3
  L1_Top Layer w11: U21.7@2307.23,3792.33 2307.23,3843.95 v2(2338.34,3875.06)
  L12_Bottom Layer w30: R206.2@2306.51,3949.67 C353.2@2360.37,3949.67 ; v2(2338.34,3875.06) 2360.46,3897.18 C353.2@2360.46,3949.76
NetC354_2: C354.2 R208.2 U21.11 | length 159.7
  L1_Top Layer w10: C354.2@2186.55,3840.67 2222.59,3804.63 U21.11@2222.59,3766.74
  L1_Top Layer w20: v2(2167.89,3808.98) C354.2@2193.01,3834.11
  L12_Bottom Layer w20: R208.2@2142.89,3784.06 2142.96,3784.06 v2(2167.89,3808.98)
NetC355_1: C355.1 C494.1 L87.1 U39.1 U39.2
NetC356_1: C356.1 R211.2 U21.15 | length 167.3
  L1_Top Layer w9: v1(2184.09,3726.67) 2186.71,3724.04 2186.71,3707.35 2206.41,3687.65 U21.15@2222.93,3687.65
  L12_Bottom Layer w25: R211.2@2142.48,3677.57 C356.1@2193.49,3677.57 ; v1@2183.34,3723.16 v1@2183.74,3723.56 ; v1@2183.71,3722.06 2194.5,3711.27 C356.1@2194.5,3679.16 ; v1@2183.74,3722.09 v1@2183.74,3723.56 ; v1@2183.74,3725.59 v1@2183.74,3723.56
NetC357_2: C357.2 R210.2 U21.21 | length 145.9
  L1_Top Layer w10: v2(2215.76,3533.16) 2227.81,3533.16 2248.18,3553.52 U21.21@2248.18,3563.98
  L12_Bottom Layer w20: R210.2@2211.44,3477.61 v2@2211.44,3530.91
  L12_Bottom Layer w25: v2(2215.76,3533.16) 2229.76,3533.16 C357.2@2249.07,3552.47
NetC362_2: C362.2 R212.1 U21.26 | length 267.2
  L1_Top Layer w11: U21.26@2346.6,3563.98 2348.39,3562.19 2348.39,3505.51 C362.2@2450.84,3403.06 2450.9,3403 R212.1@2450.9,3339.98
NetC363_2: C363.2 R214.1 U21.37 | length 211.9
  L1_Top Layer w11: U21.37@2450.93,3707.69 2488.1,3707.69 2551.27,3770.86 C363.2@2581.46,3770.86
  L1_Top Layer w30: C363.2@2581.46,3770.86 R214.1@2581.46,3826.06
NetC364_1: C364.1 C537.1 L88.1 U42.1 U42.2
NetC365_2: C365.2 R218.1 U21.35 | length 723.4
  L1_Top Layer w11: R218.1@2110.23,4006.89 v2@2150.6,4006.89 ; U21.35@2450.93,3668.32 2491.34,3668.32 2498.09,3661.56 v2(2539.34,3661.56)
  L1_Top Layer w30: v2(2539.34,3661.56) C365.2@2581.46,3661.56
  L12_Bottom Layer w20: v2@2153.13,4006.19 2287.41,3871.91 2287.41,3836.45 2345.89,3777.97 2381.35,3777.97 2497.76,3661.56 v2(2539.34,3661.56)
  other v2: 2151.29,4006.19
NetC366_1: C366.1 R217.2 R218.2 Vtune_TP2.1 | length 391.6
  L1_Top Layer w11: Vtune_TP2.1@1857.96,4204.16 1918.24,4204.16 1997.34,4125.06 1997.34,4078.99 C366.1@1970.23,4051.89 1972.33,4051.89 2019.69,4004.53 R217.2@2019.69,4005.43 R218.2@2064.32,4050.07 R218.2@2065.69,4051.43
NetC367_1: C367.1 C369.1 R217.1 U21.12 | length 327
  L1_Top Layer w10: 2194.8,3747.06 U21.12@2222.59,3747.06
  L1_Top Layer w11: C367.1@2020.23,3911.89 R217.1@2064.23,3955.89 ; C367.1@2027.34,3905.06 2036.8,3905.06 2194.8,3747.06
  L1_Top Layer w30: R217.1@2064.23,3955.89 R217.1@2064.23,3959.99
NetC367_2: C367.2 R220.1 | length 71.1
  L1_Top Layer w11: R220.1@1925.61,4006.51 C367.2@1975.69,3956.43
  L1_Top Layer w30: R220.1@1925.61,4006.51 R220.1@1925.61,4006.79
NetC368_2: C368.2 L20.2 R216.1 R221.2 | length 352.4
  L1_Top Layer w6: v1(2088,3710) 2088,3712.21 2088.43,3712.64 C368.2@2088.43,3676.26 2132.91,3676.26 R216.1@2133.02,3676.38 ; v2(2102.8,3521.26) 2102.8,3559.96 2101.5,3561.26 L20.2@2101.79,3561.55 R221.2@2132.7,3561.55
  L12_Bottom Layer w6: v1(2088,3710) 2091.06,3710 2102.8,3698.26 v2(2102.8,3521.26)
NetC370_2: C370.2 U21.10 | length 138.8
  L1_Top Layer w10: v1(2222.06,3871.16) 2248.18,3845.04 U21.10@2248.18,3792.33
  L12_Bottom Layer w11: v1(2222.06,3871.16) 2229.61,3863.6 C370.2@2229.61,3825.15
NetC371_1: C371.1 C600.1 L89.1 U45.1 U45.2
NetC372_1: C372.1 U21.36 | length 142.1
  L1_Top Layer w11: U21.36@2450.93,3688 2530.28,3688 2558.24,3715.96 C372.1@2581.46,3715.96
NetC373_2: C373.2 U21.38 | length 105.8
  L1_Top Layer w11: U21.38@2450.93,3727.37 2474.03,3727.37 2481.76,3735.1 2481.76,3762.06 C373.2@2513.46,3793.76
NetC374_1: C374.1 U21.29 | length 209.5
  L1_Top Layer w11: U21.29@2405.66,3563.98 2405.66,3542.74 2416.86,3531.53 2513.13,3531.53 2532.06,3550.46 C374.1@2581.46,3550.46
NetC375_1: C375.1 U21.3 | length 116.7
  L1_Top Layer w11: U21.3@2385.97,3792.33 2385.97,3826.09 2375.84,3836.22 2375.84,3890.54 C375.1@2382.96,3897.66 C375.1@2385.97,3894.65
NetC376_2: C376.2 U21.27 | length 152.5
  L1_Top Layer w11: U21.27@2366.29,3563.98 2366.29,3517.11 2416.24,3467.16 C376.2@2451.25,3467.16
NetC377_2: C377.2 U21.33 | length 139.7
  L1_Top Layer w11: U21.33@2450.93,3628.95 2559.37,3628.95 C377.2@2581.46,3606.86
NetC378_1: C378.1 R233.2 R237.2 | length 252.3
  L1_Top Layer w11: C378.1@2304.76,3981.32 2304.76,4041.72 R233.2@2440.49,4177.45
NetC379_1: C379.1 R237.1 R242.1 | length 251.9
  L1_Top Layer w11: R242.1@2118.03,4175.77 2251.08,4042.72 2251.08,4029.16 2251.08,3981.12 C379.1@2249.58,3979.62
NetC384_1: C384.1 R245.1 U23.2 | length 171.9
  L1_Top Layer w10: v2(3172,5042) 3189.01,5024.99 U23.2@3225.8,5024.99
  L1_Top Layer w20: R245.1@3164.5,5084.17 3164.5,5049.5 v2(3172,5042)
  L12_Bottom Layer w20: v2(3172,5042) 3188.71,5025.29 C384.1@3230.88,5025.29
NetC385_2: C385.2 R251.1 U23.10 | length 154
  L1_Top Layer w8: v2(3270.5,4808.91) U23.10@3270.5,4880.71
  L12_Bottom Layer w20: v2(3270.5,4808.91) 3271.5,4809.91 C385.2@3271.5,4890.67
NetC386_1: C386.1 R246.1 U23.5 | length 155
  L1_Top Layer w10: v2(3174,4966) 3174.07,4965.93 U23.5@3225.8,4965.93
  L1_Top Layer w20: R246.1@3127.12,4965.79 3173.79,4965.79 v2(3174,4966)
  L12_Bottom Layer w20: v2(3174,4966) 3174.71,4965.29 C386.1@3229.88,4965.29
NetC387_2: C387.2 R250.1 U23.28 | length 129
  L1_Top Layer w10: v2(3330,5109) 3330.13,5108.87 U23.28@3330.13,5070.26
  L1_Top Layer w20: v2(3330,5109) 3330,5153.17 R250.1@3330.5,5153.67
  L12_Bottom Layer w20: v2(3330,5109) 3330.5,5108.5 C387.2@3330.5,5063.91
NetC388_1: C388.1 R247.1 U23.20 | length 128.4
  L1_Top Layer w10: U23.20@3414.78,4965.93 3455.93,4965.93 v2(3455.87,4966)
  L1_Top Layer w20: v2(3455.87,4966) 3497.59,4966 R247.1@3497.88,4966.29
  L12_Bottom Layer w20: C388.1@3411.12,4965.29 3455.15,4965.29 v2(3455.87,4966)
NetC389_1: C389.1 R248.1 U23.23 | length 130.1
  L1_Top Layer w10: U23.23@3414.78,5024.99 3456.01,5024.99 v2(3460,5021)
  L1_Top Layer w20: v2(3460,5021) 3460.29,5021.29 R248.1@3497.88,5021.29
  L12_Bottom Layer w20: C389.1@3414.78,5021.05 3414.83,5021 v2(3460,5021)
NetC390_1: C390.1 R249.1 U23.30 | length 130.1
  L1_Top Layer w10: v2(3278,5111) 3290.76,5098.24 U23.30@3290.76,5070.26
  L1_Top Layer w20: v2(3278,5111) 3278,5151.67 R249.1@3279.5,5153.17
  L12_Bottom Layer w20: v2(3278,5111) 3278.12,5110.88 C390.1@3278.12,5069.79
NetC391_1: C391.1 R263.2 R267.2 | length 109.1
  L1_Top Layer w6: R263.2@3335.5,4652.91 3335.5,4706.91 R267.2@3335.88,4707.29 3335.88,4761.29 C391.1@3335.5,4761.67
NetC391_2: C391.2 U23.14 | length 81.9
  L1_Top Layer w6: C391.2@3335.5,4808.91 3354.16,4827.57 3354.16,4859.13 3349.81,4863.48 U23.14@3349.81,4881.29
NetC392_1: C392.1 R267.1 R270.2 | length 109.5
  L1_Top Layer w6: C392.1@3383.5,4761.67 3383.12,4761.29 R267.1@3383.12,4707.29 3384.5,4705.91 R270.2@3384.5,4652.91
NetC392_2: C392.2 U23.15 | length 81.8
  L1_Top Layer w6: U23.15@3369.5,4881.29 3369.5,4863.48 3365.16,4859.13 3365.16,4827.25 C392.2@3383.5,4808.91
NetC393_2: C393.2 R275.2 | length 38
  L1_Top Layer w11: C393.2@4886.47,5112.93 R275.2@4886.46,5150.94
NetC398_1: C398.1 R284.2 | length 48.4
  L1_Top Layer w11: R284.2@4828.96,4610.02 C398.1@4828.97,4658.39
NetC410_1: C410.1 R344.1
NetC411_2: C411.2 C412.2 L56.2 U25.6@5605.97,6058.67 | length 195.9
  L12_Bottom Layer w20: U25.6@5605.97,6058.67 5649.47,6058.67 C412.2@5680.97,6090.22 ; C412.2@5680.97,6090.22 C411.2@5733.97,6090.22 ; C411.2@5734.27,6089.92 C411.2@5733.97,6090.22 ; L56.2@5788.35,6090.22 C411.2@5733.97,6090.22
NetC414_2: C414.2 C416.2 C418.2 C419.2 L21.1 Y1.4
  other v2: 5533,5720 5523,5752
NetC417_2: C417.2 R359.1 Y1.1 | length 150.6
  L1_Top Layer w11: Y1.1@5574.02,6083.56 5574.02,6184.83 C417.2@5574.28,6185.09 5574.28,6233.79 R359.1@5574.12,6233.95
NetC431_1: C431.1 U24.12 | length 103.3
  L1_Top Layer w8: v1(4372.72,4871.96) 4371.78,4871.96 4371,4871.19 4371.47,4870.72 4371.58,4870.83 U24.12@4418.03,4870.83
  L12_Bottom Layer w20: v1(4372.72,4871.96) 4397.21,4871.96 C431.1@4418.03,4851.14
NetC432_1: C432.1 U24.11 | length 118.6
  L1_Top Layer w8: v1@4299.47,4890.51 U24.11@4418.03,4890.51
  other v1: 4298.97,4890.02
NetC481_1: C481.1 U38.1 | length 99.7
  L1_Top Layer w10: U38.1@5059.82,11252.43 5088.89,11252.43 5099.82,11241.51 C481.1@5099.82,11186.3
NetC490_1: C490.1 R5.1 R6.1 R8.2 R553.1 U1.5 | length 326.6
  L1_Top Layer w6: R8.2@416.29,9035.99 R8.2@417.52,9035.99 ; v1(485.29,8966.99) 515.79,8936.49 581.48,8936.49 585.82,8940.83 U1.5@603.64,8940.83
  L1_Top Layer w11: R8.2@416.29,9035.99 v1(485.29,8966.99) ; R8.2@417.52,9035.99 C490.1@451.61,9070.08
  L12_Bottom Layer w6: v1(485.29,8966.99) R553.1@485.29,9013.79
NetC491_2: C491.2 R12.2 R16.1 R19.2 R554.1 U1.6 | length 326.9
  L1_Top Layer w6: R12.2@415.61,8821.49 R12.2@415.61,8822.69 ; v1(485.29,8895.01) 515.77,8925.49 581.48,8925.49 585.82,8921.15 U1.6@603.64,8921.15
  L1_Top Layer w11: R12.2@415.61,8821.49 C491.2@449.61,8787.49 ; R12.2@416.29,8826.01 v1(485.29,8895.01)
  L12_Bottom Layer w6: R554.1@485.29,8847.79 v1(485.29,8895.01)
NetC492_2: C492.2 R555.2 | length 55.1
  L1_Top Layer w11: C492.2@411.61,8683.08 418.21,8683.08 R555.2@452.5,8717.38
NetC493_1: C493.1 R29.1 R30.1 R32.2 R562.1 U4.5 | length 326.6
  L1_Top Layer w6: R32.2@418.09,7613.86 R32.2@419.32,7613.86 ; v1(487.09,7544.86) 517.59,7514.36 583.28,7514.36 587.62,7518.71 U4.5@605.43,7518.71
  L1_Top Layer w11: R32.2@418.09,7613.86 v1(487.09,7544.86) ; R32.2@419.32,7613.86 C493.1@453.41,7647.95
  L12_Bottom Layer w6: v1(487.09,7544.86) R562.1@487.09,7591.66
NetC495_1: C495.1 R489.2 R490.2 R491.2 R613.2 TP21.1 U39.4 U39.5 U40.1 | length 96.3
  L12_Bottom Layer w10: R490.2@2832.28,11237.33 2835.23,11240.27 U39.5@2893.32,11240.27 ; 2976,11206.25 U39.4@2976,11240.27
  other v2: 2868.42,11081 2907.42,11081 2868.42,11120 2907.42,11120
NetC499_2: C499.2 R36.2 R40.1 R43.2 R563.1 U4.6 | length 326.9
  L1_Top Layer w6: R36.2@417.41,7399.36 R36.2@417.41,7400.57 ; v1(487.09,7472.88) 517.57,7503.36 583.28,7503.36 587.62,7499.02 U4.6@605.43,7499.02
  L1_Top Layer w11: R36.2@417.41,7399.36 C499.2@451.41,7365.36 ; R36.2@418.09,7403.88 v1(487.09,7472.88)
  L12_Bottom Layer w6: R563.1@487.09,7425.66 v1(487.09,7472.88)
NetC500_2: C500.2 R564.2 | length 55.1
  L1_Top Layer w11: C500.2@413.41,7260.95 420.01,7260.95 R564.2@454.3,7295.25
NetC501_2: C501.2 U39.8 | length 77.2
  L12_Bottom Layer w20: C501.2@2873.16,11385.33 2893.99,11364.51 2893.32,11363.84 U39.8@2893.32,11317.05
NetC502_1: C502.1 R86.1 R87.1 R89.2 R571.1 U10.5 | length 326.6
  L1_Top Layer w6: R89.2@419.61,2689.63 R89.2@420.84,2689.63 ; v1(488.61,2620.63) 519.11,2590.13 584.8,2590.13 589.14,2594.47 U10.5@606.95,2594.47
  L1_Top Layer w11: R89.2@419.61,2689.63 v1(488.61,2620.63) ; R89.2@420.84,2689.63 C502.1@454.93,2723.72
  L12_Bottom Layer w6: v1(488.61,2620.63) R571.1@488.61,2667.42
NetC503_2: C503.2 R93.2 R97.1 R100.2 R572.1 U10.6 | length 326.9
  L1_Top Layer w6: R93.2@418.93,2475.13 R93.2@418.93,2476.33 ; v1(488.61,2548.64) 519.09,2579.13 584.8,2579.13 589.14,2574.79 U10.6@606.95,2574.79
  L1_Top Layer w11: R93.2@418.93,2475.13 C503.2@452.93,2441.13 ; R93.2@419.61,2479.64 v1(488.61,2548.64)
  L12_Bottom Layer w6: R572.1@488.61,2501.42 v1(488.61,2548.64)
NetC504_2: C504.2 R573.2 | length 55.1
  L1_Top Layer w11: C504.2@414.93,2336.72 421.52,2336.72 R573.2@455.82,2371.02
NetC505_1: C505.1 R110.1 R111.1 R113.2 R580.1 U13.5 | length 326.6
  L1_Top Layer w6: R113.2@419.68,1270.29 R113.2@420.91,1270.29 ; v1(488.68,1201.29) 519.18,1170.79 584.87,1170.79 589.22,1175.14 U13.5@607.03,1175.14
  L1_Top Layer w11: R113.2@419.68,1270.29 v1(488.68,1201.29) ; R113.2@420.91,1270.29 C505.1@455.01,1304.38
  L12_Bottom Layer w6: v1(488.68,1201.29) R580.1@488.68,1248.09
NetC506_2: C506.2 R117.2 R121.1 R124.2 R581.1 U13.6 | length 326.9
  L1_Top Layer w6: R117.2@419.01,1055.79 R117.2@419.01,1057 ; v1(488.68,1129.31) 519.16,1159.79 584.87,1159.79 589.22,1155.45 U13.6@607.03,1155.45
  L1_Top Layer w11: R117.2@419.01,1055.79 C506.2@453.01,1021.79 ; R117.2@419.68,1060.31 v1(488.68,1129.31)
  L12_Bottom Layer w6: R581.1@488.68,1082.09 v1(488.68,1129.31)
NetC507_2: C507.2 R582.2 | length 55.1
  L1_Top Layer w11: C507.2@415.01,917.38 421.6,917.38 R582.2@455.9,951.68
NetC509_1: C509.1 C643.1 L90.1 U48.1 U48.2 | length 59.8
  L12_Bottom Layer w11: U48.2@1409.21,11291.62 1427.07,11291.62 1439.7,11304.25 C509.1@1463.76,11304.25
NetC510_1: C510.1 C690.1 L91.2 U51.1 U51.2 | length 54.6
  L12_Bottom Layer w15: U51.2@705.89,11293.44 733.38,11293.44 ; U51.1@705.89,11319.03 732.98,11319.03
NetC516_1: C516.1 C517.1 C518.1 R613.1 U41.15 U41.16 U41.17 | length 190
  L1_Top Layer w10: v1(3152.42,10997.6) 3153.42,10996.6 U41.15@3215.18,10996.6 ; U41.17@3189.59,10951.32 U41.16@3189.59,10971.01
  L1_Top Layer w12: 3147.7,10976.28 3172.65,10951.32 U41.17@3189.59,10951.32
  L12_Bottom Layer w20: v1@3151.5,10996.68 v1(3152.42,10997.6)
  L12_Bottom Layer w30: C517.1@3097.92,10996.68 v1@3151.5,10996.68
NetC519_1: C519.1 C522.1 R493.1 R494.2 R614.1 U41.1 U41.19 U41.20 | length 407.4
  L1_Top Layer w10: 3178.1,10866.68 U41.1@3215.18,10866.68 ; U41.20@3189.59,10892.27 U41.19@3189.59,10911.95
  L1_Top Layer w12: 3158.7,10883.28 3158.7,10897.28 3173.38,10911.95 U41.19@3189.59,10911.95
  L1_Top Layer w20: R614.1@3093.51,10628.72 3287.6,10628.72 3316.92,10658.05 R493.1@3316.92,10722.18
NetC522_2: C522.2 U41.3 | length 180.6
  L1_Top Layer w10: C522.2@3238.42,10711.68 3277.42,10750.68 3277.42,10818.6 3254.55,10841.47 U41.3@3254.55,10866.68
NetC523_1: C523.1 U41.12 | length 98.1
  L1_Top Layer w10: U41.12@3274.24,10996.6 3274.24,11022.99 C523.1@3324.92,11073.68
NetC524_1: C524.1 U41.13 | length 73.9
  L1_Top Layer w10: C524.1@3248.92,11068.18 3254.55,11062.55 U41.13@3254.55,10996.6
NetC538_1: C538.1 R501.2 R502.1 R503.2 R617.2 TP25.1 U42.4 U42.5 U43.1 | length 96.3
  L12_Bottom Layer w10: R501.2@1965.28,11237.28 1968.23,11240.23 U42.5@2026.32,11240.23 ; 2109,11206.2 U42.4@2109,11240.23
  other v2: 2000,11081 2039,11081 2000,11120 2039,11120
NetC544_2: C544.2 U42.8 | length 77.2
  L12_Bottom Layer w20: C544.2@2006.17,11385.28 2026.99,11364.46 2026.32,11363.8 U42.8@2026.32,11317
NetC587_1: C587.1 C588.1 C589.1 R617.1 U44.15 U44.16 U44.17 | length 190
  L1_Top Layer w10: v1(2278.59,10998.46) 2279.59,10997.46 U44.15@2341.35,10997.46 ; U44.17@2315.76,10952.18 U44.16@2315.76,10971.87
  L1_Top Layer w12: 2273.87,10977.13 2298.83,10952.18 U44.17@2315.76,10952.18
  L12_Bottom Layer w20: v1@2277.67,10997.54 v1(2278.59,10998.46)
  L12_Bottom Layer w30: C588.1@2224.09,10997.54 v1@2277.67,10997.54
NetC590_1: C590.1 C593.1 R505.1 R506.2 R618.1 U44.1 U44.19 U44.20 | length 407.5
  L1_Top Layer w10: 2304.18,10867.54 U44.1@2341.35,10867.54 ; U44.20@2315.76,10893.13 U44.19@2315.76,10912.81
  L1_Top Layer w12: 2284.87,10884.13 2284.87,10898.13 2299.55,10912.81 U44.19@2315.76,10912.81
  L1_Top Layer w20: R618.1@2219.69,10629.58 2413.77,10629.58 2443.09,10658.91 R505.1@2443.09,10723.04
NetC593_2: C593.2 U44.3 | length 180.6
  L1_Top Layer w10: C593.2@2364.59,10712.54 2403.59,10751.54 2403.59,10819.46 2380.72,10842.33 U44.3@2380.72,10867.54
NetC595_1: C595.1 U44.13 | length 73.9
  L1_Top Layer w10: C595.1@2375.09,11069.04 2380.72,11063.41 U44.13@2380.72,10997.46
NetC608_2: C608.2 U45.8 | length 77.2
  L12_Bottom Layer w20: C608.2@3722.17,11389.46 3742.99,11368.64 3742.33,11367.97 U45.8@3742.33,11321.18
NetC613_1: C613.1 C614.1 C615.1 R621.1 U47.15 U47.16 U47.17 | length 190
  L1_Top Layer w10: v1(3989.4,10993.59) 3990.4,10992.59 U47.15@4052.15,10992.59 ; U47.17@4026.56,10947.32 U47.16@4026.56,10967
  L1_Top Layer w12: 3984.67,10972.27 4009.63,10947.32 U47.17@4026.56,10947.32
  L12_Bottom Layer w20: v1@3988.47,10992.67 v1(3989.4,10993.59)
  L12_Bottom Layer w30: C615.1@3934.9,10992.67 v1@3988.47,10992.67
NetC616_1: C616.1 C619.1 R517.1 R518.2 R622.1 U47.1 U47.19 U47.20 | length 474.4
  L1_Top Layer w10: R518.2@4012.4,10782.67 4012.4,10835.86 4039.21,10862.67 U47.1@4052.15,10862.67 ; U47.20@4026.56,10888.26 U47.19@4026.56,10907.95
  L1_Top Layer w12: 3995.67,10879.27 3995.67,10893.27 4010.35,10907.95 U47.19@4026.56,10907.95
  L1_Top Layer w20: R622.1@3930.49,10624.72 4124.57,10624.72 4153.9,10654.04 R517.1@4153.9,10718.17
NetC619_2: C619.2 U47.3 | length 180.6
  L1_Top Layer w10: C619.2@4075.39,10707.67 4114.4,10746.67 4114.4,10814.59 4091.53,10837.46 U47.3@4091.53,10862.67
NetC620_1: C620.1 U47.12 | length 98.1
  L1_Top Layer w10: U47.12@4111.21,10992.59 4111.21,11018.99 C620.1@4161.9,11069.67
NetC621_1: C621.1 U47.13 | length 73.9
  L1_Top Layer w10: C621.1@4085.9,11064.17 4091.53,11058.54 U47.13@4091.53,10992.59
NetC647_1: C647.1 R525.2 R526.2 R527.2 R625.2 TP42.1 U48.4 U48.5 U49.1 | length 76.5
  L12_Bottom Layer w10: R526.2@1268.37,11237.5 1271.31,11240.44 U48.5@1326.53,11240.44 ; 1409.21,11223.36 U48.4@1409.21,11240.44
  other v2: 1261,11081 1300,11081 1261,11120 1300,11120
NetC654_2: C654.2 U48.8 | length 76.6
  L12_Bottom Layer w10: C654.2@1306.37,11385.5 1326.53,11365.34 U48.8@1326.53,11317.21
NetC655_1: C655.1 C656.1 C657.1 R625.1 U50.15 U50.16 U50.17 | length 190
  L1_Top Layer w10: v1(1544.72,11000.32) 1545.72,10999.32 U50.15@1607.48,10999.32 ; U50.17@1581.89,10954.05 U50.16@1581.89,10973.73
  L1_Top Layer w12: 1540,10979 1564.95,10954.05 U50.17@1581.89,10954.05
  L12_Bottom Layer w20: v1@1543.8,10999.4 v1(1544.72,11000.32)
  L12_Bottom Layer w30: C657.1@1490.22,10999.4 v1@1543.8,10999.4
NetC660_1: C660.1 C667.1 R529.1 R530.2 R531.2 R626.1 U50.1 U50.19 U50.20 | length 468.2
  L1_Top Layer w8: C667.1@1566.72,10713.4 v2(1567.72,10714.4) ; R530.2@1567.72,10789.4 1607.48,10829.16 U50.1@1607.48,10869.4
  L1_Top Layer w10: U50.20@1581.89,10894.99 U50.19@1581.89,10914.68
  L1_Top Layer w12: 1551,10886 1551,10900 1565.68,10914.68 U50.19@1581.89,10914.68
  L1_Top Layer w20: R626.1@1485.81,10631.45 1679.9,10631.45 1709.22,10660.77 R529.1@1709.22,10724.91
NetC667_2: C667.2 R531.1 R532.2 U50.3 | length 254.1
  L1_Top Layer w8: C667.2@1629.72,10713.4 v2(1630.72,10714.4) 1666.14,10749.83 1666.14,10825.4 1646.85,10844.69 U50.3@1646.85,10869.4
  L12_Bottom Layer w11: v2(1630.72,10714.4) R532.2@1630.72,10789.4
NetC668_1: C668.1 U50.12 | length 98.1
  L1_Top Layer w8: U50.12@1666.54,10999.32 1666.54,11025.72 C668.1@1717.22,11076.4
NetC669_1: C669.1 U50.13 | length 73.9
  L1_Top Layer w8: C669.1@1641.22,11070.91 1646.85,11065.28 U50.13@1646.85,10999.32
NetC695_2: C695.2 C696.2 C697.2 C698.1 R535.1 R629.2 TP59.1 U51.3 U51.9 U52.1 | length 139.9
  L12_Bottom Layer w10: U51.9@666.05,11282.14 v1(664.55,11280.65) 677.35,11267.85 U51.3@705.89,11267.85
  L12_Bottom Layer w15: U51.3@705.89,11267.85 730.07,11267.85 747.55,11250.36 C695.2@789.8,11250.36
  other v1: 664.55,11251.12 664.55,11310.18
  other v2: 348,11054 387,11054 348,11093 387,11093 348,11132 387,11132
NetC698_2: C698.2 U51.8 | length 76.6
  L12_Bottom Layer w10: C698.2@603.06,11387.32 623.22,11367.16 U51.8@623.22,11319.03
NetC714_1: C714.1 C716.1 R536.2 R630.1 U53.1 U53.20 | length 68.3
  L1_Top Layer w11: 738.62,10837.88 750.66,10849.92 U53.20@764.38,10849.92 ; 804.73,10771.99 U53.1@804.73,10809.57
NetC715_2: C715.2 R629.1 U53.13 U53.15 U53.16 | length 139.8
  L1_Top Layer w8: U53.13@855.91,10992.64 855.91,11065.17
  L1_Top Layer w10: 730.29,10952.29 U53.16@764.38,10952.29 ; 798,11023 804.73,11016.27 U53.15@804.73,10992.64
NetC716_2: C716.2 R536.1 R537.2 U53.3 | length 206.7
  L1_Top Layer w8: C716.2@855.91,10744.66 U53.3@855.91,10809.57
  L1_Top Layer w20: C716.2@855.91,10744.66 C716.2@858,10742.57 851.42,10735.99 851.42,10688.87 R536.1@845.12,10682.57 918.12,10682.57 R537.2@918.5,10682.95
NetC723_1: C723.1 U53.14 | length 49
  L1_Top Layer w8: U53.14@830.32,10992.64 v2@830.32,11041.47
  L1_Top Layer w10: v2@830.32,11041.47 v2(830.42,11041.57)
NetCALSAT1_1: CALSAT1.1 U8.F7 | length 1883.4
  L1_Top Layer w3.5: U8.F7@2413.91,8240.84 2429.93,8256.86 2429.93,8425.11 2433.82,8429 2433.82,8647.82 2511.5,8725.5
  L1_Top Layer w11: 2511.5,8725.5 2650,8864 3272,8864 3451.44,9043.44 3451.44,9222.69 CALSAT1.1@3375.44,9298.69
NetCALSAT2_1: CALSAT2.1 U17.F7 | length 1963.4
  L1_Top Layer w3.5: U17.F7@2417.24,1894.85 2433.26,1910.86 2433.26,2301.26 2489,2357
  L1_Top Layer w11: 2489,2357 2650,2518 3323,2518 3531,2726 3531,2874 CALSAT2.1@3440,2965
NetCE_TP1_1: CE_TP1.1 R172.2 U19.1 | length 395.5
  L1_Top Layer w11: CE_TP1.1@1863.66,5828.82 1964.61,5828.82 2056.1,5920.31 R172.2@2108.66,5920.31 2108.66,5980.56 2126.28,5998.18 U19.1@2126.28,6025.64
NetCE_TP2_1: CE_TP2.1 R213.2 U21.1 | length 395.5
  L1_Top Layer w11: U21.1@2425.34,3792.33 2425.34,3819.8 2442.96,3837.41 R213.2@2442.96,3897.66 2495.51,3897.66 2587.01,3989.16 CE_TP2.1@2687.96,3989.16
NetD1_1: D1.1 U7.1 | length 88.7
  L1_Top Layer w11: D1.1@4886.21,7277.66 4886.68,7277.18 U7.1@4974.72,7277.18
NetD1_2: D1.2 R50.2 | length 72.6
  L1_Top Layer w11: D1.2@4886.21,7336.71 4886.21,7408.81 R50.2@4886.59,7409.18
NetD3_1: D3.1 U7.7 | length 161.3
  L1_Top Layer w11: U7.7@5163.7,7227.18 5210.71,7227.18 5223.21,7239.68 5223.21,7330.66 D3.1@5227.21,7334.66
NetD3_2: D3.2 R61.2 | length 63.6
  L1_Top Layer w11: D3.2@5227.21,7393.71 5290.12,7393.71 R61.2@5290.59,7394.18
NetD5_2: D5.2 R77.2 | length 67.5
  L1_Top Layer w11: R77.2@3191.1,9317.53 3246.61,9317.53 D5.2@3255.1,9326.03
NetD6_1: D6.1 U16.1 | length 88.7
  L1_Top Layer w11: D6.1@4969.3,869.72 4969.77,869.25 U16.1@5057.81,869.25
NetD6_2: D6.2 R131.2 | length 72.6
  L1_Top Layer w11: D6.2@4969.3,928.78 4969.3,1000.87 R131.2@4969.67,1001.25
NetD8_1: D8.1 U16.7 | length 161.3
  L1_Top Layer w11: U16.7@5246.78,819.25 5293.8,819.25 5306.3,831.75 5306.3,922.72 D8.1@5310.3,926.72
NetD8_2: D8.2 R142.2 | length 63.6
  L1_Top Layer w11: D8.2@5310.3,985.78 5373.2,985.78 R142.2@5373.67,986.25
NetD10_2: D10.2 R158.2 | length 67.5
  L1_Top Layer w11: R158.2@3259.43,2971.76 3314.94,2971.76 D10.2@3323.43,2980.26
NetD11_1: D11.1 R190.1 | length 54.7
  L1_Top Layer w6: R190.1@2499.31,6406.72 2499.31,6460.69 D11.1@2499.81,6461.19
NetD12_1: D12.1 R231.1 | length 54.7
  L1_Top Layer w6: D12.1@2051.8,3356.79 D12.1@2052.31,3357.29
  L1_Top Layer w11: D12.1@2052.31,3357.29 R231.1@2052.31,3411.26
NetD13_1: D13.1 R370.2 | length 61.4
  L1_Top Layer w11: R370.2@5130.98,5352.39 5190.96,5352.39 D13.1@5191.96,5353.39
NetD14_1: D14.1 R371.2 | length 60
  L1_Top Layer w11: R371.2@5132.52,5286.39 D14.1@5192.5,5286.39
NetD15_1: D15.1 R372.2 | length 60
  L1_Top Layer w11: D15.1@4988.39,4251.5 R372.2@4988.39,4311.48
NetD16_1: D16.1 R373.2 | length 61
  L1_Top Layer w11: R373.2@5130.97,5220.14 D16.1@5191.94,5220.14
NetD17_2: D17.2 R469.2 | length 71
  L1_Top Layer w20: D17.2@5630.88,9512.44 R469.2@5701.86,9512.44
NetD18_2: D18.2 R549.2 | length 66.9
  L1_Top Layer w11: D18.2@4813.34,10109 4825.34,10097 R549.2@4875.31,10097
NetD21_1: D21.1 R485.1 | length 65.5
  L1_Top Layer w20: R485.1@4813.81,11074.8 D21.1@4879.29,11074.8
NetJ5_1: J5.1 R57.2 | length 87.5
  L12_Bottom Layer w6: J5.1@3781.08,8971.88 J5.1@3781.97,8970.99
  L12_Bottom Layer w11: J5.1@3781.97,8970.99 R57.2@3868.18,8970.99
NetJ5_3: J5.3 R56.2 | length 87.1
  L12_Bottom Layer w6: J5.3@3781.08,9071.88 J5.3@3781.19,9071.99
  L12_Bottom Layer w11: J5.3@3781.19,9071.99 R56.2@3868.18,9071.99
NetJ5_5: J5.5 R55.2 | length 87.1
  L12_Bottom Layer w6: J5.5@3781.08,9171.88 J5.5@3781.19,9171.99
  L12_Bottom Layer w11: J5.5@3781.19,9171.99 R55.2@3868.18,9171.99
NetJ5_7: J5.7 R54.2 | length 87.1
  L12_Bottom Layer w6: R54.2@3868.07,9271.88 R54.2@3868.18,9271.99
  L12_Bottom Layer w11: J5.7@3781.08,9271.88 R54.2@3868.07,9271.88
NetJ6_2: J6.2 R63.1 | length 86.2
  L12_Bottom Layer w11: J6.2@3056.08,9174.99 3056.08,9260.31 R63.1@3056.68,9260.91
NetJ7_2: J7.2 R64.1 | length 94.1
  L12_Bottom Layer w11: J7.2@3221.08,9174.99 3221.08,9241.06 R64.1@3240.92,9260.91
NetJ12_1: J12.1 U59.1 | length 197
  L12_Bottom Layer w11: U59.1@2334.48,9103.21 J12.1@2334.48,9300.21
NetJ15_1: J15.1 U60.1 | length 197
  L12_Bottom Layer w11: J15.1@2335.24,7149.98 U60.1@2335.24,7346.98
NetJ16_1: J16.1 R138.2 | length 87.5
  L12_Bottom Layer w6: J16.1@3862.72,2686.99 J16.1@3863.61,2686.1
  L12_Bottom Layer w11: J16.1@3863.61,2686.1 R138.2@3949.81,2686.1
NetJ16_3: J16.3 R137.2 | length 87.1
  L12_Bottom Layer w6: J16.3@3862.72,2786.99 J16.3@3862.82,2787.1 ; R137.2@3945.09,2787.1 R137.2@3949.81,2787.1
  L12_Bottom Layer w11: J16.3@3862.82,2787.1 R137.2@3945.09,2787.1
NetJ16_5: J16.5 R136.2 | length 87.1
  L12_Bottom Layer w6: J16.5@3862.72,2886.99 J16.5@3862.82,2887.1
  L12_Bottom Layer w11: J16.5@3862.82,2887.1 R136.2@3949.81,2887.1
NetJ16_7: J16.7 R135.2 | length 87
  L12_Bottom Layer w11: J16.7@3862.72,2986.99 R135.2@3949.71,2986.99
NetJ17_2: J17.2 R144.1 | length 80.7
  L12_Bottom Layer w11: J17.2@3126.01,2825.21 3126.01,2905.4 R144.1@3126.37,2905.76
NetJ18_2: J18.2 R145.1 | length 86.6
  L12_Bottom Layer w11: J18.2@3291.01,2825.21 3303.9,2838.1 R145.1@3303.9,2906.49
NetJ29_1: J29.1 U61.1 | length 197
  L12_Bottom Layer w11: U61.1@2337.48,2757.59 J29.1@2337.48,2954.59
NetJ31_6: J31.6 R595.2 | length 130.4
  L1_Top Layer w11: J31.6@4447.07,9182.1 4448.07,9181.1 J31.6@4453,9181.1 ; J31.6@4453,9175 4459.1,9181.1 R595.2@4574.57,9181.1
NetJ31_9: J31.9 R593.1 | length 70.2
  L12_Bottom Layer w11: R593.1@4283,8975.5 4283.5,8975 J31.9@4353,8975
NetJ32_6: J32.6 R596.2 | length 130.6
  L1_Top Layer w11: R596.2@6582.78,10410.05 6583.73,10411 J32.6@6713,10411
NetJ35_2: J35.2 R404.2 U26.9 | length 332.7
  L1_Top Layer w11: U26.9@5707,10333.41 R404.2@5707,10276 5930,10276 J35.2@5967,10239
NetJ36_2: J36.2 R411.2 U27.9 | length 136.1
  L1_Top Layer w11: U27.9@4908.68,9306.77 4908.68,9354.65 R411.2@4908.32,9355 4908.32,9433.5 J36.2@4914.82,9440
NetJ37_2: J37.2 R420.2 U28.1 | length 292.9
  L1_Top Layer w11: U28.1@6132.45,10107.31 6165.69,10107.31 6184,10089 6184,9967.83 R420.2@6191.54,9960.28 6191.54,9860.54 J37.2@6190,9859
NetJ38_2: J38.2 R425.2 U29.9 | length 160.1
  L12_Bottom Layer w11: U29.9@5575.96,9342.57 5575.96,9400.65 R425.2@5576.31,9401 5675,9401 J38.2@5677,9403
NetJ39_1: J39.1 R601.2 | length 210.9
  L1_Top Layer w11: R601.2@4262,9588 4405,9588 J39.1@4453,9540
NetJ39_5: J39.5 R602.2 | length 219.6
  L1_Top Layer w11: R602.2@4262,9809 4282.82,9788.18 4404.82,9788.18 J39.5@4453,9740
NetJ39_6: J39.6 R600.2 | length 89.9
  L12_Bottom Layer w11: R600.2@4263.5,9739 4264.5,9740 J39.6@4353,9740
NetJ39_9: J39.9 R597.1 R598.1 | length 276.2
  L1_Top Layer w11: R597.1@4263.5,9889 R597.1@4263.5,9890 ; R598.1@4263.5,9955 R597.1@4263.5,9890 ; J39.9@4453,9940 4403,9890 R597.1@4263.5,9890
NetJ39_10: J39.10 R599.1 | length 95.7
  L12_Bottom Layer w11: R599.1@4263.5,9955 4338,9955 J39.10@4353,9940
NetJ41_2: J41.2 R440.2 U30.9 | length 170.1
  L1_Top Layer w11: U30.9@3595.33,6782.79 3595.33,6842.97 R440.2@3595.07,6843.23 3651.58,6843.23 J41.2@3689.07,6880.73
NetJ42_2: J42.2 R441.2 U31.9 | length 170.1
  L1_Top Layer w11: U31.9@3598.66,436.79 3598.66,496.98 R441.2@3598.4,497.23 3654.91,497.23 J42.2@3692.4,534.73
NetJ43_2: J43.2 R467.2 U32.9 | length 188.7
  L1_Top Layer w11: J43.2@3475.43,7312.26 3531.43,7312.26 3558.93,7284.76 R467.2@3595.43,7284.76 3595.33,7284.66 U32.9@3595.33,7227.49
NetJ44_2: J44.2 R468.2 U33.9 | length 169.7
  L1_Top Layer w11: R468.2@3598.4,941.94 3654.91,941.94 J44.2@3692.4,979.44 ; U33.9@3598.66,881.5 R468.2@3598.66,941.68
NetJ45_1: J45.1 J46.D1 | length 250.7
  L1_Top Layer w11: v1(6563.11,8820.01) J45.1@6563.11,9070.71
NetJ46_C39: J46.C39 J46.D36 J46.D38 J46.D40 R474.2 | length 316.9
  L1_Top Layer w11: R474.2@6563.11,6813.63 v1(6563.11,6870.01)
  L12_Bottom Layer w5: v1(6563.11,6870.01) J46.C39@6613.11,6920.01 J46.D38@6563.11,6970.01 6586.11,6993.01 6586.11,7047.01 J46.D36@6563.11,7070.01
NetJ46_D30: J46.D30 J47.1 | length 776.9
  L12_Bottom Layer w5: 6104.09,7381.18 6115.92,7393.01 6540.11,7393.01 J46.D30@6563.11,7370.01
  L12_Bottom Layer w11: J47.1@5832.09,7305.18 5888.09,7361.18 6084.09,7361.18 6104.09,7381.18
NetJ46_D31: J46.D31 J47.2 | length 658.7
  L12_Bottom Layer w5: 6098.09,7330.01 6114.09,7346.01 6537.11,7346.01 J46.D31@6563.11,7320.01
  L12_Bottom Layer w11: J47.2@5932.09,7305.18 6073.26,7305.18 6098.09,7330.01
NetJ49_2: J49.2 R475.2 | length 88.9
  L1_Top Layer w11: R475.2@6790.4,9158.77 6790.81,9158.37 J49.2@6790.81,9070.01
NetJ50_1: J50.1 J51.D1 | length 250.7
  L1_Top Layer w11: v1@6566.75,2476.81 J50.1@6566.75,2727.51
  other v1: 6566.44,2474.01
NetJ51_C39: J51.C39 J51.D36 J51.D38 J51.D40 R479.2 | length 313.4
  L1_Top Layer w11: v1(6566.44,524.01) 6566.75,523.7 R479.2@6566.75,470.43
  L12_Bottom Layer w5: J51.D40@6566.75,526.81 6616.75,576.81 6566.75,626.81 6588.75,648.81 6588.75,704.81 J51.D36@6566.75,726.81
NetJ54_2: J54.2 R480.2 | length 84.5
  L1_Top Layer w11: R480.2@6782.88,2802.86 6788.13,2797.61 J54.2@6788.13,2720.51
NetJ55_1: J55.1 S17.2
NetJ61_1: J61.1 R393.1 | length 209.1
  L1_Top Layer w11: J61.1@5212.88,4087.24 5212.88,4295.95 R393.1@5213.17,4296.24
NetJ64_1: J64.1 U2.6 | length 225.5
  L1_Top Layer w11: J64.1@949.68,8685.66 1034.25,8770.23 U2.6@1034.25,8876.14
NetJ67_1: J67.1 U1.9 | length 231.7
  L1_Top Layer w11: U1.9@648.91,8885.71 648.91,8765.42 J67.1@727.68,8686.66
NetJ68_1: J68.1 U5.6 | length 225.5
  L1_Top Layer w11: J68.1@951.47,7263.53 1036.05,7348.1 U5.6@1036.05,7454.01
NetJ72_1: J72.1 R470.1 | length 123
  L1_Top Layer w20: R470.1@6493.91,9426.85 6542.66,9475.6 J72.1@6596.73,9475.6
NetJ74_1: J74.1 U62.1 | length 197
  L12_Bottom Layer w11: J74.1@2339.42,804.02 U62.1@2339.42,1001.02
NetJ75_1: J75.1 R163.1 | length 83.8
  L1_Top Layer w11: R163.1@5872.62,6011.62 R163.1@5872.89,6011.36 J75.1@5956.31,6011.36
NetJ75_3: J75.3 R166.2 | length 83.4
  L1_Top Layer w11: R166.2@5872.89,5811.36 J75.3@5956.31,5811.36
NetJ78_1: J78.1 U4.9 | length 231.7
  L1_Top Layer w11: U4.9@650.71,7463.59 650.71,7343.29 J78.1@729.47,7264.53
NetJ79_1: J79.1 U11.6 | length 225.5
  L1_Top Layer w11: J79.1@952.99,2339.29 1037.57,2423.87 U11.6@1037.57,2529.78
NetJ82_1: J82.1 U10.9 | length 231.7
  L1_Top Layer w11: U10.9@652.23,2539.35 652.23,2419.06 J82.1@730.99,2340.29
NetJ83_1: J83.1 U14.6 | length 225.5
  L1_Top Layer w11: J83.1@953.07,919.96 1037.64,1004.53 U14.6@1037.64,1110.44
NetJ84_1: J84.1 U13.9 | length 231.7
  L1_Top Layer w11: U13.9@652.3,1120.02 652.3,999.72 J84.1@731.07,920.96
NetL2_2: L2.2 R4.1 R7.2 | length 116.5
  L1_Top Layer w11: L2.2@1425.72,8960.94 1491.9,8960.94 R7.2@1492.1,8961.13 R4.1@1492.1,9011.13
NetL4_2: L4.2 R17.2 R18.1 | length 116.5
  L1_Top Layer w11: L4.2@1425.72,8909.33 1491.9,8909.33 R17.2@1492.1,8909.13 R18.1@1492.1,8859.13
NetL6_2: L6.2 R28.1 R31.2 | length 116.5
  L1_Top Layer w11: L6.2@1427.52,7538.81 1493.7,7538.81 R31.2@1493.9,7539.01 R28.1@1493.9,7589.01
NetL8_2: L8.2 R41.2 R42.1 | length 116.5
  L1_Top Layer w11: L8.2@1427.52,7487.2 1493.7,7487.2 R41.2@1493.9,7487.01 R42.1@1493.9,7437.01
NetL10_2: L10.2 R85.1 R88.2 | length 116.5
  L1_Top Layer w11: L10.2@1429.04,2614.58 1495.22,2614.58 R88.2@1495.42,2614.77 R85.1@1495.42,2664.77
NetL12_2: L12.2 R98.2 R99.1 | length 116.5
  L1_Top Layer w11: L12.2@1429.04,2562.97 1495.22,2562.97 R98.2@1495.42,2562.77 R99.1@1495.42,2512.77
NetL14_2: L14.2 R109.1 R112.2 | length 116.5
  L1_Top Layer w11: L14.2@1429.11,1195.24 1495.29,1195.24 R112.2@1495.49,1195.44 R109.1@1495.49,1245.44
NetL16_2: L16.2 R122.2 R123.1 | length 116.5
  L1_Top Layer w11: L16.2@1429.11,1143.63 1495.29,1143.63 R122.2@1495.49,1143.44 R123.1@1495.49,1093.44
NetL75_2: L75.2 R4.2 R638.1 | length 66.9
  L1_Top Layer w9: R638.1@1598.13,9011 L75.2@1606,9011 L75.2@1605.87,9011.13
  L1_Top Layer w11: R4.2@1539.34,9011.13 1539.48,9011 R638.1@1598.13,9011
NetL75_5: L75.5 LF1.1 R174.1 R638.2 | length 70.2
  L1_Top Layer w9: L75.5@1637.5,9011 R638.2@1645.37,9011
  L1_Top Layer w11: R638.2@1645.37,9011 1707.22,9011 LF1.1@1707.54,9010.68
NetL76_2: L76.2 R18.2 R639.1 | length 58.8
  L1_Top Layer w11: R18.2@1539.34,8859.13 1597.99,8859.13 R639.1@1598.13,8859
NetL76_5: L76.5 LF2.1 R181.1 R639.2 | length 62.3
  L1_Top Layer w11: R639.2@1645.37,8859 LF2.1@1707.63,8859
NetL77_2: L77.2 R28.2 R640.1 | length 58.6
  L1_Top Layer w11: R28.2@1541.14,7589.01 L77.2@1599.79,7589.01
NetL77_5: L77.5 LF3.1 R186.1 R640.2 | length 61.8
  L1_Top Layer w11: R640.2@1645.37,7588.6 R186.1@1707.22,7588.6
NetL78_2: L78.2 R42.2 R641.1 | length 58.6
  L1_Top Layer w11: R42.2@1541.01,7437.14 L78.2@1599.65,7437.14
NetL78_5: L78.5 LF4.1 R188.1 R641.2 | length 62.3
  L1_Top Layer w11: L78.5@1645.37,7436.6 R188.1@1707.22,7436.6 R188.1@1707.63,7436.6
NetL79_2: L79.2 R85.2 R642.1 | length 55.6
  L1_Top Layer w11: R85.2@1542.66,2664.77 cw(c1543.97,2663.46) 1543.97,2665.31 L79.2@1598.13,2665.31
NetL79_5: L79.5 LF5.1 R204.1 R642.2 | length 61.8
  L1_Top Layer w11: R642.2@1645.37,2665 R204.1@1707.22,2665
NetL80_2: L80.2 R99.2 R643.1 | length 63.4
  L1_Top Layer w11: R99.2@1542.66,2512.77 1542.89,2513 R643.1@1598.13,2513 L80.2@1606,2513
NetL80_5: L80.5 LF6.1 R207.1 R643.2 | length 62.3
  L1_Top Layer w11: L80.5@1646.98,2513.44 R207.1@1708.82,2513.44 ; R207.1@1707.22,2513 R207.1@1707.63,2513
NetL81_2: L81.2 R109.2 R644.1 | length 55.4
  L1_Top Layer w11: R109.2@1542.74,1245.44 L81.2@1598.13,1245.44
NetL81_5: L81.5 LF7.1 R215.1 R644.2 | length 61.8
  L1_Top Layer w11: R644.2@1645.37,1245.9 R215.1@1707.22,1245.9
NetL82_2: L82.2 R123.2 R645.1 | length 55.5
  L1_Top Layer w11: R123.2@1542.74,1093.44 1597.71,1093.44 R645.1@1598.08,1093.8
NetL82_5: L82.5 LF8.1 R222.1 R645.2 | length 61.8
  L1_Top Layer w11: L82.5@1645.37,1093.9 R222.1@1707.22,1093.9
NetOSCinM1_1: OSCinM1.1 R198.1 | length 278.5
  L1_Top Layer w11: OSCinM1.1@2537.16,5135.82 R198.1@2537.16,5414.32
NetOSCinM2_1: OSCinM2.1 R241.1 | length 278.5
  L1_Top Layer w11: R241.1@2014.46,4403.65 OSCinM2.1@2014.46,4682.16
NetOSCinM3_1: OSCinM3.1 R326.2 | length 219.8
  L1_Top Layer w11: R326.2@5262.04,6257.06 OSCinM3.1@5262.06,6476.85
NetOSCinP1_1: OSCinP1.1 R191.1 | length 278.5
  L1_Top Layer w11: OSCinP1.1@2014.46,5135.82 R191.1@2014.46,5414.32
NetOSCinP2_1: OSCinP2.1 R232.1 | length 278.5
  L1_Top Layer w11: R232.1@2537.16,4403.65 OSCinP2.1@2537.16,4682.16
NetOSCinP3_1: OSCinP3.1 R323.2 | length 219.8
  L1_Top Layer w11: R323.2@5809.06,6257.06 OSCinP3.1@5809.06,6476.85
NetR6_2: R6.2 U1.4 | length 73.8
  L1_Top Layer w11: R6.2@532.53,8966.99 539.01,8960.52 U1.4@603.64,8960.52
NetR9_1: R9.1 U1.13 | length 83
  L1_Top Layer w6: U1.13@694.19,8940.83 712,8940.83 716.34,8936.49 740.79,8936.49 R9.1@765.29,8960.99
NetR9_2: R9.2 R10.2 | length 58
  L1_Top Layer w6: R9.2@812.53,8960.99 870.2,8960.99 R10.2@870.47,8961.26
NetR10_1: R10.1 U2.2 | length 83.2
  L1_Top Layer w6: R10.1@917.71,8961.26 942.21,8936.76 966.82,8936.76 971.16,8941.1 U2.2@988.97,8941.1
NetR11_2: R11.2 U2.11 | length 77.5
  L1_Top Layer w6: U2.11@1099.21,8941.1 1117.02,8941.1 1121.36,8936.76 1142.62,8936.76 R11.2@1165.47,8959.6
NetR13_1: R13.1 U1.12 | length 83
  L1_Top Layer w6: U1.12@694.19,8921.15 712,8921.15 716.34,8925.49 740.79,8925.49 R13.1@765.29,8900.99
NetR13_2: R13.2 R14.2 | length 58
  L1_Top Layer w6: R13.2@812.53,8900.99 870.2,8900.99 R14.2@870.47,8901.26
NetR14_1: R14.1 U2.3 | length 83.2
  L1_Top Layer w6: R14.1@917.71,8901.26 942.21,8925.76 966.82,8925.76 971.16,8921.42 U2.3@988.97,8921.42
NetR15_2: R15.2 U2.10 | length 74.7
  L1_Top Layer w6: U2.10@1099.21,8921.42 1117.02,8921.42 1121.36,8925.76 1149.32,8925.76 R15.2@1165.47,8909.6
NetR16_2: R16.2 U1.7 | length 73.8
  L1_Top Layer w11: R16.2@532.53,8895.01 538.99,8901.46 U1.7@603.64,8901.46
NetR30_2: R30.2 U4.4 | length 73.8
  L1_Top Layer w11: R30.2@534.33,7544.86 540.8,7538.39 U4.4@605.43,7538.39
NetR33_1: R33.1 U4.13 | length 83
  L1_Top Layer w6: U4.13@695.98,7518.71 713.79,7518.71 718.14,7514.36 742.59,7514.36 R33.1@767.09,7538.86
NetR33_2: R33.2 R34.2 | length 58
  L1_Top Layer w6: R33.2@814.33,7538.86 872,7538.86 R34.2@872.27,7539.13
NetR34_1: R34.1 U5.2 | length 83.2
  L1_Top Layer w6: R34.1@919.51,7539.13 944.01,7514.63 968.62,7514.63 972.96,7518.97 U5.2@990.77,7518.97
NetR35_2: R35.2 U5.11 | length 77.5
  L1_Top Layer w6: U5.11@1101.01,7518.97 1118.82,7518.97 1123.16,7514.63 1144.42,7514.63 R35.2@1167.27,7537.48
NetR37_1: R37.1 U4.12 | length 83
  L1_Top Layer w6: U4.12@695.98,7499.02 713.79,7499.02 718.14,7503.36 742.59,7503.36 R37.1@767.09,7478.86
NetR37_2: R37.2 R38.2 | length 58
  L1_Top Layer w6: R37.2@814.33,7478.86 872,7478.86 R38.2@872.27,7479.13
NetR38_1: R38.1 U5.3 | length 83.2
  L1_Top Layer w6: R38.1@919.51,7479.13 944.01,7503.63 968.62,7503.63 972.96,7499.29 U5.3@990.77,7499.29
NetR39_2: R39.2 U5.10 | length 74.7
  L1_Top Layer w6: U5.10@1101.01,7499.29 1118.82,7499.29 1123.16,7503.63 1151.11,7503.63 R39.2@1167.27,7487.48
NetR40_2: R40.2 U4.7 | length 73.8
  L1_Top Layer w11: R40.2@534.33,7472.88 540.79,7479.34 U4.7@605.43,7479.34
NetR74_1: R74.1 R77.1 TP1.1 U9.10 | length 440
  L1_Top Layer w11: TP1.1@2939.59,9304.79 3014.9,9380.1 3190.68,9380.1 R77.1@3191.1,9380.52 3191.48,9380.9 R74.1@3191.48,9447.03 3185.76,9447.03 3156.89,9475.9 U9.10@3112.97,9475.9
NetR75_1: R75.1 TP3.1 U9.11 | length 266.5
  L1_Top Layer w11: U9.11@3112.97,9495.58 3142.59,9495.58 3157.03,9510.03 R75.1@3191.48,9510.03 3221.61,9479.89 TP3.1@3360.97,9479.89
NetR76_1: R76.1 TP2.1 U9.14 | length 209.6
  L1_Top Layer w11: TP2.1@3035.1,9732.03 3112.72,9654.4 R76.1@3112.72,9623.03 3112.97,9622.78 U9.14@3112.97,9554.64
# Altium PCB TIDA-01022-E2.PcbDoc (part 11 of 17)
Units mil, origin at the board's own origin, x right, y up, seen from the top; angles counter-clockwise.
Board outline 6929.13 x 11614.17 mil, 12 copper layers (L1_Top Layer, L2_GND, L3_GND, L4_Signal Layer 1, L5_GND, L6_PWR, L7_GND/PWR, L8_PWR, L9_GND/PWR, L10_Signal Layer 2, L11_GND, L12_Bottom Layer), stack 64.6 mil thick; 1711 components, 1002 nets, 5985 pads, 3200 vias.

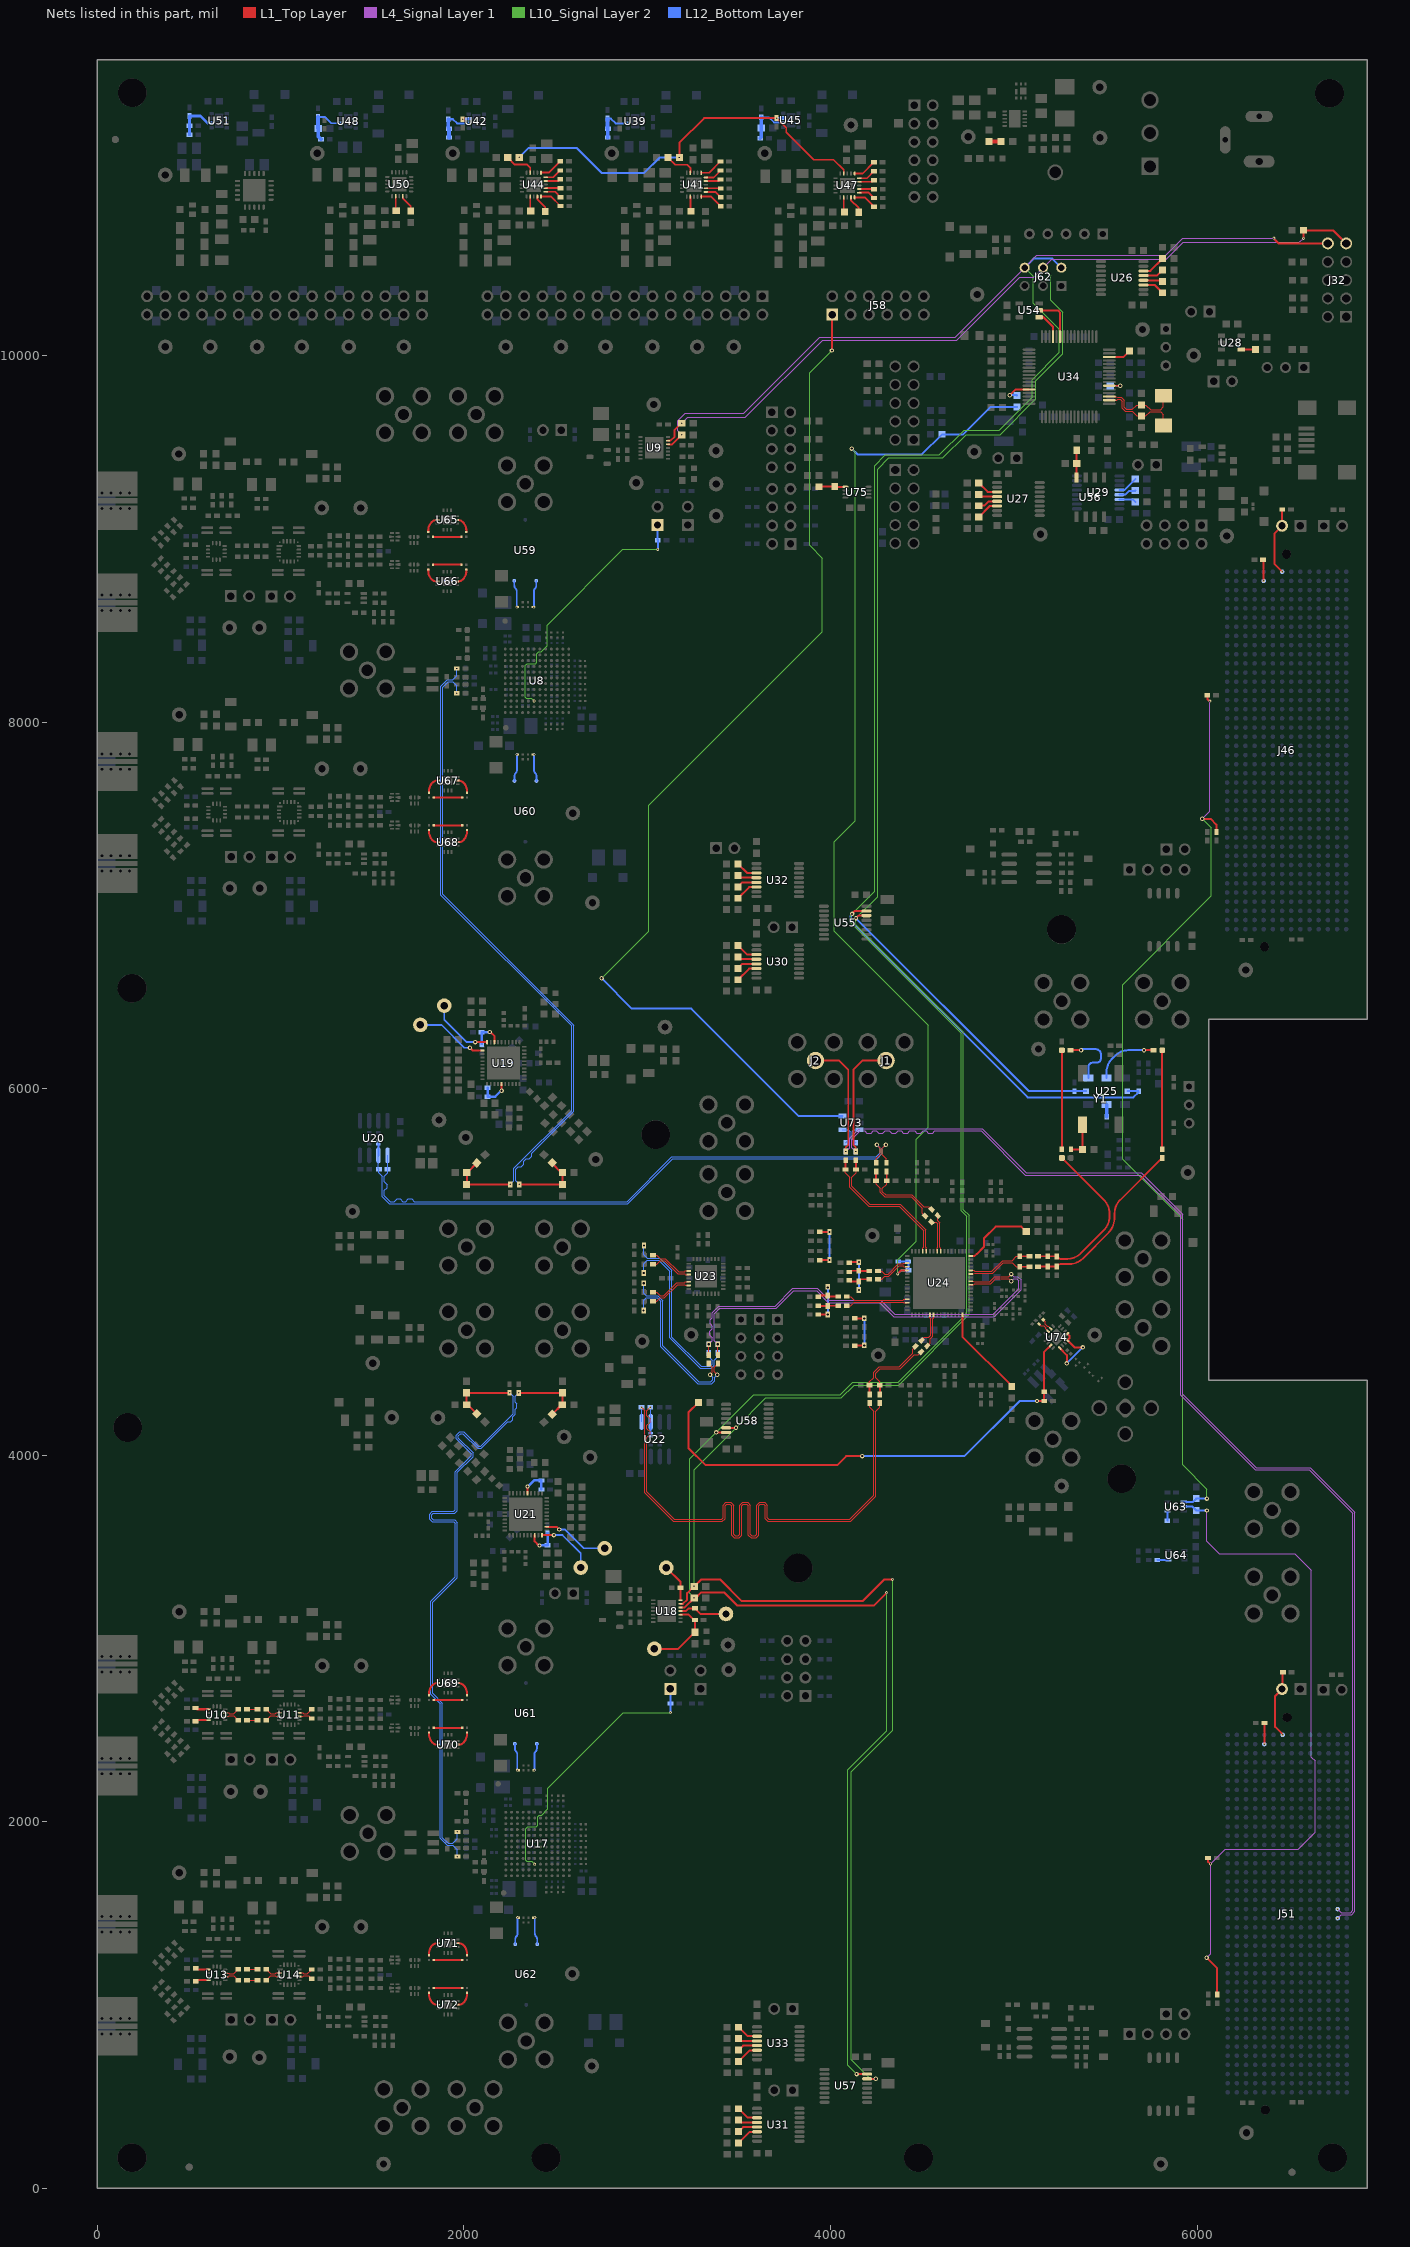
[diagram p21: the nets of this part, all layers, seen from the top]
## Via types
v1: diameter 16, hole 8, L1_Top Layer to L12_Bottom Layer, tented both sides, 1699 vias
v2: diameter 24, hole 12, L1_Top Layer to L12_Bottom Layer, tented both sides, 1501 vias

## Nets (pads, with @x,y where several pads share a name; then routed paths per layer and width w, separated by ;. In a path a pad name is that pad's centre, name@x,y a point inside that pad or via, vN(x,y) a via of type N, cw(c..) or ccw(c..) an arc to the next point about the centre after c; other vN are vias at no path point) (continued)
NetR87_2: R87.2 U10.4 | length 73.8
  L1_Top Layer w11: R87.2@535.85,2620.63 542.32,2614.16 U10.4@606.95,2614.16
NetR90_1: R90.1 U10.13 | length 83
  L1_Top Layer w6: U10.13@697.5,2594.47 715.31,2594.47 719.66,2590.13 744.11,2590.13 R90.1@768.61,2614.63
NetR90_2: R90.2 R91.2 | length 58
  L1_Top Layer w6: R90.2@815.85,2614.63 873.52,2614.63 R91.2@873.79,2614.9
NetR91_1: R91.1 U11.2 | length 83.2
  L1_Top Layer w6: R91.1@921.03,2614.9 945.53,2590.4 970.14,2590.4 974.48,2594.74 U11.2@992.29,2594.74
NetR92_2: R92.2 U11.11 | length 77.5
  L1_Top Layer w6: U11.11@1102.53,2594.74 1120.34,2594.74 1124.68,2590.4 1145.94,2590.4 R92.2@1168.79,2613.24
NetR94_1: R94.1 U10.12 | length 83
  L1_Top Layer w6: U10.12@697.5,2574.79 715.31,2574.79 719.66,2579.13 744.11,2579.13 R94.1@768.61,2554.63
NetR94_2: R94.2 R95.2 | length 58
  L1_Top Layer w6: R94.2@815.85,2554.63 873.52,2554.63 R95.2@873.79,2554.9
NetR95_1: R95.1 U11.3 | length 83.2
  L1_Top Layer w6: R95.1@921.03,2554.9 945.53,2579.4 970.14,2579.4 974.48,2575.05 U11.3@992.29,2575.05
NetR96_2: R96.2 U11.10 | length 74.7
  L1_Top Layer w6: U11.10@1102.53,2575.05 1120.34,2575.05 1124.68,2579.4 1152.63,2579.4 R96.2@1168.79,2563.24
NetR97_2: R97.2 U10.7 | length 73.8
  L1_Top Layer w11: R97.2@535.85,2548.64 542.31,2555.1 U10.7@606.95,2555.1
NetR111_2: R111.2 U13.4 | length 73.8
  L1_Top Layer w11: R111.2@535.92,1201.29 542.4,1194.82 U13.4@607.03,1194.82
NetR114_1: R114.1 U13.13 | length 83
  L1_Top Layer w6: U13.13@697.58,1175.14 715.39,1175.14 719.73,1170.79 744.18,1170.79 R114.1@768.68,1195.29
NetR114_2: R114.2 R115.2 | length 58
  L1_Top Layer w6: R114.2@815.92,1195.29 873.59,1195.29 R115.2@873.86,1195.56
NetR115_1: R115.1 U14.2 | length 83.2
  L1_Top Layer w6: R115.1@921.11,1195.56 945.61,1171.06 970.21,1171.06 974.55,1175.4 U14.2@992.37,1175.4
NetR116_2: R116.2 U14.11 | length 77.5
  L1_Top Layer w6: U14.11@1102.6,1175.4 1120.41,1175.4 1124.76,1171.06 1146.02,1171.06 R116.2@1168.86,1193.91
NetR118_1: R118.1 U13.12 | length 83
  L1_Top Layer w6: U13.12@697.58,1155.45 715.39,1155.45 719.73,1159.79 744.18,1159.79 R118.1@768.68,1135.29
NetR118_2: R118.2 R119.2 | length 58
  L1_Top Layer w6: R118.2@815.92,1135.29 873.59,1135.29 R119.2@873.86,1135.56
NetR119_1: R119.1 U14.3 | length 83.2
  L1_Top Layer w6: R119.1@921.11,1135.56 945.61,1160.06 970.21,1160.06 974.55,1155.72 U14.3@992.37,1155.72
NetR120_2: R120.2 U14.10 | length 74.7
  L1_Top Layer w6: U14.10@1102.6,1155.72 1120.41,1155.72 1124.76,1160.06 1152.71,1160.06 R120.2@1168.86,1143.91
NetR121_2: R121.2 U13.7 | length 73.8
  L1_Top Layer w11: R121.2@535.92,1129.31 542.38,1135.76 U13.7@607.03,1135.76
NetR155_1: R155.1 R158.1 TP7.1 U18.10 | length 415.4
  L1_Top Layer w11: TP7.1@3038.77,2943.93 3168.6,2943.93 R158.1@3259.43,3034.75 3259.81,3035.13 R155.1@3259.81,3101.26 3254.09,3101.26 3225.22,3130.13 U18.10@3181.3,3130.13
NetR156_1: R156.1 TP9.1 U18.11 | length 266.5
  L1_Top Layer w11: U18.11@3181.3,3149.82 3210.92,3149.82 3225.36,3164.26 R156.1@3259.81,3164.26 3289.95,3134.12 TP9.1@3429.3,3134.12
NetR157_1: R157.1 TP8.1 U18.14 | length 209.6
  L1_Top Layer w11: TP8.1@3103.43,3386.26 3181.05,3308.64 R157.1@3181.05,3277.26 3181.3,3277.01 U18.14@3181.3,3208.87
NetR178_1: R178.1 R182.1 U19.5 | length 176.3
  L1_Top Layer w11: v2@2205.02,5988.82 U19.5@2205.02,6025.64
  L1_Top Layer w13.5: v2@2205.02,5988.82 v2(2205.31,5988.52)
  L12_Bottom Layer w13.5: R178.1@2128.93,6004.52 R182.1@2128.93,5955.52 2169.31,5955.52 2202.31,5988.52 v2(2205.31,5988.52)
NetR183_1: R183.1 R184.1 U19.28 | length 176.8
  L1_Top Layer w11: v2(2140.28,6308.92) 2144.28,6308.92 2165.65,6287.55 U19.28@2165.65,6253.99
  L12_Bottom Layer w13.5: R184.1@2096.31,6244.14 2095.93,6244.52 R183.1@2095.93,6308.52 2139.89,6308.52 v2(2140.28,6308.92)
NetR185_1: R185.1 R189.1 R191.2 R192.1 R195.2 | length 3680.5
  L1_Top Layer w11: R191.2@2015.15,5477.82 R189.1@2015.15,5542.82 ; R191.2@2015.41,5477.56 v1(2252.66,5477.56) ; R189.1@2016.91,5541.06 R192.1@2069.99,5594.15
  L12_Bottom Layer w6: v1(1960.92,8292.24) 1960.92,8252.42 1939,8230.5 1908.5,8230.5 1873,8195 1873,7056 2587,6342 2587,5880 2271.76,5564.76 2271.76,5496.66 v1(2252.66,5477.56)
NetR197_2: R197.2 R198.2 R199.2 R202.2 R203.2 | length 3676.6
  L1_Top Layer w11: R203.2@2302.41,5477.31 R198.2@2537.16,5477.31 ; R199.2@2481.53,5591.65 2533.76,5539.42 2537.16,5536.02 R198.2@2537.16,5477.37
  L12_Bottom Layer w6: v1(1960.92,8157.76) 1960.92,8197.58 1939,8219.5 1913.06,8219.5 1884,8190.44 1884,7060.56 2598,6346.56 2598,5875.44 2369,5646.44 2369,5630 2356.28,5617.28 2339.84,5617.28 2326,5603.44 2326,5587 2312.44,5573.44 2296,5573.44 2282.76,5560.2 2282.76,5496.35 v1(2301.86,5477.25)
NetR219_1: R219.1 R223.1 U21.5 | length 176.3
  L1_Top Layer w11: U21.5@2346.6,3792.33 v2@2346.6,3829.16
  L1_Top Layer w13.5: v2(2346.3,3829.45) v2@2346.6,3829.16
  L12_Bottom Layer w13.5: v2(2346.3,3829.45) 2349.3,3829.45 2382.3,3862.45 R223.1@2422.68,3862.45 R219.1@2422.68,3813.45
NetR224_1: R224.1 R225.1 U21.28 | length 179.3
  L1_Top Layer w11: U21.28@2385.97,3563.98 2385.97,3530.42 2408.9,3507.49 v2(2411.74,3507.49)
  L12_Bottom Layer w13.5: v2(2411.74,3507.49) 2411.73,3509.45 R224.1@2455.68,3509.45 2455.68,3573.45 R225.1@2455.3,3573.83
NetR226_1: R226.1 R230.1 R232.2 R233.1 R236.2 | length 3680.7
  L1_Top Layer w11: v1(2298.96,4340.41) 2299.16,4340.41 R232.2@2536.21,4340.41 ; R233.1@2481.63,4223.83 R230.1@2534.71,4276.91 ; R230.1@2536.46,4275.16 R232.2@2536.46,4340.16
  L12_Bottom Layer w6: v1(1964.25,1944.84) 1964.25,1907.47 1939.88,1883.1 1912.76,1883.1 1882,1913.86 1882,2647.56 1828.78,2700.78 1828.78,3197.78 1963,3332 1963,3632.78 1948.28,3647.5 1831.28,3647.5 1823,3655.78 1823,3674.22 1831.28,3682.5 1948.28,3682.5 1963,3697.22 1963,3906 2049.24,3992.24 2049.24,4013.06 1968.63,4093.67 1968.63,4105.38 1981.67,4118.42 1993.38,4118.42 2073.99,4037.81 2094.81,4037.81 2239,4182 2256,4182 2266.58,4192.58 2266.58,4209.58 2279.58,4222.58 2279.58,4251 2288.58,4260 2288.58,4281 2279.58,4290 2279.58,4321.04 v1(2298.96,4340.41)
NetR238_2: R238.2 R241.2 R242.2 R243.2 R244.2 | length 3676.5
  L1_Top Layer w11: R241.2@2014.45,4340.61 2014.45,4281.96 2017.85,4278.56 R242.2@2070.09,4226.33 ; R241.2@2014.46,4340.66 2248.66,4340.66 v1(2249.21,4340.66)
  L12_Bottom Layer w6: v1(1964.25,1810.35) 1964.25,1847.72 1939.88,1872.1 1908.2,1872.1 1881.26,1899.04 1871,1909.3 1871,2643 1821,2693 1817.78,2696.22 1817.78,3202.33 1821,3205.56 1952,3336.56 1952,3628.22 1943.72,3636.5 1826.72,3636.5 1812,3651.22 1812,3678.78 1826.72,3693.5 1943.72,3693.5 1952,3701.78 1952,3910.56 2038.24,3996.8 2038.24,4008.51 1957.63,4089.12 1957.63,4109.94 1977.12,4129.42 1997.94,4129.42 2078.55,4048.81 2090.25,4048.81 2175.22,4133.78 2268.58,4227.14 2268.58,4321.29 v1(2249.21,4340.66)
NetR252_2: R252.2 R253.1 | length 963.1
  L12_Bottom Layer w6: v2(2982,5143.91) 2982,5092.92 3000.13,5074.79 3067.9,5074.79 3134.13,5008.56 3134.13,4644.87 3293.55,4485.45 3344.45,4485.45 3354.5,4495.5 3354.5,4517.67 3335.5,4536.67 R253.1@3335.5,4558.42
NetR254_1: R254.1 U23.3 | length 234.5
  L1_Top Layer w6: R254.1@3030.62,5091.58 3052.37,5091.58 3071.37,5072.58 3099.11,5072.58 3170.73,5000.96 3203.65,5000.96 3207.99,5005.3 U23.3@3225.8,5005.3
NetR255_1: R255.1 U23.4 | length 234.5
  L1_Top Layer w6: R255.1@3030.62,5042.58 3052.37,5042.58 3071.37,5061.58 3094.56,5061.58 3166.17,4989.96 3203.65,4989.96 3207.99,4985.62 U23.4@3225.8,4985.62
NetR256_2: R256.2 R257.1 | length 981.7
  L12_Bottom Layer w6: v2(2981,4994.67) 2981,5044.66 3000.13,5063.79 3063.35,5063.79 3123.13,5004 3123.13,4640.31 3288.99,4474.45 3349.01,4474.45 3352.23,4477.68 3365.5,4490.94 3365.5,4517.67 3384.5,4536.67 R257.1@3384.5,4558.42
NetR260_2: R260.2 R261.1 | length 888.3
  L1_Top Layer w6: R261.1@3335.75,4499.92 3355.25,4480.42 3355.25,4451.24 v2(3342.71,4438.69)
  L12_Bottom Layer w6: v2(2981,4937.91) 2981,4882.42 2994.13,4869.29 3058.4,4869.29 3084.13,4843.56 3084.13,4596.33 3280.01,4400.45 3346.71,4400.45 3356.71,4410.45 3356.71,4424.69 v2(3342.71,4438.69)
NetR262_1: R262.1 U23.6 | length 234.5
  L1_Top Layer w6: R262.1@3030.62,4889.29 3052.37,4889.29 3071.37,4870.29 3088.96,4870.29 3160.58,4941.91 3203.65,4941.91 3207.99,4946.25 U23.6@3225.8,4946.25
NetR264_1: R264.1 U23.7 | length 234.5
  L1_Top Layer w6: R264.1@3030.62,4840.29 3052.37,4840.29 3071.37,4859.29 3093.51,4859.29 3165.13,4930.91 3203.65,4930.91 3207.99,4926.56 U23.7@3225.8,4926.56
NetR265_2: R265.2 R266.1 | length 908.2
  L1_Top Layer w6: v2(3381.71,4438.69) 3366.25,4454.15 3366.25,4480.42 R266.1@3385.75,4499.92
  L12_Bottom Layer w6: v2(2980,4789.67) 2980,4844.16 2994.13,4858.29 3053.85,4858.29 3073.13,4839 3073.13,4591.78 3275.45,4389.45 3351.26,4389.45 3367.71,4405.9 3367.71,4424.69 v2(3381.71,4438.69)
NetR271_1: R271.1 R272.2 R273.1 R274.1 | length 259.1
  L1_Top Layer w6: R272.2@3941.09,5064.44 R272.2@3942.02,5065.37
  L1_Top Layer w9.84: R271.1@3941.09,5219.44 R271.1@3942.92,5217.61
  L1_Top Layer w10: R272.2@3942.02,5065.37 v2(3993.95,5065.37) ; R271.1@3942.92,5217.61 v2(3993.95,5217.61)
  L12_Bottom Layer w11: v2(3993.95,5065.37) v2(3993.95,5217.61)
NetR276_1: R276.1 R277.1 R282.2 | length 112
  L1_Top Layer w10: R277.1@4102.03,4999.77 4108.41,5006.15 R282.2@4154.41,5006.15 4155.79,5004.77 R276.1@4210.79,5004.77
NetR279_1: R279.1 R280.1 R283.2 | length 116.1
  L1_Top Layer w10: R280.1@4102.03,4954.77 4108.41,4948.39 R283.2@4154.41,4948.39 4165.79,4959.77 R279.1@4210.79,4959.77
NetR282_1: R282.1 R283.1 R285.1 | length 206.1
  L1_Top Layer w6: R285.1@4102.03,5049.77 R285.1@4105.65,5053.39
  L1_Top Layer w10: R285.1@4105.65,5053.39 v2(4154.41,5053.39)
  L12_Bottom Layer w11: v2(4154.41,4901.15) v2(4154.41,5053.39)
NetR286_1: R286.1 R287.2 R288.1 R289.1 | length 253.1
  L1_Top Layer w6: R287.2@4131.63,4598.08 R287.2@4133.01,4599.46 ; R286.1@4131.63,4748.08 R286.1@4133.01,4746.7
  L1_Top Layer w10: R287.2@4133.01,4599.46 v2(4184.01,4599.46) ; R286.1@4133.01,4746.7 v2(4184.01,4746.7)
  L12_Bottom Layer w11: v2(4184.01,4599.46) v2(4184.01,4746.7)
NetR299_1: R299.1 R300.1 R303.1 | length 198.8
  L1_Top Layer w10: R303.1@3934.14,4767.15 v2(3985.03,4767.15)
  L12_Bottom Layer w6: v2@3984.89,4767.29 v2(3985.03,4767.15)
  L12_Bottom Layer w11: v2@3984.89,4767.29 v2(3984.89,4915)
NetR344_2: R344.2 R351.2 Y1.3 | length 198.4
  L1_Top Layer w11: R344.2@5311.63,5668.72 5374.51,5668.72 R351.2@5374.63,5668.6 ccw(c5373.68,5669.55) 5375.03,5669.55 5375.03,5801.14 ccw(c5371.6,5801.14) Y1.3@5374.02,5803.56
NetR356_1: R356.1 U25.4@5405.97,6058.67 | length 349.9
  L1_Top Layer w11: R356.1@5319.44,6209.82 v2(5366.82,6209.82)
  L12_Bottom Layer w11: v2(5366.82,6209.82) cw(c5382.65,6193.99) 5382.65,6216.37 5441.03,6216.37 cw(c5441.03,6177.65) 5468.42,6205.03 cw(c5454.76,6191.37) 5474.08,6191.37 5474.08,6161.45 cw(c5457.01,6161.45) 5469.08,6149.37 cw(c5452.18,6166.27) 5452.18,6142.37 5432.39,6142.37 ccw(c5432.39,6115.06) 5413.08,6134.37 ccw(c5430.23,6117.22) 5405.97,6117.22 U25.4@5405.97,6058.67
NetR357_1: R357.1 U25.5@5505.97,6058.67 | length 353.5
  L1_Top Layer w11: v2(5709.82,6209.82) R357.1@5761.82,6209.82
  L12_Bottom Layer w11: U25.5@5505.97,6058.67 5505.97,6091.85 cw(c5605.97,6091.85) 5535.26,6162.56 5553.22,6180.52 cw(c5623.93,6109.81) 5623.93,6209.81 v2(5709.82,6209.82)
NetR358_2: R358.2 U25.2@5505.97,5913 | length 66.9
  L12_Bottom Layer w20: R358.2@5505.97,5846.11 U25.2@5505.97,5913
NetR386_1: R386.1 R387.2 U41.14 | length 172.8
  L1_Top Layer w10: R387.2@3112.5,11080 3151.83,11040.68 3217.92,11040.68 3234.87,11023.73 U41.14@3234.87,10996.6
NetR388_1: R388.1 R389.2 U44.14 | length 172.8
  L1_Top Layer w10: R389.2@2238.68,11080.86 2278,11041.54 2344.09,11041.54 2361.04,11024.59 U44.14@2361.04,10997.46
NetR390_2: R390.2 U73.3 | length 115.3
  L12_Bottom Layer w6: R390.2@4137.62,5704.37 4117,5724.99 4117,5765 4127.6,5775.6 U73.3@4158.74,5775.6
NetR391_2: R391.2 U73.4 | length 116.4
  L12_Bottom Layer w6: U73.4@4064.26,5775.6 4095.4,5775.6 4106,5765 4106,5727.75 R391.2@4082.62,5704.37
NetR393_2: R393.2 R397.2 R403.1 U74.15 | length 2714.2
  L1_Top Layer w11: R403.1@3279.8,4288.29 3225,4233.5 3225,4038.78 3318.33,3945.44 4035.44,3945.44 4085,3995 v2(4173,3995) ; v2(5126,4296) 5126.24,4296.24 R393.2@5165.92,4296.24 5165.64,4296.53 5165.64,4563.8 U74.15@5200.62,4598.78
  L12_Bottom Layer w11: v2(4173,3995) 4730,3995 5031,4296 v2(5126,4296)
NetR394_1: R394.1 U26.14 | length 131.5
  L1_Top Layer w11: U26.14@5707,10461.36 5744.09,10461.36 R394.1@5810.85,10528.12
NetR395_2: R395.2 U74.10 | length 69.2
  L1_Top Layer w6: R395.2@5160.46,4739.65 5171.11,4729.01 5171.11,4714.02 5181.88,4703.24 5188.02,4703.24 U74.10@5200.62,4690.65
NetR396_1: R396.1 U26.13 | length 116.4
  L1_Top Layer w11: U26.13@5707,10435.77 5780.5,10435.77 R396.1@5810.85,10466.12
NetR398_1: R398.1 U26.12 | length 106.4
  L1_Top Layer w11: U26.12@5707,10410.18 5804.79,10410.18 R398.1@5810.85,10404.12
NetR399_2: R399.2 U74.11 | length 69.6
  L1_Top Layer w6: R399.2@5137.13,4716.32 5147.77,4705.67 5163.9,4705.67 5174.11,4695.46 5174.11,4689.32 U74.11@5186.7,4676.73
NetR400_1: R400.1 U26.11 | length 121.4
  L1_Top Layer w11: U26.11@5707,10384.59 5768.38,10384.59 R400.1@5810.85,10342.12
NetR402_1: R402.1 U27.14 | length 125.5
  L1_Top Layer w11: R402.1@4808.31,9118.2 4868.93,9178.81 U27.14@4908.68,9178.81
NetR405_1: R405.1 U27.13 | length 110.4
  L1_Top Layer w11: R405.1@4808.31,9180.2 4839,9180.2 4863.2,9204.4 U27.13@4908.68,9204.4
NetR407_1: R407.1 U27.12 | length 105.4
  L1_Top Layer w11: R407.1@4808.31,9242.2 4820.52,9230 U27.12@4908.68,9230
NetR408_1: R408.1 R410.1 U75.5 | length 143.7
  L1_Top Layer w11: R408.1@3937.5,9284 4022.5,9284 4022.97,9283.53 U75.5@4081.01,9283.53
NetR409_1: R409.1 U27.11 | length 120.5
  L1_Top Layer w11: R409.1@4808.31,9304.2 4856.93,9255.59 U27.11@4908.68,9255.59
NetR416_1: R416.1 U28.4 | length 78
  L1_Top Layer w11: U28.4@6240.72,10032.51 6318.02,10032.51 R416.1@6318.5,10033
NetR421_1: R421.1 U29.14 | length 91.9
  L12_Bottom Layer w11: U29.14@5575.96,9214.61 5648.91,9214.61 R421.1@5662.32,9201.2
NetR423_1: R423.1 U29.13 | length 95.9
  L12_Bottom Layer w11: U29.13@5575.96,9240.2 5608.2,9240.2 5629,9261 5660.12,9261 R423.1@5662.32,9263.2
NetR424_1: R424.1 U29.12 | length 111
  L12_Bottom Layer w11: U29.12@5575.96,9265.8 5602.92,9265.8 R424.1@5662.32,9325.2
NetR432_1: R432.1 U30.14 | length 125.5
  L1_Top Layer w11: R432.1@3494.97,6594.22 3555.58,6654.83 U30.14@3595.33,6654.83
NetR433_1: R433.1 U31.14 | length 125.5
  L1_Top Layer w11: R433.1@3498.3,248.22 3558.91,308.84 U31.14@3598.66,308.84
NetR434_1: R434.1 U30.13 | length 110.4
  L1_Top Layer w11: R434.1@3494.97,6656.22 3519.17,6680.42 U30.13@3595.33,6680.42
NetR435_1: R435.1 U31.13 | length 110.4
  L1_Top Layer w11: R435.1@3498.3,310.22 3522.5,334.43 U31.13@3598.66,334.43
NetR436_1: R436.1 U30.12 | length 105.4
  L1_Top Layer w11: R436.1@3494.97,6718.22 3507.17,6706.01 U30.12@3595.33,6706.01
NetR437_1: R437.1 U31.12 | length 105.4
  L1_Top Layer w11: R437.1@3498.3,372.22 3510.5,360.02 U31.12@3598.66,360.02
NetR438_1: R438.1 U30.11 | length 120.5
  L1_Top Layer w11: R438.1@3494.97,6780.22 3496.58,6780.22 3545.19,6731.61 U30.11@3595.33,6731.61
NetR439_1: R439.1 U31.11 | length 120.5
  L1_Top Layer w11: R439.1@3498.3,434.22 3499.91,434.22 3548.52,385.61 U31.11@3598.66,385.61
NetR455_1: R455.1 U32.14 | length 125.5
  L1_Top Layer w11: R455.1@3494.97,7038.93 3555.58,7099.54 U32.14@3595.33,7099.54
NetR456_1: R456.1 U33.14 | length 125.5
  L1_Top Layer w11: R456.1@3498.3,692.93 3558.91,753.55 U33.14@3598.66,753.55
NetR458_1: R458.1 U32.13 | length 110.4
  L1_Top Layer w11: R458.1@3494.97,7100.93 3519.17,7125.13 U32.13@3595.33,7125.13
NetR459_1: R459.1 U33.13 | length 110.4
  L1_Top Layer w11: R459.1@3498.3,754.93 3522.5,779.14 U33.13@3598.66,779.14
NetR461_1: R461.1 U32.12 | length 105.4
  L1_Top Layer w11: R461.1@3494.97,7162.93 3507.17,7150.72 U32.12@3595.33,7150.72
NetR462_1: R462.1 U33.12 | length 105.4
  L1_Top Layer w11: R462.1@3498.3,816.93 3510.5,804.73 U33.12@3598.66,804.73
NetR464_1: R464.1 U32.11 | length 120.5
  L1_Top Layer w11: R464.1@3494.97,7224.93 3496.58,7224.93 3545.19,7176.31 U32.11@3595.33,7176.31
NetR465_1: R465.1 U33.11 | length 120.5
  L1_Top Layer w11: R465.1@3498.3,878.93 3499.91,878.93 3548.52,830.32 U33.11@3598.66,830.32
NetR487_1: R487.1 R488.2 | length 66.7
  L1_Top Layer w20: R487.1@4863.82,11167.31 4929.83,11167.31 R488.2@4930.32,11167.8
NetR490_1: R490.1 R491.1 R492.2 U39.6 | length 225.8
  L12_Bottom Layer w10: 2827.89,11265.86 2827.93,11265.83 2893.28,11265.83 U39.6@2893.32,11265.86
  L12_Bottom Layer w11: R492.2@2782.75,11292.31 2801.45,11292.31 2827.89,11265.86
  L12_Bottom Layer w20: R492.2@2782.75,11292.31 2782.75,11239.61 R490.1@2785.04,11237.33 2785.04,11189.31 R491.1@2784.82,11189.09
NetR494_1: R494.1 U41.2 | length 81.5
  L1_Top Layer w10: U41.2@3234.87,10866.68 3234.87,10790.23 R494.1@3238.42,10786.68
NetR495_2: R495.2 U41.11 | length 131.1
  L1_Top Layer w10: U41.11@3293.92,10996.6 3337.22,10996.6 R495.2@3399.3,11058.68
NetR496_2: R496.2 U41.10 | length 95.4
  L1_Top Layer w10: U41.10@3319.51,10971.01 3361.63,10971.01 R496.2@3399.3,11008.68
NetR497_2: R497.2 U41.9 | length 83.2
  L1_Top Layer w10: U41.9@3319.51,10951.32 3390.94,10951.32 R497.2@3399.3,10959.68
NetR498_2: R498.2 U41.7 | length 81.3
  L1_Top Layer w10: U41.7@3319.51,10911.95 3399.02,10911.95 R498.2@3400.3,10910.68
NetR499_2: R499.2 U41.6 | length 93
  L1_Top Layer w10: U41.6@3319.51,10892.27 3370.71,10892.27 R499.2@3400.3,10862.68
NetR500_2: R500.2 U41.5 | length 127.9
  L1_Top Layer w10: U41.5@3293.92,10866.68 3348.3,10866.68 R500.2@3400.3,10814.68
NetR501_1: R501.1 R502.2 R504.2 U42.6 | length 223.8
  L12_Bottom Layer w10: 2003,11265.82 U42.6@2026.32,11265.82
  L12_Bottom Layer w11: R504.2@1913.41,11288.69 1939.32,11288.69 1962.18,11265.82 2003,11265.82
  L12_Bottom Layer w20: R504.2@1913.41,11288.69 1913.41,11241.91 R501.1@1918.04,11237.28 1918.04,11189.37 R502.2@1918.13,11189.28
NetR503_1: R503.1 U42.7 | length 33.3
  L12_Bottom Layer w11: v1(1994,11289) 1996.41,11291.41 U42.7@2026.32,11291.41
NetR505_2: R505.2 U44.4 | length 99.2
  L1_Top Layer w10: U44.4@2400.41,10867.54 2400.41,10852.34 2443.09,10809.65 R505.2@2443.09,10786.03
NetR506_1: R506.1 U44.2 | length 81.5
  L1_Top Layer w10: U44.2@2361.04,10867.54 2361.04,10791.09 R506.1@2364.59,10787.54
NetR507_2: R507.2 U44.11 | length 131.1
  L1_Top Layer w10: U44.11@2420.09,10997.46 2463.39,10997.46 R507.2@2525.47,11059.54
NetR508_2: R508.2 U44.10 | length 95.4
  L1_Top Layer w10: U44.10@2445.69,10971.87 2487.8,10971.87 R508.2@2525.47,11009.54
NetR509_2: R509.2 U44.9 | length 83.2
  L1_Top Layer w10: U44.9@2445.69,10952.18 2517.12,10952.18 R509.2@2525.47,10960.54
NetR510_2: R510.2 U44.7 | length 81.3
  L1_Top Layer w10: U44.7@2445.69,10912.81 2525.2,10912.81 R510.2@2526.47,10911.54
NetR511_2: R511.2 U44.6 | length 93
  L1_Top Layer w10: U44.6@2445.69,10893.13 2496.88,10893.13 R511.2@2526.47,10863.54
NetR512_2: R512.2 U44.5 | length 127.9
  L1_Top Layer w10: U44.5@2420.09,10867.54 2474.47,10867.54 R512.2@2526.47,10815.54
NetR514_1: R514.1 R515.1 R516.2 U45.6 | length 248.2
  L12_Bottom Layer w10: 3663.5,11299.03 3691.38,11271.16 3741.16,11271.16 U45.6@3742.33,11269.99
  L12_Bottom Layer w11: R516.2@3621.17,11299.03 3663.5,11299.03
  L12_Bottom Layer w20: R515.1@3616.87,11185.79 3621.17,11190.09 R514.1@3621.17,11241.46 R516.2@3621.17,11299.03
NetR517_2: R517.2 U47.4 | length 99.2
  L1_Top Layer w10: U47.4@4111.21,10862.67 4111.21,10847.47 4153.9,10804.79 R517.2@4153.9,10781.17
NetR518_1: R518.1 U47.2 | length 81.5
  L1_Top Layer w10: U47.2@4071.84,10862.67 4071.84,10786.22 R518.1@4075.39,10782.67
NetR519_2: R519.2 U47.11 | length 131.1
  L1_Top Layer w10: U47.11@4130.9,10992.59 4174.19,10992.59 R519.2@4236.27,11054.67
NetR520_2: R520.2 U47.10 | length 95.4
  L1_Top Layer w10: U47.10@4156.49,10967 4198.6,10967 R520.2@4236.27,11004.67
NetR521_2: R521.2 U47.9 | length 83.2
  L1_Top Layer w10: U47.9@4156.49,10947.32 4227.92,10947.32 R521.2@4236.27,10955.67
NetR522_2: R522.2 U47.7 | length 81.3
  L1_Top Layer w10: U47.7@4156.49,10907.95 4236,10907.95 R522.2@4237.27,10906.67
NetR523_2: R523.2 U47.6 | length 93
  L1_Top Layer w10: U47.6@4156.49,10888.26 4207.68,10888.26 R523.2@4237.27,10858.67
NetR524_2: R524.2 U47.5 | length 127.9
  L1_Top Layer w10: U47.5@4130.9,10862.67 4185.27,10862.67 R524.2@4237.27,10810.67
NetR526_1: R526.1 R527.1 R528.2 U48.6 | length 266.7
  L12_Bottom Layer w10: R528.2@1203.63,11301.9 1241.36,11301.9 1276.06,11267.2 1325.37,11267.2 U48.6@1326.53,11266.03
  L12_Bottom Layer w20: R528.2@1203.63,11301.9 1203.63,11239.25 R526.1@1205.37,11237.5 1205.37,11194.47 R527.1@1220.04,11179.81
NetR529_2: R529.2 U50.4 | length 99.2
  L1_Top Layer w8: U50.4@1666.54,10869.4 1666.54,10857.01 1709.22,10814.32 R529.2@1709.22,10787.9
NetR530_1: R530.1 U50.2 | length 81.5
  L1_Top Layer w8: R530.1@1627.17,10792.95 U50.2@1627.17,10869.4
  L1_Top Layer w10: R530.1@1627.17,10792.95 R530.1@1630.72,10789.4
NetR533_1: R533.1 R534.1 R535.2 U51.6 | length 239
  L12_Bottom Layer w15: R533.1@502.37,11203.92 R534.1@502.37,11252.92 502.75,11253.3 R535.2@502.75,11306.33 562.59,11306.33 601.07,11267.85 U51.6@623.22,11267.85
NetR542_1: R542.1 U34.6 | length 114.7
  L1_Top Layer w10: U34.6@5520.39,9834.76 5579.58,9834.76 v2(5579.87,9834.47)
  L12_Bottom Layer w10: R542.1@5525.38,9832.97 5526.88,9834.47 v2(5579.87,9834.47)
NetR543_2: R543.2 U34.14 | length 124.6
  L1_Top Layer w10: U34.14@5520.39,9992.24 5598.66,9992.24 R543.2@5631.39,10024.97
NetR545_1: R545.1 R547.1 U56.4 | length 148.6
  L1_Top Layer w11: U56.4@5341.88,9334.25 5342.88,9335.25 R545.1@5342.88,9410.97 R547.1@5342.88,9482.47
NetR551_1: R551.1 U59.3 | length 147.3
  L12_Bottom Layer w10: v1@2381.32,8627.43 2381.32,8714.05 cw(c2400.64,8714.05) 2386.98,8727.71 ccw(c2368.86,8745.82) 2394.48,8745.82 U59.3@2394.49,8771.21
  other v1: 2381.27,8627.43
NetR552_1: R552.1 U59.2 | length 147.3
  L12_Bottom Layer w10: U59.2@2274.48,8771.21 2274.49,8745.82 ccw(c2300.1,8745.82) 2281.99,8727.71 cw(c2268.33,8714.05) 2287.65,8714.05 v1@2287.65,8627.43
  other v1: 2288.27,8627.43
NetR560_1: R560.1 U60.3 | length 147.3
  L12_Bottom Layer w10: U60.3@2275.24,7678.98 2275.24,7704.37 cw(c2300.86,7704.37) 2282.74,7722.49 ccw(c2269.09,7736.15) 2288.4,7736.15 v1@2288.4,7822.77
  other v1: 2289.08,7822.77
NetR561_1: R561.1 U60.2 | length 147.3
  L12_Bottom Layer w10: v1(2382.08,7822.77) 2382.08,7736.15 ccw(c2401.39,7736.14) 2387.74,7722.49 cw(c2369.62,7704.37) 2395.24,7704.37 U60.2@2395.24,7678.98
NetR569_1: R569.1 U61.3 | length 147.3
  L12_Bottom Layer w10: v1(2384.32,2281.8) 2384.32,2368.43 cw(c2403.63,2368.43) 2389.97,2382.08 ccw(c2371.86,2400.2) 2397.48,2400.2 U61.3@2397.48,2425.59
NetR570_1: R570.1 U61.2 | length 147.3
  L12_Bottom Layer w10: U61.2@2277.48,2425.59 2277.48,2400.2 ccw(c2303.1,2400.2) 2284.98,2382.08 cw(c2271.32,2368.43) 2290.64,2368.43 v1(2290.64,2281.8)
NetR578_1: R578.1 U62.3 | length 147.3
  L12_Bottom Layer w10: U62.3@2279.42,1333.02 2279.42,1358.41 cw(c2305.04,1358.41) 2286.92,1376.53 ccw(c2273.27,1390.18) 2292.58,1390.18 v1(2292.58,1476.8)
NetR579_1: R579.1 U62.2 | length 147.3
  L12_Bottom Layer w10: v1(2386.26,1476.8) 2386.26,1390.18 ccw(c2405.57,1390.18) 2391.92,1376.53 cw(c2373.8,1358.41) 2399.42,1358.41 U62.2@2399.42,1333.02
NetR586_1: R586.1 R587.2 R635.1 U63.1 | length 5082.3
  L1_Top Layer w11: v2(6028,7472) 6073,7472 6105.11,7439.89 R587.2@6105.11,7400.63 ; R586.1@6055.48,8146.01 6055.48,8125.63 6067.11,8114.01 v1(6069.11,8114.01)
  L4_Signal Layer 1 w5.5: v2(6028,7472) 6069.11,7513.11 v1(6069.11,8114.01)
  L10_Signal Layer 2 w6.5: v2(6028,7472) 6078,7422 6078,7052 5593,6567 5593,5615 5920,5288 5920,3948 6053.31,3814.68 v2(6053.31,3763.32)
  L12_Bottom Layer w11: U63.1@5926.76,3745.69 5977.27,3745.69 R635.1@5994.9,3763.32 v2(6053.31,3763.32)
NetR588_1: R588.1 U63.4 | length 51.8
  L12_Bottom Layer w11: R588.1@5837.38,3643 5838.18,3643.8 U63.4@5838.18,3694.51
NetR589_2: R589.2 R590.2 R634.1 U63.2 | length 3803.4
  L1_Top Layer w11: v2(6051.21,1258.71) 6108.75,1201.17 R589.2@6108.75,1057.43 ; R590.2@6059.13,1802.81 6059.13,1782.43 6070.75,1770.81 v1(6072.75,1770.81)
  L4_Signal Layer 1 w5.5: v2(6051.21,1258.71) 6072.75,1280.24 v1(6072.75,1770.81) 6152.94,1851 6552,1851 6643,1942 6643,2332 6623,2352 6623,3372 6533,3462 6121.31,3462 6053.31,3530 v2(6053.31,3698.31)
  L12_Bottom Layer w11: U63.2@5926.76,3720.1 5973.11,3720.1 R634.1@5994.9,3698.31 v2(6053.31,3698.31)
NetR591_1: R591.1 U34.44 | length 158.3
  L1_Top Layer w11: v2(4978,9783) 5010.07,9815.07 U34.44@5083.38,9815.07
  L12_Bottom Layer w11: v2(4978,9783) 5015.5,9783 R591.1@5017,9781.5
NetR636_1: R636.1 U64.4 | length 60.1
  L12_Bottom Layer w11: R636.1@5782.62,3428 5782.85,3428.23 U64.4@5842.61,3428.23
NetR646_2: R646.2 U65.2 | length 94.1
  L1_Top Layer w11: R646.2@1805.01,9036.66 1805.01,9044.86 cw(c1871.22,9044.86) 1824.4,9091.68 cw(c1850.61,9065.47) 1850.61,9102.54 U65.2@1855.38,9102.54
NetR647_2: R647.2 U65.8 | length 94.1
  L1_Top Layer w11: U65.8@1962.46,9102.54 1967.23,9102.54 cw(c1967.23,9065.47) 1993.44,9091.68 cw(c1946.63,9044.86) 2012.83,9044.86 R647.2@2012.83,9036.66
NetR648_2: R648.2 R649.1 | length 155.9
  L1_Top Layer w11: R648.2@1830.99,9010.68 R649.1@1986.85,9010.68
NetR650_2: R650.2 U66.2 | length 94.1
  L1_Top Layer w11: R650.2@1805.01,8832.72 1805.01,8824.52 ccw(c1871.22,8824.52) 1824.4,8777.7 ccw(c1850.61,8803.91) 1850.61,8766.84 U66.2@1855.38,8766.84
NetR651_2: R651.2 U66.8 | length 94.1
  L1_Top Layer w11: U66.8@1962.46,8766.84 1967.23,8766.84 ccw(c1967.23,8803.91) 1993.44,8777.7 ccw(c1946.63,8824.52) 2012.83,8824.52 R651.2@2012.83,8832.72
NetR652_2: R652.2 R653.1 | length 155.9
  L1_Top Layer w11: R652.2@1830.99,8858.7 R653.1@1986.85,8858.7
NetR654_2: R654.2 U67.8 | length 94.1
  L1_Top Layer w11: U67.8@1966.08,7680.46 1970.85,7680.46 cw(c1970.85,7643.39) 1997.06,7669.6 cw(c1950.24,7622.78) 2016.45,7622.78 R654.2@2016.45,7614.58
NetR655_2: R655.2 U67.2 | length 94.1
  L1_Top Layer w11: R655.2@1808.63,7614.58 1808.63,7622.78 cw(c1874.83,7622.78) 1828.02,7669.6 cw(c1854.23,7643.39) 1854.23,7680.46 U67.2@1859,7680.46
NetR656_2: R656.2 R657.1 | length 155.9
  L1_Top Layer w11: R656.2@1834.61,7588.6 R657.1@1990.47,7588.6
NetR658_2: R658.2 U68.2 | length 94.1
  L1_Top Layer w11: R658.2@1808.63,7410.64 1808.63,7402.44 ccw(c1874.83,7402.44) 1828.02,7355.62 ccw(c1854.23,7381.83) 1854.23,7344.76 U68.2@1859,7344.76
NetR659_2: R659.2 U68.8 | length 94.1
  L1_Top Layer w11: U68.8@1966.08,7344.76 1970.85,7344.76 ccw(c1970.85,7381.83) 1997.06,7355.62 ccw(c1950.24,7402.44) 2016.45,7402.44 R659.2@2016.45,7410.64
NetR660_2: R660.2 R661.1 | length 155.9
  L1_Top Layer w11: R660.2@1834.61,7436.62 R661.1@1990.47,7436.62
NetR662_2: R662.2 U69.8 | length 94.1
  L1_Top Layer w11: U69.8@1966.08,2756.86 1970.85,2756.86 cw(c1970.85,2719.79) 1997.06,2746 cw(c1950.24,2699.18) 2016.45,2699.18 R662.2@2016.45,2690.98
NetR663_2: R663.2 U69.2 | length 94.1
  L1_Top Layer w11: R663.2@1808.63,2690.98 1808.63,2699.18 cw(c1874.83,2699.18) 1828.02,2746 cw(c1854.23,2719.79) 1854.23,2756.86 U69.2@1859,2756.86
NetR664_2: R664.2 R665.1 | length 155.9
  L1_Top Layer w11: R664.2@1834.61,2665 R665.1@1990.47,2665
NetR666_2: R666.2 U70.2 | length 94.1
  L1_Top Layer w11: R666.2@1808.63,2487.04 1808.63,2478.84 ccw(c1874.83,2478.84) 1828.02,2432.02 ccw(c1854.23,2458.23) 1854.23,2421.16 U70.2@1859,2421.16
NetR667_2: R667.2 U70.8 | length 94.1
  L1_Top Layer w11: U70.8@1966.08,2421.16 1970.85,2421.16 ccw(c1970.85,2458.23) 1997.06,2432.02 ccw(c1950.24,2478.84) 2016.45,2478.84 R667.2@2016.45,2487.04
NetR668_2: R668.2 R669.1 | length 155.9
  L1_Top Layer w11: R668.2@1834.61,2513.02 R669.1@1990.47,2513.02
NetR670_2: R670.2 U71.8 | length 94.1
  L1_Top Layer w11: U71.8@1966.08,1337.76 1970.85,1337.76 cw(c1970.85,1300.69) 1997.06,1326.9 cw(c1950.24,1280.08) 2016.45,1280.08 R670.2@2016.45,1271.88
NetR671_2: R671.2 U71.2 | length 94.1
  L1_Top Layer w11: R671.2@1808.63,1271.88 1808.63,1280.08 cw(c1874.83,1280.08) 1828.02,1326.9 cw(c1854.23,1300.69) 1854.23,1337.76 U71.2@1859,1337.76
NetR672_2: R672.2 R673.1 | length 155.9
  L1_Top Layer w11: R672.2@1834.61,1245.9 R673.1@1990.47,1245.9
NetR674_2: R674.2 U72.2 | length 94.1
  L1_Top Layer w11: R674.2@1808.63,1067.94 1808.63,1059.74 ccw(c1874.83,1059.74) 1828.02,1012.92 ccw(c1854.23,1039.13) 1854.23,1002.06 U72.2@1859,1002.06
NetR675_2: R675.2 U72.8 | length 94.1
  L1_Top Layer w11: U72.8@1966.08,1002.06 1970.85,1002.06 ccw(c1970.85,1039.13) 1997.06,1012.92 ccw(c1950.24,1059.74) 2016.45,1059.74 R675.2@2016.45,1067.94
NetR676_2: R676.2 R677.1 | length 155.9
  L1_Top Layer w11: R676.2@1834.61,1093.92 R677.1@1990.47,1093.92
NetRMPCLK1_1: RMPCLK1.1 U19.30 | length 361.6
  L1_Top Layer w11: v2(2061.28,6253.92) 2126.2,6253.92 U19.30@2126.28,6253.99
  L12_Bottom Layer w9.84: RMPCLK1.1@1892.22,6452.81 1892.22,6375.81 2014.12,6253.92 v2(2061.28,6253.92)
NetRMPCLK2_1: RMPCLK2.1 U21.30 | length 352.5
  L1_Top Layer w11: U21.30@2425.34,3563.98 2425.41,3564.06 v2(2490.34,3564.06)
  L12_Bottom Layer w9.84: v2(2490.34,3564.06) 2537.5,3564.06 2637.47,3464.09 RMPCLK2.1@2637.47,3387.09 ; RMPCLK2.1@2659.39,3365.17 RMPCLK2.1@2659.39,3387.09
NetRMPDIR1_1: RMPDIR1.1 U19.32 | length 396.1
  L1_Top Layer w11: v2(2032.28,6222.92) 2046.48,6208.71 U19.32@2100.68,6208.71
  L12_Bottom Layer w9.84: RMPDIR1.1@1762.22,6347.81 1877.22,6347.81 2002.12,6222.92 v2(2032.28,6222.92)
NetRMPDIR2_1: RMPDIR2.1 U21.32 | length 387
  L1_Top Layer w11: U21.32@2450.93,3609.26 2505.13,3609.26 v2(2519.34,3595.06)
  L12_Bottom Layer w9.84: v2(2519.34,3595.06) 2549.5,3595.06 2652.47,3492.09 RMPDIR2.1@2767.47,3492.09 ; RMPDIR2.1@2767.47,3470.17 RMPDIR2.1@2789.39,3470.17
NetU34_27: U34.27 U54.2 | length 250.9
  L1_Top Layer w11: U54.2@5138.02,10245.97 5138.71,10245.28 5241.06,10245.28 5252.67,10233.67 U34.27@5252.67,10102.47
NetU34_29: U34.29 U54.1 | length 151.2
  L1_Top Layer w11: U54.1@5138.02,10208.57 5161.77,10208.57 5213.3,10157.04 U34.29@5213.3,10102.47
NetU74_1: U74.1 U74.4 U74.5 | length 368
  L1_Top Layer w11: U74.1@5250.73,4584.86 5289,4546.59 v2(5289,4501) ; U74.4@5292.49,4626.51 U74.4@5292.49,4626.62 ; U74.5@5292.49,4662.81 5303,4652.29 5303,4637.13 U74.4@5292.49,4626.62 ; v2(5376.35,4588.35) 5330.76,4588.35 U74.4@5292.49,4626.62
  L12_Bottom Layer w11: v2(5289,4501) v2(5376.35,4588.35)
OSCI: C739.1 U34.2 Y2.1 | length 432.1
  L1_Top Layer w6: U34.2@5520.39,9756.02 5561.82,9756.02 5566.16,9760.36 5580.31,9760.36 5590.31,9750.36 5590.31,9712.88 5605.49,9697.69 5608.72,9694.47 5647.18,9694.47 5671.18,9670.47 C739.1@5695.88,9670.47 5720.58,9670.47 5743.59,9693.47 5800.31,9693.47 5815.88,9677.89 Y2.1@5815.88,9618.26
OSCIN+: C407.2 R319.2 R321.2 R324.2 | length 975.6
  L1_Top Layer w10: C407.2@5132.28,5028.8 5185.31,5028.8 R319.2@5185.67,5029.16 R321.2@5234.67,5029.16 5243.87,5038.35 cw(c5255.17,5027.05) 5255.17,5043.03 5304.16,5043.03 ccw(c5304.16,5143.03) 5374.88,5072.32 5383.08,5080.52 5512.1,5209.54 ccw(c5421.59,5300.05) 5549.59,5300.05 5549.59,5321.34 cw(c5649.59,5321.34) 5578.87,5392.05 R324.2@5809.09,5622.27
OSCIN-: C408.2 C410.2 R327.2 R340.2 R341.2 | length 930.7
  L1_Top Layer w10: C408.2@5132.28,5085.8 5185.49,5085.8 R341.2@5185.67,5085.62 5233.96,5085.62 R340.2@5234.67,5084.91 5243.87,5075.72 ccw(c5255.17,5087.02) 5255.17,5071.03 5292.57,5071.03 ccw(c5292.57,5171.03) 5363.28,5100.32 5492.3,5229.34 ccw(c5421.59,5300.05) 5521.59,5300.05 5521.59,5321.34 ccw(c5421.59,5321.34) 5492.3,5392.05 R327.2@5262.08,5622.27
OSCIN_N: C408.1 C409.2 U24.44 | length 356.1
  L1_Top Layer w6: U24.44@4764.49,5008.62 4782.3,5008.62 4786.64,5004.28 4880.17,5004.28 4938.19,5062.3 4990.97,5062.3 5013.85,5085.17 C409.2@5031.66,5085.17 ; C408.1@5084.42,5085.17 C408.1@5085.04,5085.8
  L1_Top Layer w10: C409.2@5031.66,5085.17 C408.1@5084.42,5085.17
OSCIN_P: C406.2 C407.1 U24.43 | length 356
  L1_Top Layer w6: U24.43@4764.49,4988.94 4782.3,4988.94 4786.64,4993.28 4884.73,4993.28 4942.74,5051.3 4990.97,5051.3 5013.85,5028.42 C406.2@5031.66,5028.42 ; C407.1@5084.66,5028.42 C407.1@5085.04,5028.8
  L1_Top Layer w10: C406.2@5031.66,5028.42 C407.1@5084.66,5028.42
OSCO: C740.1 U34.3 Y2.2 | length 432.9
  L1_Top Layer w6: U34.3@5520.39,9775.7 5561.82,9775.7 5566.16,9771.36 5584.86,9771.36 5601.31,9754.92 5601.31,9717.44 5613.27,9705.47 5647.18,9705.47 5671.18,9729.47 C740.1@5695.88,9729.47 5720.58,9729.47 5745.59,9704.47 5800.31,9704.47 5815.88,9720.05 Y2.2@5815.88,9779.68
OSCOUT_N: R257.2 R266.2 R270.1 U24.41 | length 2438.1
  L1_Top Layer w6: v2(3384.5,4605.67) 3384.5,4548.41 R266.2@3385.75,4547.16 ; U24.41@4764.49,4949.57 4782.3,4949.57 4786.64,4945.22 4868.11,4945.22 4896.39,4973.5 4971.43,4973.5 v2(4985.93,4988)
  L4_Signal Layer 1 w4.9: v2(3384.5,4605.67) 3366,4624.17 3366,4771 3396,4801 3702.97,4801 3799.72,4897.75 3923.25,4897.75 3988,4833 4268.03,4833 4345.03,4756 4891.97,4756 5039,4903.03 5039,4957.22 5021.72,4974.5 4999.43,4974.5 v2(4985.93,4988)
OSCOUT_P: R253.2 R261.2 R263.1 U24.40 | length 2436.4
  L1_Top Layer w6: v2(3335.5,4605.67) 3335.5,4547.41 R261.2@3335.75,4547.16 ; U24.40@4764.49,4929.88 4782.3,4929.88 4786.64,4934.22 4872.67,4934.22 4900.94,4962.5 4972.43,4962.5 v2(4985.93,4949)
  L4_Signal Layer 1 w4.9: v2(3335.5,4605.67) 3354,4624.17 3354,4642 3342,4654 3342,4677 3354,4689 3354,4705 3343,4716 3343,4740 3354,4751 3354,4775.97 3391.03,4813 3698,4813 3794.75,4909.75 3928.22,4909.75 3992.97,4845 4273,4845 4350,4768 4887,4768 5027,4908 5027,4952.25 5016.75,4962.5 4999.43,4962.5 v2(4985.93,4949)
OUT_N: R326.1 R327.1 R356.2 | length 540.3
  L1_Top Layer w11: R327.1@5262.08,5669.52 R356.2@5262.04,6209.82
OUT_P: R323.1 R324.1 R357.2 | length 540.3
  L1_Top Layer w11: R324.1@5809.09,5669.52 R357.2@5809.06,6209.82
PD1: J6.1 R65.2 U8.K6 | length 1442.4
  L10_Signal Layer 2 w3.5: v1(2382.42,8114.86) 2366.67,8130.61 2340.06,8130.61 2334.67,8136 2334.67,8309.5 2344.5,8319.33 2391.01,8319.33 2398.08,8326.41 2398.08,8373.23 2407.67,8382.82 2420.33,8382.82 2453.67,8416.16 2453.67,8465.67
  L10_Signal Layer 2 w6.5: 2453.67,8465.67 2453.67,8529.35 2866.32,8942 v1(3057,8942) ; v1@3057,8946.64 v1@3057.38,8946.64
  L12_Bottom Layer w11: J6.1@3056.08,9074.99 3056.08,8993.51 R65.2@3057.68,8991.91 3057.68,8942.68 v1(3057,8942)
PD2: J17.1 R146.2 U17.K6 | length 1502.6
  L10_Signal Layer 2 w3.5: v1(2385.75,1768.86) 2370,1784.61 2343.39,1784.61 2338,1790 2338,1963.51 2347.83,1973.34 2394.34,1973.34 2401.41,1980.41 2401.41,2027.24 2411,2036.83 2423.66,2036.83 2457,2070.16 2457,2119.67
  L10_Signal Layer 2 w6.5: 2457,2119.67 2457,2183.36 2869.64,2596 v1(3126,2596)
  L12_Bottom Layer w11: v1(3126,2596) 3126.65,2596.65 R146.2@3126.65,2645.49 ; R146.2@3126.01,2646.14 J17.1@3126.01,2725.21
PG_3P3V: R386.2 R388.2 R513.1 U45.7 U47.14 | length 2207.3
  L1_Top Layer w10: v1(3705.27,11295.27) 3758,11242.54 3758,11218 3908,11068 4015.99,11068 4071.84,11012.15 U47.14@4071.84,10992.59
  L1_Top Layer w11: v1(3175.5,11080) 3175.5,11160.5 3310.27,11295.27 v1(3705.27,11295.27)
  L12_Bottom Layer w11: v1(2301.67,11080.86) 2352.94,11132.13 2613.87,11132.13 2750,10996 2983,10996 3067,11080 v1(3175.5,11080) ; v1(3705.27,11295.27) 3705.58,11295.59 U45.7@3742.33,11295.59
PG_RX1: J45.2 J46.F1 R473.1 | length 374.2
  L1_Top Layer w11: v1(6463.11,8820.01) 6422.11,8861.01 6422.11,9029.71 J45.2@6463.11,9070.71 6463.11,9158.33 R473.1@6464.48,9159.71
PG_RX2: J50.2 J51.F1 R478.1 | length 374.2
  L1_Top Layer w11: v1@6466.75,2476.81 6425.75,2517.81 6425.75,2686.51 6466.75,2727.51 6466.75,2815.13 R478.1@6468.13,2816.51
  other v1: 6466.44,2474.01
PRSNT_M2C_L_1: J46.H2 R476.2 | length 117.4
  L1_Top Layer w11: R476.2@6359.73,8886.01 6363.11,8882.63 v1(6363.11,8770.01)
PRSNT_M2C_L_2: J51.H2 R481.2 | length 112.6
  L1_Top Layer w11: v1@6366.75,2426.81 R481.2@6366.75,2539.43
  other v1: 6366.44,2424.01
PWR_SYNC: J58.1 U73.5 | length 5823.5
  L1_Top Layer w11: v2(4007,10027) 4007,10221 J58.1@4009,10223
  L10_Signal Layer 2 w6.5: v2(2751,6602) 3007,6858 3007,7546 3955,8494 3955,8895 3886.36,8963.64 3886.36,9906.36 v2(4007,10027)
  L12_Bottom Layer w11: v2(2751,6602) 2916,6437 3240,6437 3826.6,5850.4 U73.5@4064.26,5850.4
RESET: C423.2 R228.2 R368.2 R591.2 R603.1 U24.5 | length 6097.8
  L1_Top Layer w9.84: 4400,5008.62 U24.5@4418.03,5008.62
  L1_Top Layer w11: v1(4366.47,4988.94) 4386.16,5008.62 4400,5008.62
  L10_Signal Layer 2 w6.5: v2@4115,9497 v2(4115,9492) 4134,9473 4134,7461 4020,7347 4020,6859.68 4533.97,6345.71 4533.97,5790.11 4467.97,5724.11 4467.97,5167.75 4366.47,5066.25 v1(4366.47,4988.94)
  L12_Bottom Layer w11: v2(4115,9492) 4147,9460 4498.5,9460 R603.1@4608.5,9570 4723,9570 4871.5,9718.5 R591.2@5017,9718.5 ; v1(4366.47,4988.94) 4386.16,5008.62 R368.2@4425.03,5008.62 4425.03,5056.23 C423.2@4424.27,5057 4371.27,5057 R228.2@4369.89,5058.38
SDCLKOUT1+: R276.2 U24.3 | length 192
  L1_Top Layer w6: R276.2@4258.03,5004.77 4279.78,5004.77 4296.78,4987.77 4313.89,4987.77 4369.77,5043.65 4395.88,5043.65 4400.22,5047.99 U24.3@4418.03,5047.99
SDCLKOUT1-: R279.2 U24.4 | length 192
  L1_Top Layer w6: R279.2@4258.03,4959.77 4279.78,4959.77 4296.78,4976.77 4318.45,4976.77 4374.33,5032.65 4395.88,5032.65 4400.22,5028.31 U24.4@4418.03,5028.31
SDCLKOUT3+: R292.2 U24.13 | length 339
  L1_Top Layer w6: R292.2@4088.65,4865.77 4110.4,4865.77 4129.37,4846.8 4395.88,4846.8 4400.22,4851.14 U24.13@4418.03,4851.14
SDCLKOUT3+*: R292.1 R293.1 R299.2 | length 113.7
  L1_Top Layer w6: R293.1@3933.09,4865.44 R293.1@3939.8,4872.15 ; R299.2@3985.03,4872.15 R299.2@3991.41,4865.77
  L1_Top Layer w10: R293.1@3939.8,4872.15 R299.2@3985.03,4872.15 ; R299.2@3991.41,4865.77 R292.1@4041.41,4865.77
SDCLKOUT3-: R294.2 U24.14 | length 339.5
  L1_Top Layer w6: R294.2@4088.65,4815.77 4110.4,4815.77 4130.43,4835.8 4395.88,4835.8 4400.22,4831.46 U24.14@4418.03,4831.46
SDCLKOUT3-*: R294.1 R295.1 R300.2 | length 109.3
  L1_Top Layer w6: R295.1@3933.09,4815.44 R295.1@3934.14,4814.39 ; R300.2@3985.03,4814.39 R300.2@3986.41,4815.77
  L1_Top Layer w10: R295.1@3934.14,4814.39 R300.2@3985.03,4814.39 ; R300.2@3986.41,4815.77 R294.1@4041.41,4815.77
SDCLKOUT5+: R342.2 U24.22 | length 175.5
  L1_Top Layer w6: R342.2@4496.34,4626.92 4511.72,4642.29 4534.54,4642.29 4546.39,4654.15 4546.39,4744.34 4542.05,4748.69 U24.22@4542.05,4766.5
SDCLKOUT5+*: R342.1 R343.1 R348.2 | length 430.5
  L1_Top Layer w6: R343.1@4211.59,4333.02 R343.1@4212.97,4331.64 ; R348.2@4211.59,4382.29 4211.59,4400.1 4234.71,4423.22 4234.71,4451.56 4265.15,4482 4374.24,4482 4447.56,4555.32 4447.56,4578.13 R342.1@4462.94,4593.51
  L1_Top Layer w10: R343.1@4211.59,4333.02 R348.2@4211.59,4382.29
SDCLKOUT5-: R345.2 U24.23 | length 192.6
  L1_Top Layer w6: R345.2@4527.48,4596.86 4542.86,4612.24 4542.86,4635.06 4551.34,4643.55 ; 4545.13,4637.34 4557.39,4649.59 4557.39,4744.34 4561.73,4748.69 U24.23@4561.73,4766.5
SDCLKOUT5-*: R345.1 R346.1 R347.2 | length 421.9
  L1_Top Layer w6: R346.1@4267.97,4331.64 R346.1@4268.82,4332.48 ; R347.2@4268.82,4382.29 4268.82,4400.1 4245.71,4423.22 4245.71,4447 4269.71,4471 4378.8,4471 4455.88,4548.08 4478.69,4548.08 R345.1@4494.07,4563.46
  L1_Top Layer w10: R346.1@4268.82,4332.48 R347.2@4268.82,4382.29
SDCLKOUT5_N: R235.1 R346.2 U22.1 | length 3283.5
  L1_Top Layer w6: v1(2968.8,4261.13) 2986.94,4242.99 2986.94,3796.06 3143,3640 3409.78,3640 3424.5,3654.72 3424.5,3723.22 3432.78,3731.5 3451.22,3731.5 3459.5,3723.22 3459.5,3563.22 3474.22,3548.5 3501.78,3548.5 3516.5,3563.22 3516.5,3723.22 3524.78,3731.5 3543.22,3731.5 3551.5,3723.22 3551.5,3563.22 3566.22,3548.5 3593.78,3548.5 3608.5,3563.22 3608.5,3723.22 3616.78,3731.5 3635.22,3731.5 3643.5,3723.22 3643.5,3654.72 3658.22,3640 4110,3640 4245.97,3775.97 4245.97,4240.65 4267.97,4262.65 R346.2@4267.97,4284.39
  L12_Bottom Layer w6: U22.1@2968.8,4181.94 v1(2968.8,4261.13)
SDCLKOUT5_P: R234.2 R235.2 R343.2 U22.2 | length 3345.9
  L1_Top Layer w6: v1(3016.08,4261.16) 2997.94,4243.02 2997.94,4216 3015,4198.94 3015,4181 2997.94,4163.94 2997.94,4145.06 3015,4128 3015,4114 2997.94,4096.94 2997.94,3800.61 3147.56,3651 3405.22,3651 3413.5,3659.28 3413.5,3727.78 3428.22,3742.5 3455.78,3742.5 3470.5,3727.78 3470.5,3567.78 3478.78,3559.5 3497.22,3559.5 3505.5,3567.78 3505.5,3727.78 3520.22,3742.5 3547.78,3742.5 3562.5,3727.78 3562.5,3567.78 3570.78,3559.5 3589.22,3559.5 3597.5,3567.78 3597.5,3727.78 3612.22,3742.5 3639.78,3742.5 3654.5,3727.78 3654.5,3659.28 3662.78,3651 4105.44,3651 4234.97,3780.53 4234.97,4240.65 4212.97,4262.65 R343.2@4212.97,4284.39
  L12_Bottom Layer w6: v1(3016.08,4261.16) 3018.8,4258.43 U22.2@3018.8,4181.94
  L12_Bottom Layer w11: R234.2@3018.8,4112.54 U22.2@3018.8,4181.94
SDCLKOUT11+: R349.2 U24.56 | length 201.2
  L1_Top Layer w6: R349.2@4584.67,5307.31 4584.67,5280.09 4596.76,5268 4596.76,5135.11 4601.1,5130.76 U24.56@4601.1,5112.95
SDCLKOUT11+*: R349.1 R350.1 R367.2 | length 427.4
  L1_Top Layer w6: R367.2@4306.23,5496.99 4306.23,5479.18 4282.86,5455.81 4282.86,5438 4299.86,5421 4443.77,5421 4508.67,5356.1 4535.89,5356.1 R349.1@4551.27,5340.72
  L1_Top Layer w10: R367.2@4306.23,5496.99 R350.1@4306.23,5546.99
SDCLKOUT11-: R354.2 U24.57 | length 192.1
  L1_Top Layer w6: R354.2@4549.67,5272.31 4576.9,5272.31 4585.76,5263.45 4585.76,5135.11 4581.42,5130.76 U24.57@4581.42,5112.95
SDCLKOUT11-*: R354.1 R355.1 R366.2 | length 436.5
  L1_Top Layer w6: R366.2@4248.48,5496.99 4248.48,5479.18 4271.86,5455.81 4271.86,5433.44 4295.3,5410 4439.21,5410 4500.89,5348.32 4500.89,5321.1 R354.1@4516.27,5305.72
  L1_Top Layer w10: R366.2@4248.48,5496.99 R355.1@4248.48,5546.99
SDCLKOUT11_N: R194.1 R355.2 U20.1 | length 3262.1
  L1_Top Layer w6: R355.2@4249.86,5595.62 4249.86,5617.36 4271.86,5639.36 4271.86,5675 v2(4252.86,5694)
  L12_Bottom Layer w6: U20.1@1582.81,5636.03 1582.81,5559.78 R194.1@1583.28,5559.32 1583.28,5541.51 1565.16,5523.38 1565.16,5491 1580,5476.16 1580,5459.84 1565.16,5445 1565.16,5415.4 1596.56,5384 1620,5384 1635,5399 1651,5399 1666,5384 1682,5384 1697,5399 1714,5399 1729,5384 2890,5384 3134,5628 4249,5628 4271.86,5650.86 4271.86,5675 v2(4252.86,5694)
SDCLKOUT11_P: R193.2 R194.2 R350.2 U20.2 | length 3333
  L1_Top Layer w6: v2(4301.86,5694) 4282.86,5675 4282.86,5639.36 4304.86,5617.36 R350.2@4304.86,5595.62
  L12_Bottom Layer w6: U20.2@1532.81,5636.03 1532.81,5562.54 R194.2@1536.04,5559.32 1536.04,5541.51 1554.16,5523.38 1554.16,5410.84 1592,5373 2894.56,5373 2934.56,5413 3138.56,5617 4253.56,5617 4282.86,5646.3 4282.86,5675 v2(4301.86,5694)
  L12_Bottom Layer w10: U20.2@1532.81,5636.03 R193.2@1532.81,5706.52
SDCLKOUT13+: R360.1 R363.2 U24.60 | length 771.2
  L1_Top Layer w6: R363.2@4139,5558.5 4139,5540.69 4115.62,5517.32 4115.62,5466.38 4214,5368 4380.45,5368 4518.02,5230.42 4518.02,5135.11 4522.36,5130.76 U24.60@4522.36,5112.95
  L1_Top Layer w10: R363.2@4139,5558.5 R360.1@4139,5608.5
SDCLKOUT13-: R361.1 R362.2 U24.61 | length 771.2
  L1_Top Layer w6: R362.2@4081.25,5558.5 4081.25,5540.69 4104.62,5517.32 4104.62,5461.82 4209.44,5357 4375.89,5357 4507.02,5225.87 4507.02,5135.11 4502.68,5130.76 U24.61@4502.68,5112.95
  L1_Top Layer w10: R362.2@4081.25,5558.5 R361.1@4081.25,5608.5
SDCLKOUT13_N: J2.1 J51.Z21 R361.2 R391.1 | length 7242.1
  L1_Top Layer w10: J2.1@3917.7,6153.02 4047.28,6153.02 4096.29,6104 4096.29,5694.54 4082.62,5680.87 v1(4082.62,5657.13)
  L4_Signal Layer 1 w4.9: v1(4082.62,5657.13) 4104.12,5678.63 4104.12,5729.09 4156.03,5781 4827,5781 5067.49,5540.51 5695.46,5540.51 5922,5313.97 5922,4331.97 6320.97,3933 6616.97,3933 6860.86,3689.11 6860.86,1511.84 6842.03,1493.01 6785.44,1493.01 v1(6766.44,1474.01) v1@6766.44,1476.5
SDCLKOUT13_P: J1.1 J51.Z20 R360.2 R390.1 | length 7241.2
  L1_Top Layer w10: v1(4137.62,5657.13) 4137.62,5680.87 4124.29,5694.21 4124.29,6104 4173.29,6153 J1.1@4302.89,6153
  L4_Signal Layer 1 w4.9: v1(4137.62,5657.13) 4116.12,5678.63 4116.12,5724.12 4161,5769 4186,5769 4198,5757 4221,5757 4233,5769 4250,5769 4262,5757 4285,5757 4297,5769 4321,5769 4333,5757 4356,5757 4368,5769 4385,5769 4397,5757 4420,5757 4432,5769 4458,5769 4470,5757 4493,5757 4505,5769 4522,5769 4534,5757 4557,5757 4569,5769 4822.03,5769 5062.51,5528.51 5690.49,5528.51 5910,5309 5910,4327 6316,3921 6612,3921 6848.86,3684.14 6848.86,1516.81 6837.06,1505.01 6785.44,1505.01 v1(6766.44,1524.01) ; v1@6766.75,1526.81 v1@6767.99,1525.57
SMB_CLK: J32.9 J62.4 R81.1 R162.1 R352.1 R594.1 U9.13 U18.13 U25.8 U55.14 U57.14 U58.14 | length 19535.2
  L1_Top Layer w11: U9.13@3112.97,9534.95 3126.28,9534.95 3148.9,9557.57 3148.9,9593.89 3185.03,9630.03 v1(3187.61,9630.03) ; U18.13@3181.3,3189.19 3194.61,3189.19 3217.23,3211.81 3217.23,3248.12 3253.36,3284.26 R162.1@3255.94,3284.26 3293.68,3322 3397,3322 3513,3206 4177,3206 4293,3322 4339,3322 v1(4338,3323) ; U58.14@3430.04,4149.77 3483.84,4149.77 v2(3484.18,4149.43) ; v2(4138.43,6930.26) 4152.07,6943.9 U55.14@4195.96,6943.9 ; U57.14@4199.29,597.9 4246.23,597.9 v2(4246.4,597.73) ; v1(6580.28,10639.05) 6579.78,10639.55 R594.1@6579.78,10683.05 6740.95,10683.05 J32.9@6813,10611
  L4_Signal Layer 1 w5.5: v1(3187.61,9630.03) 3219.58,9662 3535,9662 3956,10083 4688,10083 5033,10428 5108,10428 J62.4@5159,10479 5206,10526 5832,10526 5923,10617 6558.24,10617 v1(6580.28,10639.05)
  L10_Signal Layer 2 w6.5: v1(3254.94,3285.26) 3254.94,3920.19 v2(3484.18,4149.43) 3647.25,4312.5 4057.5,4312.5 4128,4383 4371.19,4383 4756.05,4767.86 4756.05,5307.95 4725,5339 4725,6307 4138.43,6893.57 v2(4138.43,6930.26) 4256,7047.83 4256,9380 4317,9441 4612,9441 4739,9568 4925,9568 5120.34,9763.34 5120.34,9862.66 5266,10008.32 5266,10237 5202,10301 5202,10436 J62.4@5159,10479 ; v2(4246.4,597.73) 4216.27,597.73 4111.5,702.5 4111.5,2272.5 4338,2499 v1(4338,3323)
  L12_Bottom Layer w11: v2(4138.43,6930.26) 5082.47,5986.22 R352.1@5330.97,5986.22 5331.35,5985.84 U25.8@5393.18,5985.84
SMB_DAT: J32.10 J62.2 J62.6 R80.1 R161.1 R353.1 U9.12 U18.12 U25.7 U55.15 U57.15 U58.15 | length 20046.3
  L1_Top Layer w11: U9.12@3112.97,9515.27 3135.85,9515.27 v1(3187.61,9567.03) ; U18.12@3181.3,3169.5 3204.18,3169.5 R161.1@3255.94,3221.26 3264.28,3221.26 3294.48,3251.46 3343.38,3251.46 3343.84,3251 3420,3251 3492,3179 4234.5,3179 v1(4305.5,3250) ; v2(3375.89,4124.51) 3376.23,4124.17 U58.15@3430.04,4124.17 ; v2(4117.18,6953.47) 4133.2,6969.49 U55.15@4195.96,6969.49 ; v2(4142.17,623.49) U57.15@4199.29,623.49 ; v1(6419,10640) 6419,10637.33 6445.33,10611 J32.10@6713,10611
  L4_Signal Layer 1 w5.5: v1(3187.61,9567.03) 3166,9588.63 3166,9643 3207,9684 3525,9684 3941,10100 4680,10100 J62.6@5059,10479 5126,10546 5829,10546 5922,10639 6417.33,10639 6419,10640.67 v1(6419,10640)
  L10_Signal Layer 2 w6.5: v1(3254.94,3222.26) 3231,3246.19 3231,3979.62 v2(3375.89,4124.51) 3581.38,4330 4052,4330 4120,4398 4368.51,4398 4743.55,4773.04 4743.55,5302.78 4712.5,5333.82 4712.5,6301.82 4110,6904.32 4110,6946.29 v2(4117.18,6953.47) 4240,7076.29 4240,9398 4299,9457 4593,9457 4728,9592 4920,9592 5099,9771 5099,9868 5248,10017 5248,10144 5106,10286 5106,10432 J62.6@5059,10479 ; v2(4142.17,623.49) 4093,672.66 4093,2285 4305.5,2497.5 v1(4305.5,3250)
  L12_Bottom Layer w11: v2(4117.18,6953.47) 4117.18,6947.83 4110,6940.65 4110,6917 5075,5952 5652,5952 5680.97,5980.97 R353.1@5680.97,5986.22 5680.59,5985.84 U25.7@5618.77,5985.84 ; J62.6@5059,10479 5108,10528 5210,10528 J62.2@5259,10479
STATUS_LD1: R372.1 U24.31 | length 503.5
  L1_Top Layer w9.84: 4719.22,4730 U24.31@4719.22,4766.5
  L1_Top Layer w11: 4719.22,4730 4719.22,4647.19 4988.39,4378.01 R372.1@4988.39,4374.47
STATUS_LD2: R373.1 U24.48 | length 407.1
  L1_Top Layer w9.84: U24.48@4764.49,5087.36 4786.36,5087.36 4796.29,5097.29
  L1_Top Layer w11: 4796.29,5097.29 4837,5138 4837,5183 4901,5247 5041.11,5247 R373.1@5067.97,5220.14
